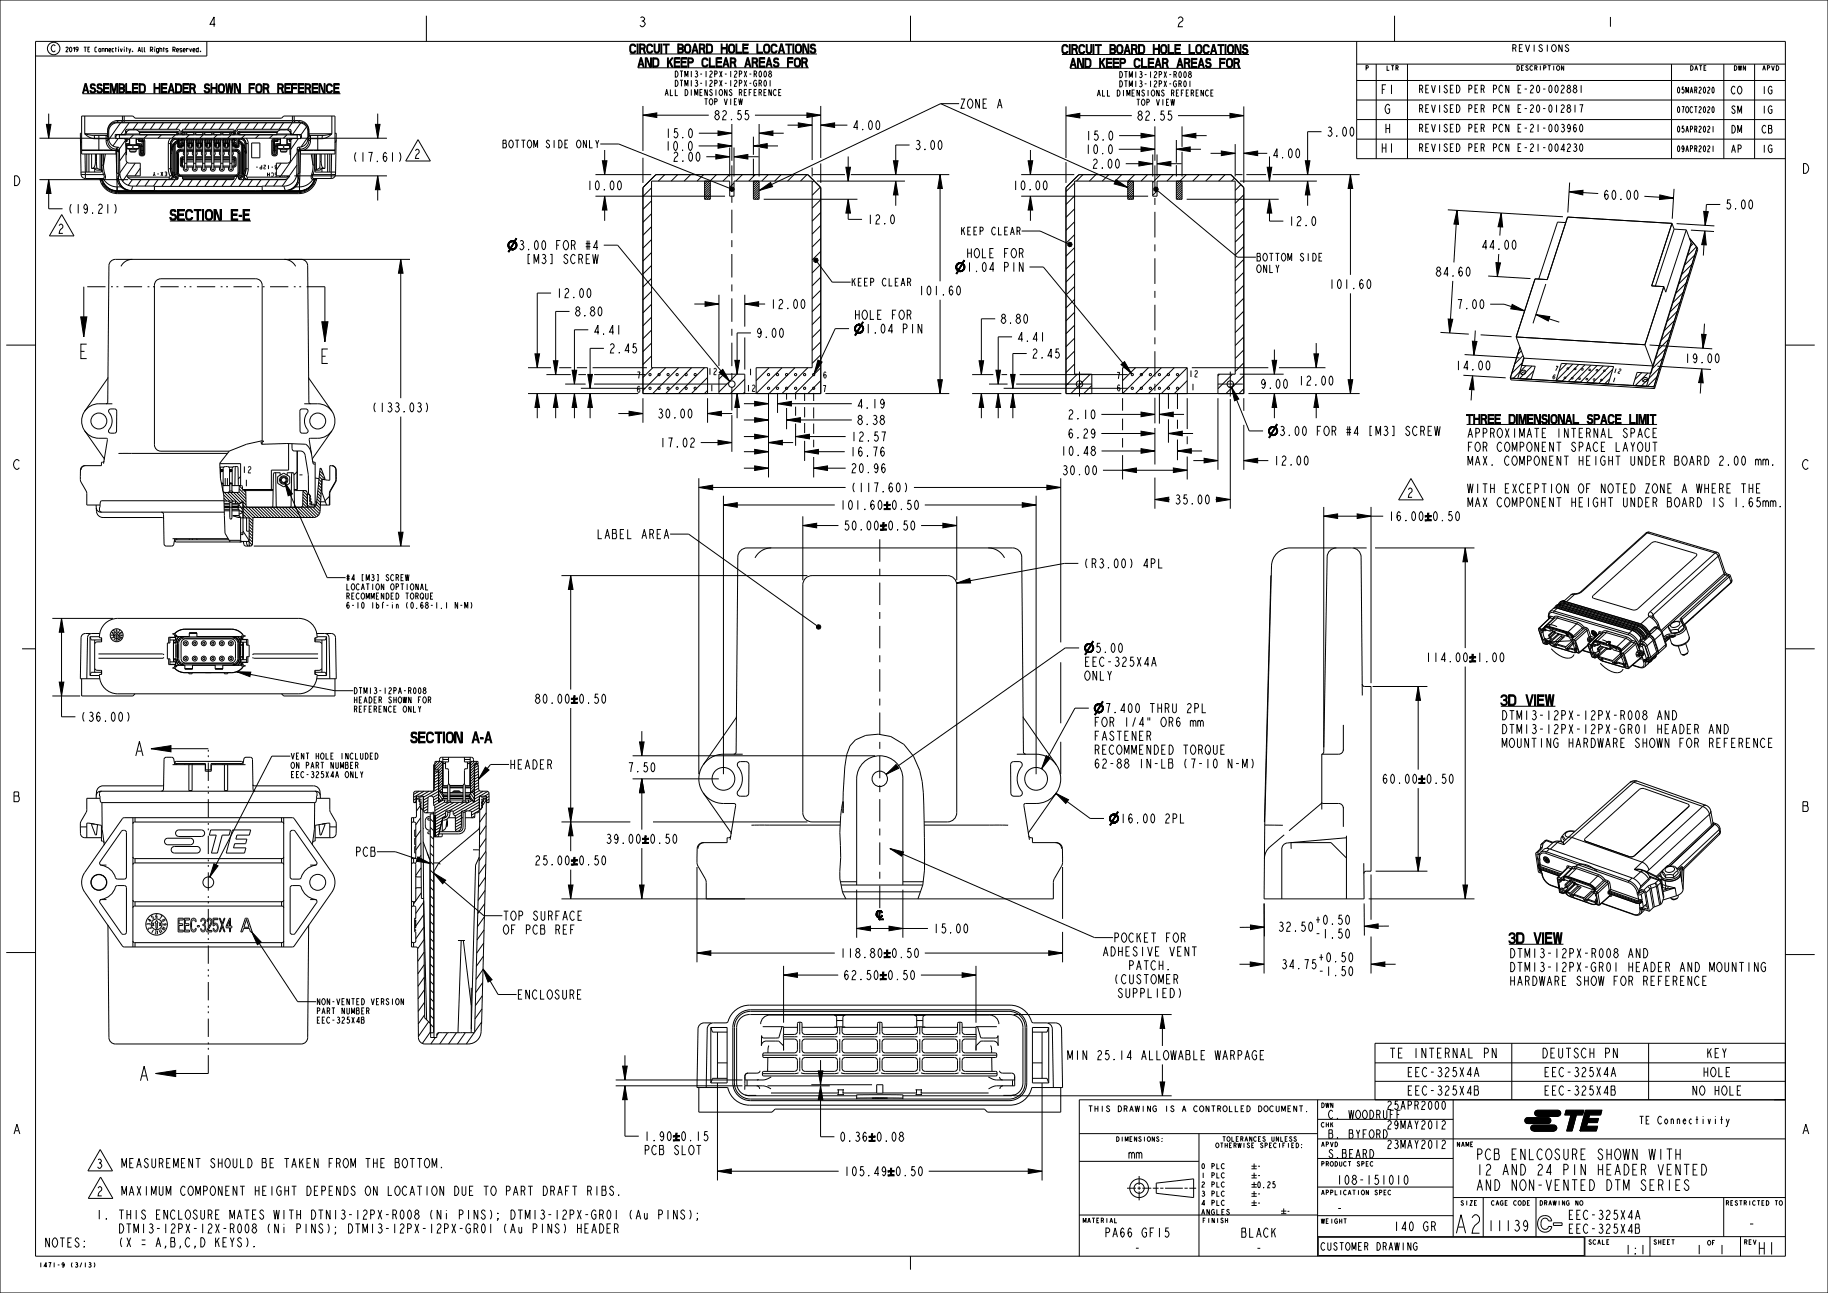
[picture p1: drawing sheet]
<svg xmlns="http://www.w3.org/2000/svg" width="594mm" height="420mm" viewBox="0 0 594 420" stroke-linecap="round" stroke-linejoin="round" font-family="sans-serif">
<defs><g id="words">
<text font-size="7.8" x="472.3" y="400.6">A2</text>
<text font-size="5.2" x="570.9" y="407.5">H1</text>
<g font-size="4.6">
<text x="54.2" y="71.6">SECTION E-E</text>
<text x="487.7" y="229.2">3D VIEW</text>
<text x="132.5" y="241.3">SECTION A-A</text>
<text x="490.3" y="306.5">3D VIEW</text>
<text x="479.5" y="376.7">PCB ENLCOSURE SHOWN WITH</text>
<text x="479.5" y="381.7">12 AND 24 PIN HEADER VENTED</text>
<text x="479.5" y="386.7">AND NON-VENTED DTM SERIES</text>
<text x="483.1" y="399.9">11139</text>
<text x="567.8" y="399.3">-</text>
</g>
<g font-size="4.1">
<text x="67.5" y="8.7">4</text>
<text x="207.2" y="8.7">3</text>
<text x="382.1" y="8.7">2</text>
<text x="521.8" y="8.7">1</text>
<text x="585.3" y="56.3">D</text>
<text x="4" y="60.3">D</text>
<text x="164.8" y="81.1">⌀3.00 FOR #4</text>
<text x="310.3" y="88.2">⌀1.04 PIN</text>
<text x="277.4" y="108.3">⌀1.04 PIN</text>
<text x="411.9" y="141.5">⌀3.00 FOR #4 [M3] SCREW</text>
<text x="4" y="152.5">C</text>
<text x="585.3" y="152.5">C</text>
<text x="352.2" y="212">⌀5.00</text>
<text x="355.3" y="231.5">⌀7.400 THRU 2PL</text>
<text x="4" y="260.4">B</text>
<text x="585.3" y="263.6">B</text>
<text x="360.2" y="267.4">⌀16.00</text>
<text x="284.4" y="298.8">℄</text>
<text x="451.7" y="343.7">TE INTERNAL PN</text>
<text x="501.1" y="343.7">DEUTSCH PN</text>
<text x="4" y="368.4">A</text>
<text x="585.3" y="368.4">A</text>
</g>
<g font-size="3.9">
<text x="202.3" y="17.3">CIRCUIT BOARD HOLE LOCATIONS</text>
<text x="342.7" y="17.5">CIRCUIT BOARD HOLE LOCATIONS</text>
<text x="207" y="21.8">AND KEEP CLEAR AREAS FOR</text>
<text x="347.4" y="22">AND KEEP CLEAR AREAS FOR</text>
<text x="26.8" y="30.2">ASSEMBLED HEADER SHOWN FOR REFERENCE</text>
<text x="311.7" y="35.2">ZONE A</text>
<text x="448.6" y="30.5">F1</text>
<text x="231.8" y="38.9">82.55</text>
<text x="369.3" y="39.1">82.55</text>
<text x="449.8" y="36.9">G</text>
<text x="216" y="44.8">15.0</text>
<text x="276.9" y="42.2">4.00</text>
<text x="352.6" y="45.6">15.0</text>
<text x="430.9" y="44.3">3.00</text>
<text x="449.8" y="43.2">H</text>
<text x="114.3" y="52.5">(17.61)</text>
<text x="134.4" y="51.5">2</text>
<text x="215.9" y="48.9">10.0</text>
<text x="218.4" y="52.4">2.00</text>
<text x="297.1" y="48.6">3.00</text>
<text x="352.4" y="50">10.0</text>
<text x="413.3" y="51.3">4.00</text>
<text x="448.6" y="49.6">H1</text>
<text x="354.7" y="54.7">2.00</text>
<text x="190.5" y="61.7">10.00</text>
<text x="328.8" y="61.7">10.00</text>
<text x="520.8" y="64.8">60.00</text>
<text x="21.8" y="69.3">(19.21)</text>
<text x="560.5" y="67.9">5.00</text>
<text x="18.6" y="75.8">2</text>
<text x="281.6" y="72.8">12.0</text>
<text x="418.5" y="73.3">12.0</text>
<text x="313.8" y="83.7">HOLE FOR</text>
<text x="481.2" y="81">44.00</text>
<text x="170.7" y="85.6">[M3] SCREW</text>
<text x="466.3" y="89.7">84.60</text>
<text x="298.3" y="95.9">101.60</text>
<text x="431.6" y="93.8">101.60</text>
<text x="180.6" y="96.7">12.00</text>
<text x="250.1" y="100.3">12.00</text>
<text x="473.1" y="100.3">7.00</text>
<text x="186.6" y="102.7">8.80</text>
<text x="277.4" y="103.8">HOLE FOR</text>
<text x="324.9" y="105.1">8.80</text>
<text x="192.7" y="108.6">4.41</text>
<text x="245.5" y="109.6">9.00</text>
<text x="330.4" y="110.9">4.41</text>
<text x="197.7" y="114.7">2.45</text>
<text x="335.1" y="116.3">2.45</text>
<text x="547.2" y="117.9">19.00</text>
<text x="421.7" y="125.1">12.00</text>
<text x="472.7" y="120.2">14.00</text>
<text x="409.3" y="126.2">9.00</text>
<text x="120.6" y="133.8">(133.03)</text>
<text x="213.4" y="135.8">30.00</text>
<text x="278.3" y="132.6">4.19</text>
<text x="278.3" y="137.9">8.38</text>
<text x="346.8" y="136.1">2.10</text>
<text x="476.6" y="137.6">THREE DIMENSIONAL SPACE LIMIT</text>
<text x="276.3" y="143.3">12.57</text>
<text x="346.8" y="142.3">6.29</text>
<text x="476.6" y="142.1">APPROXIMATE INTERNAL SPACE</text>
<text x="214.2" y="145.3">17.02</text>
<text x="276" y="148.2">16.76</text>
<text x="344.5" y="148">10.48</text>
<text x="476.6" y="146.6">FOR COMPONENT SPACE LAYOUT</text>
<text x="276.3" y="153.6">20.96</text>
<text x="344.9" y="154.3">30.00</text>
<text x="413.6" y="151.1">12.00</text>
<text x="476.6" y="151.1">MAX. COMPONENT HEIGHT UNDER BOARD 2.00 mm.</text>
<text x="276.3" y="159.8">(117.60)</text>
<text x="457" y="161.6">2</text>
<text x="476.6" y="160.1">WITH EXCEPTION OF NOTED ZONE A WHERE THE</text>
<text x="272.7" y="165.5">101.60±0.50</text>
<text x="381.5" y="163.7">35.00</text>
<text x="476.6" y="164.6">MAX COMPONENT HEIGHT UNDER BOARD IS 1.65mm.</text>
<text x="273.9" y="172.2">50.00±0.50</text>
<text x="451" y="169.2">16.00±0.50</text>
<text x="193.8" y="175">LABEL AREA</text>
<text x="351.9" y="184.5">(R3.00) 4PL</text>
<text x="463" y="215">114.00±1.00</text>
<text x="352.2" y="216.5">EEC-325X4A</text>
<text x="352.2" y="221">ONLY</text>
<text x="173.5" y="228.5">80.00±0.50</text>
<text x="487.7" y="233.8">DTM13-12PX-12PX-R008 AND</text>
<text x="26" y="234.3">(36.00)</text>
<text x="355.3" y="236">FOR 1/4&quot; OR6 mm</text>
<text x="487.7" y="238.3">DTM13-12PX-12PX-GR01 HEADER AND</text>
<text x="355.3" y="240.5">FASTENER</text>
<text x="355.3" y="245">RECOMMENDED TORQUE</text>
<text x="487.7" y="242.8">MOUNTING HARDWARE SHOWN FOR REFERENCE</text>
<text x="165.4" y="249.8">HEADER</text>
<text x="203.8" y="250.7">7.50</text>
<text x="355.3" y="249.5">62-88 IN-LB (7-10 N-M)</text>
<text x="448.9" y="254.5">60.00±0.50</text>
<text x="378.1" y="267.4">2PL</text>
<text x="196.6" y="274">39.00±0.50</text>
<text x="115.3" y="278.2">PCB</text>
<text x="173.5" y="281">25.00±0.50</text>
<text x="163.2" y="299">TOP SURFACE</text>
<text x="163.2" y="303.5">OF PCB REF</text>
<text x="303" y="303.1">15.00</text>
<text x="415.1" y="302.5">32.50</text>
<text x="427.1" y="300.3">+0.50</text>
<text x="427.1" y="304.8">-1.50</text>
<text x="272.7" y="311.1">118.80±0.50</text>
<text x="358.5" y="310.6">ADHESIVE VENT</text>
<text x="362" y="306.1">POCKET FOR</text>
<text x="490.3" y="311.1">DTM13-12PX-R008 AND</text>
<text x="366.7" y="315.1">PATCH.</text>
<text x="416.1" y="314.7">34.75</text>
<text x="428.1" y="312.5">+0.50</text>
<text x="428.1" y="317">-1.50</text>
<text x="490.3" y="315.6">DTM13-12PX-GR01 HEADER AND MOUNTING</text>
<text x="273.9" y="318.2">62.50±0.50</text>
<text x="362" y="319.6">(CUSTOMER</text>
<text x="490.3" y="320.1">HARDWARE SHOW FOR REFERENCE</text>
<text x="167.9" y="324.5">ENCLOSURE</text>
<text x="363.1" y="324.1">SUPPLIED)</text>
<text x="346.5" y="344.2">MIN 25.14 ALLOWABLE WARPAGE</text>
<text x="554.4" y="343.6">KEY</text>
<text x="457.3" y="349.7">EEC-325X4A</text>
<text x="501.8" y="349.7">EEC-325X4A</text>
<text x="553.2" y="349.7">HOLE</text>
<text x="457.3" y="355.7">EEC-325X4B</text>
<text x="501.8" y="355.7">EEC-325X4B</text>
<text x="549.7" y="355.7">NO HOLE</text>
<text x="209.1" y="370.6">1.90±0.15</text>
<text x="272.6" y="370.7">0.36±0.08</text>
<text x="209.1" y="375.1">PCB SLOT</text>
<text x="366.5" y="376.3">mm</text>
<text x="31.1" y="379.5">3</text>
<text x="39.2" y="379.3">MEASUREMENT SHOULD BE TAKEN FROM THE BOTTOM.</text>
<text x="274" y="381.9">105.49±0.50</text>
<text x="31.3" y="388.5">2</text>
<text x="39.2" y="388.3">MAXIMUM COMPONENT HEIGHT DEPENDS ON LOCATION DUE TO PART DRAFT RIBS.</text>
<text x="434.1" y="384.8">108-151010</text>
<text x="434.1" y="394">-</text>
<text x="31.1" y="396">1. THIS ENCLOSURE MATES WITH DTN13-12PX-R008 (Ni PINS); DTM13-12PX-GR01 (Au</text>
<text x="38.1" y="400.5">DTM13-12PX-12X-R008 (Ni PINS); DTM13-12PX-12PX-GR01 (Au PINS) HEADER</text>
<text x="213.5" y="396">PINS);</text>
<text x="358.8" y="401.9">PA66 GF15</text>
<text x="403.1" y="401.9">BLACK</text>
<text x="452.6" y="399.8">140 GR</text>
<text x="509.4" y="396.1">EEC-325X4A</text>
<text x="509.4" y="400.6">EEC-325X4B</text>
<text x="14.3" y="405.1">NOTES:</text>
<text x="38.1" y="405">(X = A,B,C,D KEYS).</text>
<text x="368.4" y="407">-</text>
<text x="407.9" y="407">-</text>
<text x="527.9" y="407.4">1:1</text>
<text x="551" y="407.4">1</text>
<text x="558.4" y="407.4">1</text>
</g>
<g font-size="3.6">
<text x="431.4" y="363.4">C. WOODRUFF</text>
<text x="450.4" y="360.4">25APR2000</text>
<text x="431.4" y="369.7">B. BYFORD</text>
<text x="450.4" y="366.7">29MAY2012</text>
<text x="431.4" y="376.1">S.BEARD</text>
<text x="450.4" y="373.1">23MAY2012</text>
</g>
<g font-size="3.3">
<text x="460.8" y="30.2">REVISED PER PCN E-20-002881</text>
<text x="562.3" y="30.5">CO</text>
<text x="572.3" y="30.5">IG</text>
<text x="460.8" y="36.5">REVISED PER PCN E-20-012817</text>
<text x="562.3" y="36.9">SM</text>
<text x="572.3" y="36.9">IG</text>
<text x="460.8" y="42.9">REVISED PER PCN E-21-003960</text>
<text x="562.3" y="43.2">DM</text>
<text x="572.3" y="43.2">CB</text>
<text x="163.1" y="48">BOTTOM SIDE ONLY</text>
<text x="460.8" y="49.2">REVISED PER PCN E-21-004230</text>
<text x="562.3" y="49.6">AP</text>
<text x="572.3" y="49.6">IG</text>
<text x="312" y="76.3">KEEP CLEAR</text>
<text x="408.1" y="84.8">BOTTOM SIDE</text>
<text x="408.1" y="88.5">ONLY</text>
<text x="276.4" y="92.9">KEEP CLEAR</text>
<text x="532.4" y="365.1">TE Connectivity</text>
<text x="429" y="406.1">CUSTOMER DRAWING</text>
</g>
<g font-size="2.9">
<text x="16.4" y="16.8">C</text>
<text x="491" y="16.8">REVISIONS</text>
</g>
<g font-size="2.6">
<text x="219.4" y="25.1">DTM13-12PX-12PX-R008</text>
<text x="219.4" y="28.1">DTM13-12PX-12PX-GR01</text>
<text x="363.8" y="25.2">DTM13-12PX-R008</text>
<text x="363.8" y="28.2">DTM13-12PX-GR01</text>
<text x="216.3" y="31.1">ALL DIMENSIONS REFERENCE</text>
<text x="228.8" y="34.1">TOP VIEW</text>
<text x="356.7" y="31.2">ALL DIMENSIONS REFERENCE</text>
<text x="369.2" y="34.2">TOP VIEW</text>
<text x="544.7" y="30.3">05MAR2020</text>
<text x="544.7" y="36.6">07OCT2020</text>
<text x="544.7" y="43">05APR2021</text>
<text x="544.7" y="49.3">09APR2021</text>
<text x="112.3" y="188.6">#4 [M3] SCREW</text>
<text x="112.3" y="191.6">LOCATION OPTIONAL</text>
<text x="112.3" y="194.6">RECOMMENDED TORQUE</text>
<text x="112.3" y="197.6">6-10 lbf-in (0.68-1.1 N-M)</text>
<text x="114.8" y="225.4">DTM13-12PA-R008</text>
<text x="114.8" y="228.4">HEADER SHOWN FOR</text>
<text x="114.8" y="231.4">REFERENCE ONLY</text>
<text x="94.3" y="246.6">VENT HOLE INCLUDED</text>
<text x="94.3" y="249.6">ON PART NUMBER</text>
<text x="94.3" y="252.6">EEC-325X4A ONLY</text>
<text x="102.7" y="326.4">NON-VENTED VERSION</text>
<text x="102.7" y="329.4">PART NUMBER</text>
<text x="102.7" y="332.4">EEC-325X4B</text>
<text x="408.3" y="379.8">-</text>
<text x="408.3" y="382.9">-</text>
<text x="408.3" y="385.8">0.25</text>
<text x="408.3" y="388.8">-</text>
<text x="408.3" y="391.8">-</text>
<text x="417.9" y="394.5">-</text>
</g>
<g font-size="2.5">
<text x="354.3" y="361.1">THIS</text>
<text x="363.6" y="361.1">DRAWING</text>
<text x="378.4" y="361.1">IS</text>
<text x="384" y="361.1">A</text>
<text x="387.7" y="361.1">CONTROLLED</text>
<text x="408.1" y="361.1">DOCUMENT.</text>
</g>
<g font-size="2.2">
<text x="390.2" y="379.7">0</text>
<text x="390.2" y="382.6">1</text>
<text x="393.3" y="379.7">PLC</text>
<text x="393.3" y="382.6">PLC</text>
<text x="390.2" y="385.6">2</text>
<text x="390.2" y="388.6">3</text>
<text x="393.3" y="385.6">PLC</text>
<text x="393.3" y="388.6">PLC</text>
<text x="390.2" y="391.6">4</text>
<text x="390.2" y="394.6">ANGLES</text>
<text x="393.3" y="391.6">PLC</text>
</g>
<g font-size="2">
<text x="21.1" y="16.8">2019 TE Connectivity. All Rights Reserved.</text>
<text x="443.5" y="22.9">P</text>
<text x="450.4" y="22.9">LTR</text>
<text x="492.6" y="22.9">DESCRIPTION</text>
<text x="549" y="22.9">DATE</text>
<text x="563.2" y="22.9">DWN</text>
<text x="572.5" y="22.9">APVD</text>
<text x="429.2" y="359.8">DWN</text>
<text x="362.5" y="370.8">DIMENSIONS:</text>
<text x="397" y="370.7">TOLERANCES</text>
<text x="412.5" y="370.7">UNLESS</text>
<text x="429.2" y="366.1">CHK</text>
<text x="394.8" y="372.8">OTHERWISE</text>
<text x="408.9" y="372.8">SPECIFIED:</text>
<text x="429.2" y="372.5">APVD</text>
<text x="473.2" y="372.5">NAME</text>
<text x="429.2" y="378.8">PRODUCT</text>
<text x="440.4" y="378.8">SPEC</text>
<text x="429.2" y="388.1">APPLICATION</text>
<text x="446" y="388.1">SPEC</text>
<text x="474.4" y="391.5">SIZE</text>
<text x="484.4" y="391.5">CAGE</text>
<text x="491.5" y="391.5">CODE</text>
<text x="500.1" y="391.5">DRAWING</text>
<text x="511.4" y="391.5">NO</text>
<text x="560.6" y="391.5">RESTRICTED</text>
<text x="576.1" y="391.5">TO</text>
<text x="351.7" y="397.2">MATERIAL</text>
<text x="390.6" y="397.2">FINISH</text>
<text x="429.2" y="397.4">WEIGHT</text>
<text x="516" y="404.2">SCALE</text>
<text x="537.2" y="404.2">SHEET</text>
<text x="554.7" y="404.4">OF</text>
<text x="566.6" y="404.2">REV</text>
<text x="12.5" y="411.6">1471-9</text>
<text x="22.4" y="411.6">(3/13)</text>
</g>
</g></defs>
<path d="M26.2 102.9h2l-1 6.5zM104.6 104.5h2l-1 6.5zM49.1 243.2l6.5-1v2zM50.6 348.7l6.5-1v2zM495.8 363.3l.6-.3h6.6a.95 .95 0 0 1 .9 .9 .95 .95 0 0 1-.8 1l-6.7 .1a.95 .95 0 0 1-.8-.6 .95 .95 0 0 1 .2-1.1zM497.7 365.7l.7-.2h6.5a.95 .95 0 0 1 1 .8 .95 .95 0 0 1-.9 1l-6.6 .1a.95 .95 0 0 1-.9-.6 .95 .95 0 0 1 .2-1.1zM499 360.9l.6-.3h6.6a.95 .95 0 0 1 .9 .9 .95 .95 0 0 1-.8 1h-6.7a.95 .95 0 0 1-.8-.5 .95 .95 0 0 1 .2-1.1zM508.9 360.6h5.8l-.4 1.5h-2.1l-1.4 5.3h-1.7l1.4-5.3h-2zM515.8 364.6l-.3 1.3h3.6l-.4 1.5h-5.3zM516.5 362.1l-.3 1.2h3.2l-.3 1.3h-3.3l-2.4 2.8zM515.2 360.6h5.3l-.4 1.5h-3.6l-3.1 5.3z" fill="#000"/>
<g fill="none" stroke="#000" stroke-width=".32">
<path d="M0 0h594v420h-594zM11.6 13.4h568.6v394.6h-568.6zM67.2 13.4v4.8h-55.6M138.6 5.1v8.3M295.9 5.1v8.3M440.8 13.4v38.1h139.4M453.2 5.1v8.3M27.5 37.7v5.8M37.9 39.7l-1.1 .2-.9 .6-.6 .9-.2 1M37.9 39.7l.2 .2M37.9 39.7h1.4M38.1 39.9l-1 .2-.9 .6-.7 .9-.2 1.1"/>
<path d="M38.1 39.9h59.1M38.4 39.1l-.5 .6M38.4 39.1l-1.3 .3-1.1 .7-.8 1-.2 1.3M38.4 39.1l1.4 .1M39.2 39.9l-3.8 5.4M39.3 39.7h1.1M39.8 39.2l-.5 .5M39.8 37.7v1.5M39.8 39.2h55.8M40.4 37.7v2M40.4 39.7h54.6M42 39.9l-2.7 3.8"/>
<path d="M44.8 39.9l-1.5 2.1M47.5 39.9l-1.4 2.1M50.3 39.9l-1.4 2.1M53.1 39.9l-1.5 2.1M55.9 39.9l-1.5 2.1M58.7 39.9l-1.5 2.1M61.5 39.9l-1.5 2.1M64.3 39.9l-1.5 2.1M67.1 39.9l-1.5 2.1M69.9 39.9l-1.5 2.1M72.6 39.9l-1.4 2.1M75.4 39.9l-1.4 2.1"/>
<path d="M78.2 39.9l-1.9 2.7M81 39.9l-1.5 2.1M83.8 39.9l-1.5 2.1M86.6 39.9l-1.5 2.1M89.4 39.9l-1.5 2.1M92.2 39.9l-1.5 2.1M94.9 39.9l-1.4 2.1M95 37.7v2M95.6 39.2l.4 .5M95.6 37.7v1.5M96 39.7h-1M97 39.1l.5 .6"/>
<path d="M97 39.1l1.3 .3 1.1 .7 .7 1 .3 1.3M97 39.1l-1.4 .1M97.2 39.9l1.1 .2 .9 .6 .6 .9 .2 1.1M97.5 39.7l1.1 .2 .9 .6 .6 .9 .2 1M97.5 39.7h-1.5M97.5 39.7l-.3 .2M97.7 39.9l-2.6 3.8M107.8 37.7v5.8M440.8 26.1h139.4M440.8 32.5h139.4M440.8 20.8h139.4M440.8 38.8h139.4"/>
<path d="M447.2 20.8v30.7M457.4 20.8v30.7M513.3 34h1l-.5 2.5M543.1 20.8l.1 30.7M560.1 20.8l.1 30.7M570.1 20.8l.1 30.7M26.1 45.4l.4 .9M26.3 56.6a1.4 1.4 0 0 0 1.4 1.4M26.3 56.6l1.4 .1M26.5 48.7l.2 .2M26.5 48.7v-11h16.7l.7 .7h47.6l.7-.7h16.6v11M26.5 43.3h-.4l.2 13.3"/>
<path d="M26.5 48.7h10M27.5 43.5l1.7 1.2 1.5 .4M27.5 43.5l3 .5M27.5 43.5h7.6M27.6 50l.1 6.7M27.7 56.7h6M27.7 56.7v1.3M27.7 58h5.6M28.2 50v5.9M28.9 50v5.9M29.8 50v4.7h.9M30.2 54.6l-.4 .1"/>
<path d="M30.5 44l.2 1.1M30.5 44h4M30.7 45.1h4.3M31 52.5l-.2 1.5-.6 .6M31 50v2.5M31.3 52.5l.2 2.1M31.3 50v2.5M31.3 52.5h-.3M31.5 54.6l1 .5M31.5 54.6h-1.3M32.1 44v4.9M32.4 58a5.9 5.9 0 0 0 5.9 4.9h58.8a5.9 5.9 0 0 0 5.8-4.9"/>
<path d="M32.5 58.4h.5M32.5 55.1l.5 .1M32.5 50v5.1M32.7 58l.5 .4M32.8 58l.5 .4M33 55.3l-1.7-.1-.5-.4v1.1M33 50v5.9h-6.7M33 58.4h.1M33 58.4l.3 .1M33 58v.4M33 58.4l.5 1.4M33 58.4l.2 .1"/>
<path d="M33.1 59.8h.4M33.1 53.6l.5 .1M33.1 53.6l.6 3.1M33.2 50l-.1 3.6M33.2 58.4a5.1 5.1 0 0 0 4.9 3.6M33.3 58l.4 .3M33.3 58.4l.7 1.4 1.1 1.1 1.4 .8 1.5 .2M33.3 58.4h-.1M33.3 58h.1M33.5 59.8a5.6 5.6 0 0 0 4.8 2.8M33.5 59.8l.3-.1a5.2 5.2 0 0 0 4.5 2.5h58.8a5.2 5.2 0 0 0 4.5-2.5l.3 .1M33.5 48.9h4.5"/>
<path d="M33.6 53.7l.5 2.9M33.7 56.7l.2 .9-.6 .4M33.7 58.3l-.4 .1M33.7 50l-.1 3.7M33.7 58.3h.1M33.7 58.3l1.9 1.8 2.5 .6M34.1 56.6l.2 1.1-.6 .6M34.1 56.6l-.4 .1M34.2 50l-.6 3.7M34.5 45.6l.5 1.9 1.5 1.2M34.5 45.6h.5M34.5 44l.6 .5"/>
<path d="M35 42.4v1.2l-.5 .4M35 42.4h.1M35 45.6l.2 1.1 .6 .9 .9 .6 1.1 .2M35 45.1v.5M35 44.5l-.5-.5v1.6M35 44.5v.6M35 44.5h.1M35.1 43.5v1M35.1 42.4v1.1M35.1 42.4l.2 .3M35.3 45l.2 1.1 .7 .9 .9 .6 1 .2M35.3 42.7v2.3"/>
<path d="M35.3 45l-.3 .6M36.5 48.7v.2M36.5 48.7l1.4 .1M37.4 45h.1M37.4 44.3h.3M37.4 45h2.8l.6 .4 .2 6.6 .3 .7 .7 .3h3.6v4.1h-4.4l.8 .9 1.1 .4M37.7 44.3v.7M37.7 49h.2M37.7 49l.2 7.2M37.7 48.9v.1M37.8 48.4v.5M37.8 48.4h.1"/>
<path d="M37.9 48.9v.1M37.9 49v7.2M37.9 49l.5 .4M37.9 48.9l.5 .5M37.9 56.2v1.2M37.9 56.2l.6 .4M37.9 57.4l.1 .6M37.9 57.4l.6 .4M37.9 48.8h.3M37.9 48.4l.6 .6M37.9 48.4v.4M38 48.8h.1"/>
<path d="M38 48.8v.1M38 48.9l.5 .5M38 58l.4 1.4 .9 1.3M38 58l.5 .2M38 58l.1 2.7M38.1 47.8l-.3 .6M38.1 47.8h.2M38.2 48.8h.1M38.2 48.8l.3 .2M38.3 47.8l.5 .5M38.3 47.8l-.4 .6M38.3 43.8l-.4 .1-.2 .4"/>
<path d="M38.3 43.7v.1M38.3 43.8h58.8M38.4 45l-1.7 2.4M38.4 49.4l.1 7.2M38.4 49.4h.1M38.5 56.6v1.2M38.5 57.8v.4M38.5 49v.4M38.5 57.7l.3 1.6 .9 1.4 1.4 .9 1.6 .3M38.5 57.7v.1M38.5 58.2l.4 1.3 .8 1.2M38.8 48.3l.1 8"/>
<path d="M38.8 48.3l-.3 .7M38.9 56.3l.4 1.6 .9 1.4 1.3 .8 1.6 .4M38.9 56.3l-.4 1.4M40.4 45.1h.7M40.8 45.4h.3M40.8 42.6h.5M40.8 43.1h.3M40.8 43l.1-.7 .4-.3h16.8l.2 .6h1l.2-.6h16.4l.1 .6h1.1l.2-.6h16.8l.4 .3 .1 .7M40.8 43l-.6 .7h-2.8v1.3M40.8 43h.3M40.8 45.5l-2 2.9M40.9 47.5h.3"/>
<path d="M40.9 49.4l-2 2.9M40.9 49.9h.2M41 46.7h-.1M41 47h-.1M41 46.7v.3M41 47l.1 .2M41 46.7h1M41.1 47.2l-.2 .1M41.1 49.9l-.2 .5M41.1 47.2v2.7M41.1 47.2h.3M41.1 45.1v.3"/>
<path d="M41.1 44.9v.2M41.1 45.4l.2 .2h-.5M41.3 44.9v.4M41.3 45.3v.7h-.4M41.3 45.3h.7M41.3 52.7l-2.4 3.5M41.5 57.5h13.5M42 44.9v2.1h-1M42.1 49.1h2.1l-.2 .3h-1.6zM42.2 42.2l-1 .6-.2 .7M42.2 42.2h.1M42.3 42.2h1.9"/>
<path d="M42.4 42.2h-.2M43 58.3l-1.3 1.9M43.4 43.8l-1.1 1.1M43.9 53l-4.1 5.9M44.2 42.2h.1M44.2 42.2l1 .6 .2 .7M44.3 44.9v2.1h1.1M44.3 46.7h1.1M44.3 45.3h.7M45 47.2h.2M45 45.3v.7h1.5M45 44.9v.4"/>
<path d="M45 42.6h12.5M45.1 47.5h.5M45.2 45.4l-.2 .2h1.2M45.2 45.4h1.1M45.2 45.1v.3M45.2 44.9v.2M45.2 45.1h1.1M45.2 47.2l.4 .3M45.2 49.9l.2 .5 .5 .2M45.2 47.2v2.7M45.2 49.9h.4M45.3 43h12.2"/>
<path d="M45.3 43.1h12.1M45.4 46.7l.6 .3 .1 .4h-.4M45.4 47l.3 .4M45.4 46.7v.3M45.4 47l-.2 .2M45.6 54.7l-1.8 2.4M45.6 49.9l.3 .4M45.6 47.5v2.4M45.7 48.6l.4 .3M45.7 48.6l-.1 1.3M45.7 47.5v1.1M45.7 47.4v.1"/>
<path d="M45.7 47.4l-.1 .1M45.7 47.5h.8M45.8 58.4l-1.5 2.1M45.9 50.3v.3M45.9 50.6h.4M45.9 50.3h.4M46.1 48.9l-.2 1.4M46.1 48.9h.1M46.1 47.5v1.4M46.2 45.6l.3 .4M46.2 47.5v1.4M46.2 45.6v1.9"/>
<path d="M46.2 48.9l.1 1.4M46.3 45.1l.5 .2 .2 .5M46.3 45.4l.4 .4M46.3 45.1v.3M46.3 45.4l-.1 .2M46.3 50.3v.3M46.5 47.5v1.1M46.5 46v1.5M46.5 48.6l-.3 .3M46.5 48.6l.2 1.3M46.7 49.9l-.4 .4M46.7 45.8v4.1"/>
<path d="M46.7 45.8l-.2 .2M46.7 49.9h.3M46.7 45.8h.3M47 49.9l-.2 .5-.5 .2M47 45.8v4.1M47.9 43.8l-1.1 1.1M48.6 58.4l-1.5 2.1M51.3 58.4l-1.4 2.1M52.4 43.8l-1.1 1.1M54.1 58.4l-1.5 2.1M54.7 54.8l.5 2.3M54.7 46.6v8.2"/>
<path d="M54.7 54.8h1.1M54.7 46.6h.7M55.2 57.1l-.2 .4M55.4 44.9l-.5 .8-.2 .9M55.4 46.6l.2 9.5a1.32 1.32 0 0 1-.4 2.1l-12.7 .1M55.4 46.6v.1M55.4 49.8h.4M55.4 46.7h.4M55.8 47.5l-.4 2.3M55.8 46.7v.8M55.8 47.5l.2 .1M55.8 54.8l.4 1.8"/>
<path d="M55.8 49.8v5M55.9 48l-.4 1.5v5.3l.4 2M55.9 48l.3 .1M55.9 56.8h.1M55.9 56.8l.1 .4M55.9 56.8l-.7 .3M56 47.6l-.6 2.2M56 57.2l-.1 .5-.6 .6h-.3v-.8M56.2 56.1v.5M56.2 48.1l-.4 1.7M56.2 48.1v8M56.2 56.1h.7"/>
<path d="M56.2 56.6l.1 .1M56.2 56.6l-.3 .2M56.3 56.7l.1 .4M56.3 56.7l-.4 .1M56.4 57.1l-.1 .7-.4 .6M56.4 57.1l1.1 1.2M56.4 57.1l-.4 .1M56.5 47v9.1l.5 1.4 .8 .6M56.5 47l-.3 1.1M56.6 47h-.1M56.6 47h.3M56.6 47h.1"/>
<path d="M56.6 46.9l-.7 1.1M56.6 46.9v.1M56.6 46.8v.1M56.6 46.8h.1M56.7 46.8l-.1 .1M56.7 46.8l.2 .2M56.8 44.9l-1 .6-.4 1.1M56.9 56.1l.4 1.1 .6 .5M56.9 47v9.1M56.9 58.4l-1.5 2.1M57 43.8l-1.1 1.1M57.1 44.9l-1.2 .6-.5 1.2"/>
<path d="M57.2 45.3l-1 .4-.4 1M57.2 44.9v.4M57.2 45.3h.6M57.3 56.1l.6 1.2M57.3 49.8v6.3M57.3 56.1h.7M57.3 49.8h.7M57.4 43.8h.1M57.4 43.1l.4 .3M57.4 43.1v.7M57.5 44.9v.8M57.5 45.7l-1.7 1.8"/>
<path d="M57.5 45.7l.1 .2M57.5 43l.4 .3M57.5 42.6l.5 .2 .2 .5M57.5 43l-.1 .1M57.5 42.6v.4M57.6 45.9l-1.6 1.7M57.6 46.4l-.7 .6M57.6 47.3l.2 .5 .5 .2M57.6 46.4v.9M57.6 47.3h1.4M57.6 46.4h.3M57.7 45.9h.1"/>
<path d="M57.7 45.9h-.1M57.8 45.9l-1.1 .9M57.8 45.9l-.2 .5M57.8 43.8h.1M57.8 43.4v.4M57.8 44.9h.1M57.8 44.9v.4M57.8 45.6l.1 .1M57.8 45.6l-.1 .3M57.8 45.6l-.3 .1M57.8 45.3v.3M57.9 43.3v.5"/>
<path d="M57.9 43.3l-.1 .1M57.9 43.3h.3M57.9 57.2h1.4v.9l.5 .3h15.8l.4-.4 .1-.8h1.4M57.9 57.2l-.1 .8-.4 .4-14.6-.1M57.9 45.7v.7M57.9 45.7l-.1 .2M57.9 46.4v1l.4 .3M58 44.9v2.5l.4 .3v-2.8M58 56.1l.2 .5 .5 .2M58 49.8v6.3M58.2 43.3v.5M58.3 47.7v.3"/>
<path d="M58.3 48h.4M58.3 47.7h.4M58.6 46.9v.8l.3-.2v-.6M58.6 44.9v.9M58.6 46.9h.3M58.6 53.6l.2 .5 .5 .2M58.6 51.6v2M58.6 53.6h.4M58.6 51.6h.4M58.7 47.7v.3M58.7 48.4a1.42 1.42 0 0 0-1.4 1.4M58.7 49.2l-.5 .2-.2 .4"/>
<path d="M58.7 48.4v.8M58.7 56.8v.4M58.7 57.2h18M58.7 56.8h18M58.7 49.2h1.2M58.7 48.4h1.3M58.7 43.3v.5M58.7 43.3h.4M58.9 45.2l.3 .2M58.9 44.9v.3M58.9 45.2l-.3 .6M58.9 46.9l.2 .1"/>
<path d="M59 47.5l-.3 .2M59 47.5l.2 .2M59 53.6l.1 .3h.9M59 52.5l1 .1M59 51.6v2M59 47.3l.3 .2M59 47.3v.2M59 47.1l.3 .2M59 47.1v.2M59.1 43.3v.5M59.1 43.3v.1M59.1 47l.3 .3"/>
<path d="M59.1 47l-.1 .1M59.1 47h.1M59.1 45l.3 .3M59.1 45l.2 .1M59.1 45l-.2 .2M59.1 44.9v.1M59.1 44.9h.1M59.1 43.4v.4M59.1 43.8h.1M59.2 46.2l-.5 .2-.1 .5M59.2 45.4v.8M59.2 45.4l-.6 .4"/>
<path d="M59.2 46.2v.3M59.2 47.7l-.5 .3M59.2 47.7h.8M59.2 45.4h.1M59.2 46.5l-.3 .4M59.3 44.9v.2M59.3 46.5h.2M59.3 46.5h-.1M59.3 46.5l.1 .2M59.3 57.9h16.8M59.3 57.6h16.8M59.3 47.5l-.1 .2"/>
<path d="M59.3 47.3v.2M59.3 47.3h.7M59.3 50.9l-.5 .2-.2 .5M59.3 50.9v3.4M59.3 54.3h.5M59.3 50.9h.7M59.3 45.1h.2M59.3 45.1l.1 .2M59.4 47.3h-.1M59.4 47.3h.1M59.4 45.3h.1M59.4 47.3h.6"/>
<path d="M59.4 45.3l-.2 .1M59.4 46.2h.5l-.4 .3M59.4 46.2h-.2M59.4 46.2l-.1 .3M59.4 45.4v-.2h16.5v.2M59.4 45.4h16.5M59.4 45.4h-.2M59.4 42.6l-.5 .2-.2 .5M59.4 43l-.3 .3M59.4 42.6v.4M59.4 43l.1 .1M59.4 43h16.5"/>
<path d="M59.4 42.6h16.5M59.4 47v.3M59.4 47h.1M59.4 46.7l-.3 .3M59.4 46.7v.3M59.5 44.9v.3M59.5 43.1l-.4 .3M59.5 43.1v.7M59.5 43.1h.7M59.5 43.8h.1M59.5 45.1l.4 .1M59.5 45.1v.1"/>
<path d="M59.5 46.5v.5M59.5 58.3h16.3M59.6 46.7h-.2M59.6 46.7v.2M59.6 45.4l.3 .4h-1.3M59.6 46.9l-.1 .1M59.6 46.9h.4M59.7 58.3l-1.5 2.2M59.8 54.3a.8 .8 0 0 0 0 1.1 .8 .8 0 0 0 1.1 0 .8 .8 0 0 0 0-1.1M59.8 45.4l.1 .2M59.9 45.6h.1M59.9 46.3l-.3 .4"/>
<path d="M59.9 45.6v.7M59.9 46.3h.1M59.9 49.2l-.3 .7 .4 .7M60 49.1l-.1 .1M60 54.1l-.2 .2M60 48.8h-1.6l-.6 .4-.2 .6v6.3l.5 .9 .6 .2M60 48.8l-1.6 .1-.5 .3-.2 .6v6.3l.2 .7 .8 .4M60 45.4v9.4l.3 .4 .4-.4v-9.4M60 52h-.9l-.1 .3M60 51.3h-.9l-.1 .3M60 51.4h-.8l-.2 .2M60 51.9h-.8l-.2 .2"/>
<path d="M60 43.5v.3M60 44.9v.3M60 53h.7M60 46.7l-.4 .2M60.3 42.9l-.1 .1M60.3 42.9h.1M60.4 42.9l.1 .1M60.5 43.1h2.6M60.7 46.8l.3 .1M60.7 43.5v.3M60.7 44.9v.3M60.7 53.9h2.2"/>
<path d="M60.7 52.6h2.2M60.7 52h2.2M60.7 51.9h2.2M60.7 51.4h2.2M60.7 51.3h2.2M60.7 50.9h2.2M60.7 48.8h2.2M60.7 48.4h2.2M60.7 47.7h.5M60.7 47.3h.5M60.7 46.9h.3M60.7 46.3h.1"/>
<path d="M60.7 45.6h.1M60.7 54.1l.2 .2M60.7 49.1l.1 .1M60.7 46.3l.3 .4M60.7 45.6v.7M60.7 45.5v.1M60.8 49.2l.3 .7-.4 .7M60.8 49.2h2.1M60.8 45.4l-.1 .1M60.9 54.3h1.8M61 46.9l.1 .1M61 45.4l-.3 .4h2.2l-.3-.4"/>
<path d="M61 46.7l.4 .2M61 46.7v.2M61.1 46.5l-.4-.3h2.2l-.4 .3M61.1 46.6l.4 .3M61.1 45.1l-.4 .1M61.1 47l.1 .3M61.1 45.1v.1M61.1 46.5v.5M61.1 45.1h1.4M61.2 47.3h.1M61.2 47.6v.1M61.2 47.3v.3"/>
<path d="M61.2 47.7l.6 .4 .6-.4M61.4 47.2l-.2 .1M61.4 47.1v.1M61.4 47h.1M61.5 47h.1M61.5 47l-.1 .1M61.5 46.5h-.4M61.5 47l-.3 .3M61.5 47.1l-.2 .2h-.6M61.5 47.5l-.3 .1M61.5 47.5v.1M61.5 45.4v1.1"/>
<path d="M61.5 46.9v.6M61.5 46.5h.6M61.5 47.6l.3 .2 .3-.2M61.5 47.6l-.3 .1M61.5 43.8l-1.1 1.1M62.1 47.6l.3 .1M62.1 46.5h.4M62.1 45.4v1.1M62.2 47.5l-.1 .1M62.2 46.8l-.4-.3-.3 .4M62.2 46.8v.1M62.2 47.5h.1"/>
<path d="M62.2 47.5l.2 .1M62.2 47.1l.1 .2h.6M62.2 47v.2M62.2 46.9v.6M62.2 47h.1M62.2 46.9v.1M62.2 46.9h.1M62.2 47.2l.2 .1M62.4 47.7h.5M62.4 47.6v.1M62.4 47.3v.3M62.4 47.3h.1"/>
<path d="M62.4 47.3h.5M62.5 58.4l-1.5 2.1M62.5 46.6h-1.4M62.5 46.6l-.3 .2M62.5 45.1l.4 .1M62.5 45.1v.1M62.5 46.5v.2M62.5 46.6h.1M62.5 46.7l-.3 .2M62.5 46.7v.3M62.5 46.6l-.3 .3M62.5 47l-.1 .3"/>
<path d="M62.6 46.7h-.1M62.6 46.7v.2M62.6 46.9l-.1 .1M62.6 46.9h.3M62.7 54.3a.8 .8 0 0 0 0 1.1 .8 .8 0 0 0 1.1 0 .8 .8 0 0 0 .1-1.1M62.8 45.4l.1 .2M62.9 45.6h.1M62.9 46.3l-.3 .4M62.9 45.6v.7M62.9 46.3h.1M62.9 49.2l-.4 .7 .4 .7M62.9 49.1v.1"/>
<path d="M62.9 54.1l-.2 .2M62.9 45.4v9.4l.4 .4 .3-.4v-9.4M62.9 43.5v.3M62.9 44.9v.3M62.9 53h.7M62.9 46.8l-.3 .1M63.3 42.9l-.1 .1M63.3 42.9h.1M63.3 42.9l.1 .1M63.5 43.1h2.5M63.6 46.3h.1M63.6 46.8l.4 .1"/>
<path d="M63.6 43.5v.3M63.6 44.9v.3M63.6 53.9h2.3M63.6 52.6h2.3M63.6 52h2.3M63.6 51.9h2.3M63.6 51.4h2.3M63.6 51.3h2.3M63.6 50.9h2.3M63.6 48.8h2.3M63.6 48.4h2.3M63.6 47.7h.6"/>
<path d="M63.6 47.3h.5M63.6 46.9h.4M63.6 45.6h.1M63.6 54.1l.3 .2M63.6 49.1l.1 .1M63.7 49.2l.4 .7-.5 .7M63.7 49.2h2.1M63.7 46.3l.3 .4M63.7 45.6v.7M63.7 45.6h.1M63.7 45.5v.1M63.8 45.4l-.1 .1"/>
<path d="M63.9 54.3h1.7M64 46.9v.1M64 45.4l-.3 .4h2.1l-.3-.4M64 46.7h.1M64 46.7v.2M64 47l.1 .3M64 46.7l.4 .2M64 46.7v.3M64 46.6l.4 .3M64 46.6v.1M64.1 46.5l-.4-.3h2.1l-.4 .3M64.1 46.6h1.3"/>
<path d="M64.1 46.6l.3 .2M64.1 45.1l-.4 .1M64.1 46.6h-.1M64.1 45.1v.1M64.1 46.5v.1M64.1 45.1h1.3M64.1 47.3h.1M64.1 47.6l.1 .1M64.1 47.3v.3M64.2 47.7l.5 .4 .6-.4M64.3 47.2l-.2 .1M64.3 47.2h.1"/>
<path d="M64.4 46.9h.1M64.4 47.1l-.1 .1M64.4 46.9v.1M64.4 47h.1M64.4 47v.1M64.4 47l-.1 .2M64.4 47.1l-.2 .2h-.6M64.4 47.5l-.3 .1M64.4 47.5v.1M64.4 46.9v.6M64.4 46.8v.1M64.4 46.8l.4-.3 .3 .3"/>
<path d="M64.4 47.6l.3 .2 .4-.2M64.4 47.6l-.2 .1M64.4 46.5h-.3M64.4 45.4v1.1M64.4 46.5h.7M65.1 47.6l.2 .1M65.1 46.5h.3M65.1 45.4v1.1M65.1 47.5v.1M65.1 46.8v.1M65.1 47.5h.1M65.1 47.5l.3 .1"/>
<path d="M65.1 47.1l.2 .2h.6M65.1 47l.1 .2M65.1 46.9v.6M65.1 47h.1M65.1 46.9v.1M65.1 46.9h.1M65.2 47.2l.2 .1M65.3 58.4l-1.5 2.1M65.3 47.7h.6M65.4 47.6l-.1 .1M65.4 47.3v.3M65.4 47.3h.1"/>
<path d="M65.4 47.3h.5M65.4 46.6l-.3 .2M65.4 45.1l.4 .1M65.4 46.6h.1M65.4 45.1v.1M65.4 46.5v.1M65.4 46.7l-.3 .2M65.4 46.7l.1 .3M65.4 46.6l-.3 .3M65.4 46.6v.1M65.5 47l-.1 .3M65.5 46.7h-.1"/>
<path d="M65.5 46.7v.2M65.5 46.9v.1M65.5 46.9h.4M65.6 54.3a.8 .8 0 0 0 .1 1.1 .8 .8 0 0 0 1.1 0 .8 .8 0 0 0 0-1.1M65.7 45.4l.1 .2M65.8 45.6h.1M65.8 46.3l-.3 .4M65.8 45.6v.7M65.8 46.3h.1M65.8 49.2l-.4 .7 .5 .7M65.9 49.1l-.1 .1M65.9 54.1l-.3 .2"/>
<path d="M65.9 45.4v9.4l.3 .4 .4-.4v-9.4M65.9 43.5v.3M65.9 44.9v.3M65.9 53h.7M65.9 46.8l-.4 .1M66 43.8l-1.1 1.1M66.2 42.9l-.1 .1M66.2 42.9h.1M66.2 42.9l.1 .1M66.4 43.1h2.6M66.6 46.3h.1M66.6 46.8l.3 .1"/>
<path d="M66.6 43.5v.3M66.6 44.9v.3M66.6 53.9h2.2M66.6 52.6h2.2M66.6 52h2.2M66.6 51.9h2.2M66.6 51.4h2.2M66.6 51.3h2.2M66.6 50.9h2.2M66.6 48.8h2.2M66.6 48.4h2.2M66.6 47.7h.5"/>
<path d="M66.6 47.3h.5M66.6 46.9h.3M66.6 45.6h.1M66.6 54.1l.2 .2M66.6 49.1v.1M66.6 49.2l.4 .7-.4 .7M66.6 49.2h2.1M66.6 46.3l.3 .4M66.6 45.6v.7M66.7 45.5l-.1 .1M66.7 45.4v.1M66.8 54.3h1.8"/>
<path d="M66.9 46.9l.1 .1M66.9 45.4l-.3 .4h2.1l-.2-.4M66.9 46.7h.1M66.9 46.7v.2M67 47l.1 .3M67 46.7l.3 .2M67 46.7v.3M67 46.6l.3 .3M67 46.6h.1M67 46.5l-.4-.3h2.1l-.3 .3M67 46.6h1.4M67 45.1l-.4 .1"/>
<path d="M67 46.6l.3 .2M67 45.1v.1M67 46.5v.2M67 45.1h1.4M67.1 47.3h.1M67.1 47.6v.1M67.1 47.3v.3M67.1 47.7l.6 .4 .5-.4M67.2 47.2l-.1 .1M67.3 46.9h.1M67.3 47h.1M67.3 47l-.1 .2"/>
<path d="M67.3 47.1l-.2 .2h-.5M67.3 47.5l-.2 .1M67.3 47.5v.1M67.3 46.9v.6M67.3 46.8v.1M67.3 46.8l.4-.3 .3 .3M67.3 47.6l.4 .2 .3-.2M67.3 47.6l-.2 .1M67.4 46.5h-.4M67.4 45.4v1.1M67.4 46.5h.6M68 47.6l.2 .1"/>
<path d="M68 46.5h.4M68 45.4v1.1M68 47.5v.1M68 46.8v.1M68 47.5h.1M68 47.5l.3 .1M68 47.1l.2 .2h.6M68 47l.1 .2M68 46.9v.6M68 47h.1M68 47v.1M68 47.1l.1 .1"/>
<path d="M68.1 46.9l-.1 .1M68.1 47.2h.1M68.1 58.4l-1.6 2.1M68.1 46.9h.1M68.1 47.2l.2 .1M68.2 47.7h.6M68.3 47.6l-.1 .1M68.3 47.3v.3M68.3 47.3h.1M68.3 47.3h.5M68.4 45.1l.3 .1M68.4 46.6l-.4 .2"/>
<path d="M68.4 45.1v.1M68.4 46.5v.2M68.4 46.6h.1M68.4 46.7l-.3 .2M68.4 46.7v.3M68.4 46.6l-.4 .3M68.4 47l-.1 .3M68.4 46.7l.1 .2M68.4 46.7h.1M68.5 46.9l-.1 .1M68.5 46.9h.3M68.6 54.3a.8 .8 0 0 0 0 1.1 .8 .8 0 0 0 1.1 0 .8 .8 0 0 0 0-1.1"/>
<path d="M68.7 45.4v.2M68.7 45.6h.1M68.7 46.3l-.3 .4M68.7 45.6v.7M68.7 46.3h.1M68.7 49.2l-.3 .7 .4 .7M68.8 49.1l-.1 .1M68.8 54.1l-.2 .2M68.8 45.4v9.4l.4 .4 .3-.4v-9.4M68.8 53h.7M68.8 43.5v.3M68.8 44.9v.3"/>
<path d="M68.8 46.8l-.3 .1M69.1 42.9v.1M69.1 42.9h.1M69.2 42.9l.1 .1M69.3 43.1h2.6M69.5 46.3h.1M69.5 46.8l.3 .1M69.5 53.9h2.2M69.5 52.6h2.2M69.5 52h2.2M69.5 51.9h2.2M69.5 51.4h2.2"/>
<path d="M69.5 51.3h2.2M69.5 50.9h2.2M69.5 43.5v.3M69.5 44.9v.3M69.5 48.8h2.2M69.5 48.4h2.2M69.5 47.7h.5M69.5 47.3h.5M69.5 46.9h.3M69.5 45.6h.1M69.5 54.1l.2 .2M69.5 49.1h.1"/>
<path d="M69.6 49.2l.3 .7-.4 .7M69.6 49.2h2.1M69.6 46.3v.1M69.6 46.4l.3 .3M69.6 45.6h.1M69.6 45.5v.1M69.6 45.4v.1M69.6 46.4v-.2h2.1l-.4 .3M69.6 46.4l.3 .1M69.7 54.3h1.8M69.8 46.9l.1 .1M69.8 45.4l-.2 .4h2.1l-.3-.4"/>
<path d="M69.9 46.7h.1M69.9 46.7l-.1 .2M69.9 47l.1 .3M69.9 46.7l.3 .2M69.9 46.7v.3M69.9 46.6l.4 .3M69.9 46.6h.1M69.9 46.5h1.8M69.9 46.6h1.4M69.9 46.6l.4 .2M69.9 45.1l-.3 .1M69.9 45.1v.1"/>
<path d="M69.9 46.5v.2M69.9 45.1h1.4M70 47.3h.1M70 47.6v.1M70 47.3v.3M70 47.7l.6 .4 .6-.4M70.2 47.2l-.2 .1M70.3 47h.1M70.3 47l-.1 .2M70.3 47.1l-.2 .2h-.6M70.3 47.5l-.3 .1M70.3 47.5v.1"/>
<path d="M70.3 46.9v.6M70.3 46.8v.1M70.3 46.8l.3-.3 .4 .3M70.3 47.6l-.3 .1M70.3 47.6l.3 .2 .3-.2M70.3 46.5h-.4M70.3 45.4v1.1M70.3 46.5h.6M70.6 43.8l-1.1 1.1M70.9 58.4l-1.6 2.1M70.9 47.6l.3 .1M70.9 46.5h.4"/>
<path d="M70.9 45.4v1.1M71 46.8v.1M71 47.5l-.1 .1M71 47.5l.2 .1M71 47.1l.1 .2h.6M71 47l.2 .3M71 46.9v.6M71 47h.1M71 47v.1M71 47.1v.1M71 46.9v.1M71 47.2l.2 .1"/>
<path d="M71 46.9h.1M71.2 47.7h.5M71.2 47.6v.1M71.2 47.3v.3M71.2 47.3h.1M71.2 47.3h.5M71.3 46.6l-.3 .2M71.3 45.1l.4 .1M71.3 45.1v.1M71.3 46.5v.2M71.3 46.6h.1M71.3 46.7l-.3 .2"/>
<path d="M71.3 46.7v.3M71.3 46.6l-.3 .3M71.3 47l-.1 .3M71.4 46.7h-.1M71.4 46.7v.2M71.4 46.9l-.1 .1M71.4 46.9h.3M71.5 54.3a.8 .8 0 0 0 0 1.1 .8 .8 0 0 0 1.1 0 .8 .8 0 0 0 .1-1.1M71.6 45.4l.1 .2M71.7 45.6h.1M71.7 46.3l-.3 .4M71.7 45.6v.7"/>
<path d="M71.7 46.3h.1M71.7 49.2l-.4 .7 .4 .7M71.7 49.1v.1M71.7 54.1l-.2 .2M71.7 45.4v9.4l.4 .4 .3-.4v-9.4M71.7 53h.7M71.7 43.5v.3M71.7 44.9v.3M71.7 46.8l-.3 .1M72 43h.2M72.3 43.1h2.5M72.4 46.3h.1"/>
<path d="M72.4 46.8l.4 .1M72.4 43.5v.3M72.4 44.9v.3M72.4 53.9h2.3M72.4 52.6h2.3M72.4 52h2.3M72.4 51.9h2.3M72.4 51.4h2.3M72.4 51.3h2.3M72.4 50.9h2.3M72.4 48.8h2.3M72.4 48.4h2.3"/>
<path d="M72.4 47.7h.6M72.4 47.3h.5M72.4 46.9h.4M72.4 45.6h.1M72.4 54.1l.3 .2M72.4 49.1l.1 .1M72.5 49.2l.4 .7-.5 .7M72.5 49.2h2.1M72.5 46.3v.1M72.5 45.6v.7M72.5 46.4l.3 .3M72.5 45.6h.1"/>
<path d="M72.5 45.5v.1M72.6 45.4l-.1 .1M72.6 46.4l-.1-.2h2.1l-.4 .3M72.6 46.4l.3 .1M72.7 54.3h1.7M72.8 46.9v.1M72.8 45.4l-.3 .4h2.1l-.3-.4M72.8 46.7h.1M72.8 46.7v.2M72.8 47l.1 .3M72.8 46.7l.4 .2M72.8 46.7v.3"/>
<path d="M72.8 46.6l.4 .3M72.9 46.6h.1M72.9 46.6h1.3M72.9 46.6l.3 .2M72.9 45.1l-.4 .1M72.9 45.1v.1M72.9 46.5l-.1 .2M72.9 45.1h1.3M72.9 47.3h.1M72.9 47.6l.1 .1M72.9 47.3v.3M73 47.7l.5 .4 .6-.4"/>
<path d="M73.1 47.2l-.2 .1M73.2 47h.1M73.2 47l-.1 .2M73.2 47.1l-.2 .2h-.6M73.2 47.5l-.3 .1M73.2 47.5v.1M73.2 46.9v.6M73.2 46.8v.1M73.2 46.8l.4-.3 .3 .3M73.2 47.6l.3 .2 .4-.2M73.2 47.6l-.2 .1M73.2 46.5h-.3"/>
<path d="M73.2 45.4v1.1M73.2 46.5h.7M73.7 58.4l-1.6 2.1M73.9 47.6l.2 .1M73.9 46.5h.3M73.9 45.4v1.1M73.9 47.5v.1M73.9 46.8v.1M73.9 47.5h.1M73.9 47.5l.3 .1M73.9 47.1l.2 .2h.6M73.9 47l.1 .2"/>
<path d="M73.9 46.9v.6M73.9 47h.1M73.9 47v.1M73.9 47.1v.1M73.9 46.9v.1M73.9 47.2h.1M73.9 46.9h.1M74 47.2l.2 .1M74.1 47.7h.6M74.2 47.6l-.1 .1M74.2 47.3v.3M74.2 47.3h.1"/>
<path d="M74.2 47.3h.5M74.2 46.6l-.3 .2M74.2 45.1l.4 .1M74.2 45.1v.1M74.2 46.5v.2M74.2 46.6h.1M74.2 46.7l-.3 .2M74.2 46.7l.1 .3M74.2 46.6l-.3 .3M74.3 47l-.1 .3M74.3 46.7h-.1M74.3 46.7v.2"/>
<path d="M74.3 46.9v.1M74.3 46.9h.4M74.4 54.3a.8 .8 0 0 0 .1 1.1 .8 .8 0 0 0 1.1 0 .8 .8 0 0 0 0-1.1M74.5 45.4l.1 .2M74.6 45.6h.1M74.6 46.3l-.3 .4M74.6 45.6v.7M74.6 46.3h.1M74.6 49.2l-.4 .7 .5 .7M74.7 49.1l-.1 .1M74.7 54.1l-.3 .2M74.7 45.4v9.4l.3 .4 .4-.4v-9.4"/>
<path d="M74.7 43.5v.3M74.7 44.9v.3M74.7 53h.7M74.7 46.8l-.4 .1M74.9 43h.2M75.1 43.8l-1.1 1.1M75.2 43.1h.7M75.4 46.8l.3 .1M75.4 48.8h1.6l.5 .4 .2 .6v6.3l-.4 .9-.6 .2M75.4 48.8l1.6 .1 .5 .3 .2 .6v6.3l-.2 .7-.8 .4M75.4 52h.8l.2 .3M75.4 51.3h.8l.2 .3"/>
<path d="M75.4 51.9h.7l.3 .2M75.4 51.4h.8l.2 .2M75.4 43.5v.3M75.4 44.9v.3M75.4 50.9h.6M75.4 48.4h1.3M75.4 47.7h.8M75.4 47.3h.6M75.4 46.9h.3M75.4 46.3h.1M75.4 45.6h.1M75.4 54.1l.2 .2"/>
<path d="M75.4 49.1v.1M75.4 49.2l.4 .7-.4 .7M75.4 49.2h1.3M75.4 46.3l.3 .4M75.4 45.6v.7M75.5 45.4v.2M75.6 54.3h.4M75.7 46.9l.1 .1M75.7 45.4l-.3 .4h.8M75.7 46.7h.2M75.7 46.7v.2M75.8 47h.1"/>
<path d="M75.8 46.5v.5M75.8 45.1l-.4 .1M75.8 45.1v.1M75.9 43.8h.1M75.9 43.1l.3 .3M75.9 43.1v.7M75.9 44.9v.3M75.9 47l.1 .3M75.9 46.7l.4 .3M75.9 46.7v.3M75.9 42.6l.5 .2 .2 .5M75.9 43l.4 .3"/>
<path d="M75.9 43v.1M75.9 42.6v.4M75.9 45.4h.3M76 45.3h.1M76 46.2h.2M76 46.2h-.6l.4 .3M76 46.2l.1 .3M76 45.3l.2 .1M76 47.3h.1M76 45.1h-.2M76 45.1v.2M76 50.9l.5 .2 .2 .5"/>
<path d="M76 50.9v3.4M76 47.3l.1 .2M76.1 47.5l.1 .2M76.1 46.5h.1M76.1 46.5h-.3M76.1 46.5l-.2 .2M76.1 44.9l-.1 .2M76.1 46.5l.3 .4M76.2 46.2l.4 .2 .2 .5M76.2 46.2l-.1 .3M76.2 45.8v.4M76.2 45.4v.4"/>
<path d="M76.2 47.7l.5 .3M76.2 43.8h.1M76.2 43.4v.4M76.3 44.9v.1M76.3 45l-.3 .3M76.3 45l-.3 .1M76.3 45h.1M76.3 45l.1 .2M76.3 47h.1M76.3 47l-.3 .3M76.3 47v.1M76.3 43.3l-.1 .1"/>
<path d="M76.3 43.3v.5M76.3 43.3h.3M76.3 47.1l-.3 .2M76.3 47.1v.2M76.3 47.3v.1M76.3 47.3l-.2 .2M76.3 47.3h1.4M76.3 47.4v.1M76.3 47.5h.1M76.4 47.5h.1M76.4 53.6l-.2 .3h-.8M76.4 52.5l-1 .1"/>
<path d="M76.4 53.6h.3M76.4 51.6h.3M76.4 51.6v2M76.4 47.5l.3 .2M76.4 47.5l-.2 .2M76.4 45.2l-.2 .2M76.4 46.9l.1 .6 .3 .2v-.8M76.4 45.2h.4M76.4 46.9h.4M76.4 46.9l-.1 .1M76.4 44.9v.3M76.6 43.3v.5"/>
<path d="M76.7 48.4a1.42 1.42 0 0 1 1.4 1.4M76.7 49.2l.4 .2 .2 .4M76.7 48.4v.8M76.7 56.8v.4M76.7 48h.4M76.7 47.7h.4M76.7 47.7v.3M76.7 53.6l-.2 .5-.5 .2M76.7 51.6v2M76.8 45.2l-.2 .4-.4 .2M76.8 44.9v.3M77 44.9v2.8l.3-.3v-2.5"/>
<path d="M77.1 47.7v.3M77.1 43.3v.5M77.1 43.3h.4M77.2 57.2l-2.3 3.3M77.3 56.1l-.2 .5-.4 .2M77.3 56.1h.8M77.3 49.8h.8M77.3 49.8v6.3M77.4 46.4v1l-.3 .3M77.4 46.4h.3M77.5 45.7l-.1 .7M77.5 45.7l.1 .2"/>
<path d="M77.5 43.3v.5M77.5 43.3l.1 .1M77.5 57.2v.8l.5 .4 14.5-.1M77.5 45.6v.1M77.5 45.6l.1 .3M77.5 45.6l.4 .1M77.5 45.3h.6M77.5 45.3v.3M77.5 44.9v.4M77.6 43.4v.4M77.6 43.8h.1M77.6 45.9l1.1 .9"/>
<path d="M77.6 45.9l.1 .5M77.6 45.9h.1M77.7 46.4l.7 .6M77.7 47.3l-.2 .5-.4 .2M77.7 46.4v.9M77.7 45.9l1.6 1.7M77.8 42.6l-.5 .2-.2 .5M77.8 43l-.3 .3M77.8 43h12.3M77.8 42.6h12.5M77.8 42.6v.4M77.8 43l.1 .1"/>
<path d="M77.9 45.7l1.7 1.8M77.9 45.7l-.2 .2M77.9 44.9v.8M77.9 43.1l-.3 .3M77.9 43.1v.7M77.9 43.1h12.2M77.9 43.8h.1M78.1 56.1l-.6 1.2M78.1 49.8v6.3M78.1 45.3l1 .4 .5 1M78.1 44.9v.4M78.2 44.9l1.2 .6 .5 1.2"/>
<path d="M78.4 56.1l-.3 1.1-.6 .5M78.4 56.1h.8M78.4 47h.4M78.4 47v9.1M78.7 46.8v.1M78.7 46.8l-.3 .2M78.7 46.8l.1 .2M78.7 46.8h.1M78.7 46.9l.1 .1M78.8 46.8l.7 1.2M78.8 47h.1M78.8 47v9.1l-.2 1-1 1"/>
<path d="M78.8 47l.4 1.1M79 57.1l-1.1 1.2M79 57.1l.1 .7 .4 .6M79 57.1l.3 .1M79.1 56.7l-.1 .4M79.1 56.7l.3 .1M79.1 56.6v.1M79.1 56.6l.3 .2M79.2 56.1l-.1 .5M79.2 48.1l.3 1.7M79.2 48.1v8M79.2 58.4l-1.5 2.1"/>
<path d="M79.3 57.2l.1 .5 .7 .6h.3v-.8M79.3 47.6l.6 2.2M79.4 56.8l-.1 .4M79.4 56.8l.7 .3M79.4 56.8h.1M79.5 48l.4 1.5v5.3l-.5 2M79.5 48l-.3 .1M79.5 54.8l-.4 1.8M79.5 54.8h1.2M79.5 49.8h.4M79.5 49.8v5M79.6 47.5l.3 2.3"/>
<path d="M79.6 46.7h.3M79.6 47.5l-.3 .1M79.6 46.7v.8M79.6 43.8l-1.1 1.1 1.1 .6 .3 1.1M79.9 46.6l-.1 9.5a1.32 1.32 0 0 0 .3 2.1l12.8 .1M79.9 46.6h.8M79.9 46.6v.1M80 44.9l.5 .8 .2 .9M80.1 57.1l.3 .4M80.4 57.5h13.5M80.7 54.8l-.6 2.3M80.7 46.6v8.2"/>
<path d="M82 58.4l-1.5 2.1M84.1 43.8l-1.1 1.1M84.8 58.4l-1.5 2.1M87.6 58.4l-1.5 2.1M88.3 49.9l.2 .5 .5 .2M88.3 49.9h.4M88.3 45.8h.4M88.3 45.8v4.1M88.7 49.9l.3 .4M88.7 45.8l.1 .2M88.7 45.8v4.1M88.7 43.8l-1.1 1.1"/>
<path d="M88.8 48.6l.4 .3M88.8 48.6l-.1 1.3M88.8 47.5v1.1M88.8 47.5h.8M88.8 46v1.5M89 50.6h.4M89 50.3h.4M89 50.3v.3M89 45.1l-.5 .2-.2 .5M89 45.4l-.3 .4M89 45.4h1.1M89 45.1h1.1"/>
<path d="M89 45.4l.2 .2M89 45.1v.3M89.2 48.9h.1M89.2 48.9l-.2 1.4M89.2 45.6l-.4 .4M89.2 45.6v3.3M89.2 47.4l.1 1.5M89.2 47.4h.4M89.3 48.9l.1 1.4M89.4 50.3v.3M89.6 47.5v1.1M89.6 47.4l.2 .1"/>
<path d="M89.6 47.4v.1M89.6 48.6l-.3 .3M89.6 48.6l.2 1.3M89.8 49.9l-.4 .4M89.8 49.9h.3M89.8 47.5h.4M89.8 47.5v2.4M90 46.7l-.6 .2-.2 .5M90 47l-.4 .4M90 46.7h1M90 47l.1 .2M90 46.7v.3"/>
<path d="M90.1 47.2l-.3 .3M90.1 49.9l-.2 .5-.5 .2M90.1 47.2h.3M90.1 47.2v2.7M90.1 45.1v.3M90.1 44.9v.2M90.1 45.4l.2 .2h-1.1M90.3 44.9v.4M90.3 45.3v.7h-1.5M90.3 45.3h.7M90.4 58.4l-1.5 2.1M91 44.9v2.1h-1"/>
<path d="M91.1 49.1h2.1l-.2 .3h-1.6zM91.2 42.2l-1 .6-.2 .7M91.2 42.2h.1M91.3 42.2h.2M91.4 53l-1.6 2.2M91.4 42.2h-.2M91.5 42.2h.5M92 42.2h1.2M93.2 42.2h.1M93.2 43.8l-1.1 1.1M93.2 42.2l1 .6 .2 .7M93.3 44.9v2.1h1.1"/>
<path d="M93.3 46.7h1.1M93.3 45.3h.7M93.4 58l-1.7 2.5M94 47.2h.2M94 45.3v.7h.5M94 44.9v.4M94 42.6h.6M94.1 47.5h.4M94.2 45.4l-.2 .2h.5M94.2 45.4h.4M94.2 45.1v.3M94.2 45.1h.8"/>
<path d="M94.2 44.9v.2M94.2 49.9l.2 .5M94.2 47.2l.3 .1M94.2 49.9h.2M94.2 47.2v2.7M94.3 43h.3M94.3 43.1h.3M94.4 46.7h.1M94.4 47h.1M94.4 47l-.2 .2M94.4 46.7v.3M94.6 43l.5 .7h2.8v1.3"/>
<path d="M96.4 56.3l-.3 1.6-.9 1.4-1.4 .8-1.6 .4M96.4 56.3l.5 1.4M96.5 53.6l-2.5 3.5M96.6 49.5l-5.4 7.6M96.6 48.3l-.2 8M96.6 48.3l.3 .7M96.6 43.8v1.1h-57.8v-1M96.9 58.2l-.4 1.3-.8 1.2M96.9 57.7l-.4 1.6-.9 1.4-1.3 .9-1.6 .3M96.9 57.7v.1M96.9 49.4h.1M96.9 49v.4"/>
<path d="M96.9 57.8v.4M96.9 56.6v1.2M96.9 45l-2.4 3.5M97 49.4l-.1 7.2M97.1 43.8l.4 .1 .2 .4M97.1 43.7v.1M97.1 47.8l-.5 .5M97.1 47.8h.1M97.1 47.8l.3 .6M97.2 47.8l.4 .6M97.4 48.9l.1 .1M97.4 48.9l-.4 .5"/>
<path d="M97.4 58l-.4 1.4-.9 1.3M97.4 58l-.5 .2M97.4 58l-.1 2.7M97.4 48.9l-.5 .5M97.4 48.9h4.5M97.4 48.8l-.5 .2M97.4 48.4l-.5 .6M97.4 48.8v.1M97.4 48.4h.2M97.4 48.4v.4M97.4 57.4v.6M97.4 57.4l-.5 .4"/>
<path d="M97.4 56.2v1.2M97.4 56.2l-.5 .4M97.4 49l-.4 .4M97.5 49h-.1M97.5 49h.1M97.5 49l-.1 7.2M97.6 48.4v.5M97.6 48.9v.1M97.6 49l-.2 7.2M97.7 44.3h.2M97.7 44.3v.7M97.9 45h-2.8l-.5 .4-.2 6.6-.3 .7-.7 .3h-3.6v4.1h4.3l-.7 .9-1.2 .4"/>
<path d="M97.9 45h.1M98.9 48.7l-1.5 .1M98.9 48.7h9.9M98.9 48.7v.2M99.6 41.2l-1.7 2.5M100 45l-.2 1.1-.6 .9-.9 .6-1.1 .2M100 44.6l-2.2 3.1M100 42.7v2.3M100 45l.4 .6M100.3 43.5v1M100.3 43.5h7.5M100.3 42.4h.1"/>
<path d="M100.3 42.4l-.3 .3M100.3 42.4v1.1M100.3 44.5h.1M100.4 44.5l.5-.5v1.6M100.4 44.5v.6M100.4 45.6l-.3 1.1-.6 .9-.9 .6-1 .2M100.4 45.6h.5M100.4 45.1h4.2M100.4 45.1v.5M100.4 42.4v1.2l.4 .4M100.8 44l-.5 .5M100.8 44h4.1"/>
<path d="M100.9 45.6l-.6 1.9-1.4 1.2M101.1 50l.6 3.7M101.3 56.6l.4 .1M101.3 56.6l-.2 1.1 .5 .6M101.6 58.3l-1.9 1.8-2.4 .6M101.6 58.3h.1M101.7 50v3.7M101.7 58.3l.4 .1M101.7 56.7l-.2 .9 .6 .4M101.7 56.7h5.9M101.7 53.7l-.4 2.9M101.9 59.8a5.6 5.6 0 0 1-4.8 2.8"/>
<path d="M101.9 59.8h.4M102.1 58h.1M102.1 58l-.5 .3M102.1 58.4l-.7 1.4-1.1 1.1-1.4 .8-1.5 .2M102.1 58.4h.1M102.1 58h5.5M102.1 58l-.4 .3M102.2 58.5l.2-.1zM102.2 58.4a5.1 5.1 0 0 1-4.9 3.6M102.2 50l.1 3.6M102.3 53.6l-.6 .1M102.3 53.6l-.6 3.1"/>
<path d="M102.4 58.4h.1M102.4 58v.4M102.4 58.4h.4M102.4 58.4l-.5 1.4M102.4 50v5.9h6.6M102.4 58.1l-.2 .3M102.6 58l-.5 .4M102.8 55.1l-.4 .1M102.8 50v5.1M103.2 44v4.9M103.8 54.6h1.3M103.8 54.6l-1 .5"/>
<path d="M104 52.5l-.2 2.1M104 52.5h.4M104 50v2.5M104.4 52.5l.2 1.5 .5 .6M104.4 50v2.5M104.6 54.7l-.6 .5-1.6 .1M104.6 54.7v1.2M104.9 44l-.3 1.1M105.1 54.6l.5 .1M105.6 50v4.7h-1M106.5 50v5.9M107.2 50v5.9"/>
<path d="M107.6 56.7v1.3M107.7 50l-.1 6.7M107.8 43.5l-1.6 1.2-1.6 .4M107.8 43.5l-2.9 .5M108.8 48.7l-.1 .2M108.8 43.3h.5l-.3 13.3M109 56.6a1.4 1.4 0 0 1-1.4 1.4M109 56.6l-1.4 .1M109.2 45.4l-.4 .9M213.1 56.7h49.4l4.2 4.2v66.9h-57.8v-66.9zM350.6 56.7h49.4l4.2 4.2v66.9h-57.8v-66.9zM440.8 45.2h139.4"/>
<path d="M513.5 40.6l.3-.2a1.69 1.69 0 0 1 0 2.5 1.77 1.77 0 0 1-.3-2.3zM513.5 46.9l.3-.2a1.69 1.69 0 0 1 0 2.5 1.77 1.77 0 0 1-.3-2.3zM34.4 60.4l1.5 1.2 1.7 .5 10.6 .1M38.1 60.7h.1M38.1 60.7l-.1 1.2M38.1 60.7v1.3M38.1 62h59.2M38.1 60.7h1.2M38.1 62h.2v.6M38.3 62.6h58.8M39.3 60.7l1.5 .9 1.8 .3M39.7 60.7h-.4"/>
<path d="M39.7 60.7h.1M39.7 60.7l1.3 .9 1.6 .3M42.7 61.9h-.1M43.1 60.5h7.1v1.4M43.1 60.5l-.4 1.4M48.1 62.2l.3-.2 .3 .2M48.4 62.2h.1M48.7 62.2h18.7M50.2 61.9h-12.2M50.2 61.9h2.1M50.2 60.5h35M67.4 62.2l.3-.2 .3 .2"/>
<path d="M67.6 62.2h.1M67.9 62.2h18.8M85.2 61.9h-2.1M85.2 61.9h12.1M86.7 62.2l.2-.2 .3 .2M86.9 62.2h.1M92.2 60.5h-7v1.4M92.2 60.5l.5 1.4M92.7 61.9h.1M95.7 60.7l-1.3 .9-1.7 .3M95.7 60.7h.4M95.7 60.7h.1"/>
<path d="M96.1 60.7l-1.5 .9-1.9 .3M97.1 62v.6M97.1 62h.1M97.3 60.7h-1.2M97.3 60.7v1.3M97.3 60.7h.1M97.3 60.7l.1 1.2M97.4 61.9h-.1M100.6 60.8l-1 .7-1.9 .6-10.5 .1M508.8 72.3l-2.7-.2-6.1 18.6M543.3 72.5l-33.9-2-6.6 20.3-4-.2-6.1 18.9M543.3 72.5l-6.6 20.4 3.9 .2"/>
<path d="M543.3 72.5l.7 1.9M544 74.4l-6.1 18.5M544 74.4l4 .3M548 74.7l-6.7 20.2-.7-1.8M548 74.7l1.5 4.2-14.5 46.6M549 77.4h.1M549 77.4l2.5 3M27.2 93.1v16.3M43 84.2a4.2 4.2 0 0 0-3.7 2.3M92.4 84.2a4.2 4.2 0 0 1 3.7 2.3M105.6 93.1v17.9M540.6 93.1l-6.1 18.9"/>
<path d="M551.5 80.4l-14.1 45.2M551.5 80.4l.2 .6-14.1 45.2M2 112.1h9.6M26.2 102.9h2l-1 6.5zM26.3 114.1h1.2M28.2 111.8h-1.9v4.7h1.9M104.6 104.5h2l-1 6.5zM104.6 115.7h1.2M106.5 113.4h-1.9v4.7h1.9M492.7 109.5l2.6 6.9M492.7 109.5l41.8 2.5M493.9 112.7l-3.1 10.1"/>
<path d="M534.5 112l2.6 6.9-41.9-2.6-2 6.7M580.2 112.1h9.5M27.5 140l6.4 9.2M35.1 122.6l-7.6 10.9M35.5 133l1.9-.1 .5 .5v6.6l-.2 .5-.5 .2h-1.5l-.4-.7a5.1 5.1 0 0 0 .6-5.4l-.6-.8zM36.5 131.2h-4.4a5.6 5.6 0 0 0-5.6 5.6 5.6 5.6 0 0 0 5.6 5.6h2.5l.3 .3-1.3 7.9M97.6 133l1.8-.2 .5 .2 .2 .5a5.1 5.1 0 0 0-.6 5.4l.6 .9-.2 .7-1.7 .2-.5-.2-.2-.5-.1-6.4zM98.9 131.2h4.3a5.6 5.6 0 0 1 5.6 5.6 5.6 5.6 0 0 1-5.6 5.6h-2.4l-.3 .3 1.2 7.6 .2 .4 .5 .1M100.3 122.6l7.5 10.9M100.9 131.2l-.5-.6-.4-44.3a2.1 2.1 0 0 0-2.1-2.1h-60.4a2.1 2.1 0 0 0-2.1 2.1l-.4 44.3-.5 .6M107.8 140l-6.2 8.9M490.8 122.8l.2 .6 46.6 2.8"/>
<path d="M490.8 122.8l46.6 2.8M537.4 125.6l.2 .6M27.7 151.3l-1 .4-.4 1M33.8 149.7l-.3 .4-.5 .1v1.1h-5.7l-.8 .4-.4 1 .1 3.6 2 3.7v4h4.3M33.9 149.2v.1M71.8 153l.3 .2M71.8 152.7l.6 .4M71.9 152.6l.5 .4M72 152.5l.4 .4M72 152.5l.4 .3M72.3 153.1l-.6-.3 .5 .4M72.4 152.7a.36 .36 0 0 0-.4-.2 .36 .36 0 0 0-.3 .4 .36 .36 0 0 0 .4 .3"/>
<path d="M72.4 157.2l-.5-.2 .5 .3v2.2M72.4 157.7h2.3M72.4 159.5l3.3 3.2M72.7 151.8l1.4-.2 .5 .5v5.6M72.7 151.8l-.2 .5v5.4M72.7 151.7l-1.2 .1 .2 3.7M73.2 155.3v2.2l-.2 .2M73.9 160l3.5 3.5M73.9 155.3v2.2l.2 .2M73.9 147.3h-35.4M74.2 160l.5-.5h.7l3.4 3.3M74.5 146.5l5.6-2.2 5.2-1.1 .4 .2-.9 .2 .2 .7 8.2-.2 6.2 .2 1.2 1.4 .6 1.8"/>
<path d="M74.5 146.5l-3.1 4 .2 4.9 1.1 5.6 .4 12.2 1.7 2.8M74.7 152.8l.2 .4 .4-.1M74.7 159.5v-2.2l.3-.4 .4 .4v2.2M74.7 152.8l.5-.3-.5 .4M74.9 160l3.4 3.3M75.1 152.5l-.4 .2M75.2 153.2h-.1M75.3 152.7l-.6 .3M75.4 153l-.5 .2M75.4 152.8l-.7 .2 .6-.3-.3-.2-.3 .3M75.4 157.2l-.5-.3-.2 .5M75.4 152.9l-.6 .2"/>
<path d="M75.4 157.7l3.2 .1 .2 1.2M75.4 157.7v-5.4l.3-.5 .5-.3 1 .1 .1 .3 .1 5.6 .3 .2M75.7 151.7h-1.3M76.8 151.5l-.4 .4-.2 5.8M76.9 160l3 3M77.7 159.7l2.2 2.3M77.7 158.8l2.2 2.2M77.8 157.9l1 1M78.1 157.7l-.4 .4-.2 1.8-5 .1M78.8 159l.4 .4h9.5M78.8 159h10M79.3 159.4l.6 .5"/>
<path d="M79.5 159.4l.4 .3v4.4l.3 .5 .5 .2M85.2 143.2v-50.6a2.1 2.1 0 0 0-2.1-2.1h-30.8a2.1 2.1 0 0 0-2.1 2.1v51.9a2.1 2.1 0 0 0 2.1 2.1h22.2M85.2 143.5v.8M89.2 153.6l.4 .3 .2 10.5 .3 .4M91 154.4v-.8h-1.8l-.4 .3-.1 10.5-.4 .4M94.9 144.1v1.7l.3 .5 2.9 .3 .7 .5 .4 .8a41.7 41.7 0 0 1 1 12.5M95.1 153.6l-.3 .3-.2 10.5-.4 .4M95.2 153.6l.3 .3 .2 10.5 .3 .4M95.2 153.6h-1.9v.7M96.6 146.5v12.5l-1 .1 .3 .3h3.6l.4 .7v4.7h2.3l-.1-1-1.5-.2M97.3 154.3h1M98.5 159.6l1.4 1.4"/>
<path d="M98.8 159.4l-.4 .3v4.4l-.2 .5-.5 .2M99.3 159.4l.4 .4M101.6 149.7l.3 .4 .5 .1v13.8M101.6 148.9l-.1 .4M101.6 148.9h.1M102.4 155.3l1.3 .2M103.3 159.4l1 1M103.4 158.5l1 1M103.5 157.5l1 1M103.5 156.6l1 1M103.6 155.7l1 1M103.7 154.8l.9 .9"/>
<path d="M103.8 153.9l1.8 1.8M103.9 153l1.2 1.2M104 152.1l-1.2 11.6-.2 .6-.9 .5 2 2M104 152.1l.4 .1 1.2 3.2v.4l-1-.1M104 152.1l.5 .5M104.6 155.7l2.6 .3v-4.7a1.67 1.67 0 0 1 1.6 .5l.3 .9v3.3l-2 4-.1 4M104.6 155.7v4.2l1.5 4.1M104.6 155.7l-.6 10.4a2.13 2.13 0 0 1-2.1 2h-19.5l-.2 .4-.2 8.2-.2 .5-.5 .2M107.8 151.3l.8 .2 .6 .8 .1 3.5-.3 .8-1.8 3.4v4h-3.1M31.2 164a3.9 3.9 0 0 0 .8 3.5l1.5 .6h19.3l.4 .4M31.3 165a1.42 1.42 0 0 0 1.4 1.4h40.2M32.5 164l-.1 1.9 .6 .5"/>
<path d="M52.4 166.4l.5 .2 .2 .5 .3 9.9 .6 .4 2-.1 .5-.5 .3-1.8M56.1 175h18M56.6 175.9h.4M57.2 175v.3M57.5 175v.3M61.5 175v.3M62.5 175v.3M64 175v.3M72.7 160.8l2 1.9M72.8 161.8l.9 .9M72.8 162.7h-39.7l-.4 .2-.2 1.1M72.8 162.7h3.7v.8"/>
<path d="M72.8 163.5h1.9M72.8 164h1.9M72.8 164.5h1.9M72.8 164.7h1.9M72.8 164.8h1.9M72.8 164.9h1.9M72.9 165.4h1.8M72.9 165.9h1.8M72.9 162.7l-.1 .1M74.2 162.7l.5 .5M74.4 175.3h-17.5v.4l.4 .3h21.1l.3-.1M74.5 175.5h3.7"/>
<path d="M74.7 163.2v4.9M74.7 163.2h.7M74.9 168.6h.2M75.4 165.9h2.8M75.4 165.4h2.3M75.4 164.9h1.9M75.4 164.8h2.2M75.4 164.7h2.2M75.4 164.5h1.9M75.4 164h2.3M75.4 163.2v4.9M75.8 162.7l-.4 .5"/>
<path d="M77.3 164.9l.4 .5M77.3 164.5l.3 .2M77.6 164.7v.1M77.6 164.8l-.3 .1M77.7 164l-.4 .5M77.7 164l1.1 1.6M77.7 163.5v.5M77.7 165.4v.5M77.7 165.9v1.6M77.7 167.5h-2.1l1.7 .6h.9M77.7 167.5l.5 .6M78.1 163.5l.9-.8v3.6"/>
<path d="M78.2 168.1l.1 7.8h2.7M78.2 168.2h2.8v9.2M78.2 173.1h.8M78.2 165.9l.4 .4h.4M78.2 165.9l.8 .8v6.9h-.8M78.3 175.8l-.4 .2M78.5 163.1h.5M78.6 163.1l-.4 .4h-2.8M78.8 165.6l.2 .2M78.8 165.5v.1M78.8 166.5l-1.1 .5M78.9 165.8h.1"/>
<path d="M79 172.5l1.8 2.8v.6M79 166l3.2 3.2M79 165l3.2 3.3M79 164l4 4.1M79 163l.9 1M79 166.3v1.9M79 163.6l-.2 .2 .2 .4M79 165.3l-.2 .2M79 167l1.2 1.2M79 168.1l.2 .1M79.1 175.9l.4 1.3 1.8 .2M80.1 168.2v4.3h.9"/>
<path d="M80.1 175.9v.8l.4 .7M80.7 164.8h17M80.7 164.8l3.3 3.3M81 177l.3 .4M81 176l.9 1M81 175l1.1 1.1M81 174l1.1 1.1M81 173l1.1 1.1M81 172l1.1 1.2M81 171l1.1 1.2M81 170l1.1 1.2M81 169l1.2 1.2"/>
<path d="M81.7 164.8l3.3 3.3M82.7 164.8l3.3 3.3M83.7 164.8l3.3 3.3M84.7 164.8l3.3 3.3M85.7 164.8l3.3 3.3M86.7 164.8l3.3 3.3M87.7 164.8l3.3 3.3M88.7 164.8l3.3 3.3M89.7 164.8l3.3 3.3M90.7 164.8l3.3 3.3M91.7 164.8l3.3 3.3M92.7 164.8l3.3 3.3"/>
<path d="M93.7 164.8l3.3 3.3M94.7 164.8l3.3 3.3M95.7 164.8l3.3 3.3M96.7 164.8l3.3 3.3M97.7 164.8l3.3 3.3M98.3 164.3l3.7 3.8M98.4 163.5l4.3 4.3M98.4 162.5l1.5 1.5M98.4 161.5l1.5 1.5M98.4 160.5l1.5 1.5M99.9 164.4l.3 .4M99.9 160.4h.3"/>
<path d="M99.9 164.1l.7 .5M99.9 160.6h.7v.3M100.2 160.4l.6 .5M100.5 160.6h.1M100.6 160.9l.3 .3-.3 .4 .1 .3a.31 .31 0 0 1 .3 .3 .31 .31 0 0 1-.4 .3M100.6 162.5v.4l.7 .3-.7 .4M100.6 160.9h.2M100.6 163.6h.1M100.6 164.6l.7-.2 .2 .4M100.6 164.6v.2M100.6 162.4h.2M100.7 164.8l2.7 2.6"/>
<path d="M100.8 162.4l.5 1.6h1.4M100.8 160.9v1.5M102.4 164.5l1.6 1.6M102.4 163h.5l1.2 1.2M102.8 163.9l1.3 1.2M103 162.1l1.2 1.2M103.1 161.2l1.1 1.1M103.2 160.3l1.1 1.1M104.2 163h1.5M107 161.2l-1.4 1.5M250.6 178a5.9 5.9 0 0 0-5.3 3.2M285.9 175.2v7.3"/>
<path d="M321.2 178a5.9 5.9 0 0 1 5.2 3.2M434.2 178a3 3 0 0 0-2.9 2.9l-1.2 63.3-.6 .9M534.8 173.1l-21.1 19.1M534.8 173.1h.1M535.3 173.1h-.5M535.3 173.1l-21.2 19M535.3 173.1l22 6.5M536 172.9l22 6.5 .6 .7M536 172.9l-.7 .2M536 172.9l-1.2 .2M557.3 179.6l1 1.1M557.3 179.6l-21.1 19.1"/>
<path d="M558 179.4l-.7 .2M285.9 184.7v2.3M285.9 189.2v7.3M285.9 198.8v2.2M413.1 187l-2.1 80M503.2 199.8v.7M503.6 198.6l-.4 .9 .2 1.2M504.5 198.4h.1M504.5 198.4l-.9 .2M504.6 198.4l.4 .1M504.7 197.7l-1.1 .9M504.9 199h-.8l-.5 .3-.3 .6 .2 .8"/>
<path d="M504.9 199l24.3 7.3M505 198.5l-.1 .5M505 198.5l24.3 7.2M506 197.6l-.8-.1-.5 .2M506 197.6l-1 .9M506 197.6l24.4 7.2M506.1 197.5h-.8l-.6 .2M506.1 197.5l-.1 .1M506.1 197.5l24.3 7.3M506.4 196.9l-.7 .1-.4 .5M506.4 196.9h.1M506.4 196.9l.4 .1"/>
<path d="M506.8 197.5h-1M506.8 197.5l-.2 .2M506.8 197.5l24.2 7.1M506.8 197l24.2 7.2M506.9 197.2l-.8-.1-.6 .3M506.9 197.2l-.1 .3M506.9 197.2l24.2 7.2M506.9 196.7h-1.2l-.6 .8M506.9 196.7l-.1 .3M506.9 196.7l24.2 7.2M507 195.5l.7-.3 .8 .1h-.9zM507.2 196.5l-.3 .2"/>
<path d="M507.2 196.5l24.1 7.2M507.3 196.5l-.9-.1-.7 .3 .6-.3 .9 .1M507.3 196.5h-.1M507.3 196.5l24.1 7.1M507.6 195.8h.1M507.6 195.8l-.7 .1-.4 .5M507.6 195.8l.5 .1M508.1 196.3l-1.1 .1M508.1 196.3l-.4 .3M508.1 196.3l24.1 7.2M508.1 195.9l24.2 7.2M508.1 196h-.8l-.6 .4"/>
<path d="M508.1 196v.3M508.1 196l24.2 7.2M508.2 195.6h-1.2l-.6 .8M508.2 195.6l-.1 .3M508.2 195.6l24.1 7.2M508.3 195.2h-.5M508.4 195.4l-.2 .2M508.4 195.4l24.3 7.1M508.4 195l-.6 .2M510.4 193.3l-2.2 2M510.7 193.1l-.3 .2M511 192.9l-.6 .4"/>
<path d="M511 192.9l-.3 .2M511 192.9h.1M511.7 193.1h-1M511.7 193.1l-2.7 2.4M512 192.8l-1 .1M512 192.8l-.3 .3M512 192.8h.1M513.7 192.2l-1.7 .6M514.1 192.1l-1.1 .7-1.3 .3M514.1 192.1l-.4 .1M536.2 198.7l-.6 .8 .3 .7M536.2 198.7l1 1"/>
<path d="M537.2 199.7l-.3 .6M537.2 199.7l.3 1.1M558.3 180.7l-21.1 19M558.3 180.7l1.9 5.6M558.6 180.1l-.3 .6M558.6 180.1l1.9 5.6M560.2 186.3l.4 .4M560.2 186.3l-20.4 18.5M560.5 185.7l-.3 .6M560.5 185.7l.8 .8M560.6 186.7l-17.5 15.7M560.6 186.7l.9 .3"/>
<path d="M561.3 186.5l-.7 .2M561.3 186.5l.7 .2M561.5 187l.4 .4M561.5 187l-15.4 13.8M561.9 187.4l-15.4 13.8M561.9 187.4l.6 1.8M562 186.7l-.5 .3M562 186.7l.3 .3M562.3 187l-.4 .4M562.3 187l.4 1.2M562.5 189.4l-15.1 13.5M562.5 189.4h.1"/>
<path d="M562.5 189.2v.2M562.5 189.2l-15.2 13.6M562.7 188.2l-.2 1M562.7 188.2v.6l-.2 .6M7.2 210.8h4.4M29.3 206.8v12.6M29.3 206.8l.3 1.1h3.4M29.3 219.4h3M29.3 206.8h3M29.4 205.8h-1.7a1.4 1.4 0 0 0-1.4 1.4l-.2 13.3h6.3M30.8 217.2l.5 .5 1.7 .1v1.3h-.7v.3M30.8 207.9v10.5"/>
<path d="M32 213.8h20.8M32.3 219.4a5.9 5.9 0 0 0 6 6h58.8a5.9 5.9 0 0 0 5.9-6M32.3 206.8a5.9 5.9 0 0 1 6-5.9h58.8a5.9 5.9 0 0 1 5.9 5.9M32.3 206.8v.4h.7v1.3h-1.7l-.5 .5M32.4 205.8h-2.6a1.4 1.4 0 0 0-1.4 1.4l-.2 13.3M33 218.4h-3.4l-.3 1M52.8 213.8l.2 .1zM52.9 212.4h-20.9M53.2 212.4v.4M53.2 213.5v.3M54.8 214v1.9l2.1-.1 .5 .6M55.2 207.1h2v8.7h-2"/>
<path d="M55.2 207v1.9h-.8v5.1h.8v1.9M55.2 215h2M55.2 207.9h2M56.4 213.9l.1 1.1M56.4 209v4.9M56.4 213.9l.2 1.1M56.4 213.9v.3M56.4 214h.8l.1 .9 .7 1.1M56.4 208.7v.3M56.4 214.2l.2 .8M56.4 214.2h.8M56.4 208.7h.8"/>
<path d="M56.5 207.9l-.1 1.1M56.6 207.9l-.2 1.1M56.6 207.9l-.2 .8M56.8 216.3l.3 .4M56.8 206.6h.1M56.8 206.6v.4M56.8 215.9v.4M56.9 215.9l.5 .5M57 216.8l.8-.8h20.4l.6 .6a3.8 3.8 0 0 1-3.5 1.9h-15.2a3.3 3.3 0 0 1-3.2-1.6zM57 207.1v.8M57 215v.8M57.1 206.2l-.3 .4"/>
<path d="M57.2 209.4h.1M57.2 213.5h.1M57.4 206.5l-.5 .5M57.4 206.5l-.5 .6-2.1-.1v1.9M57.8 216l2.3 .1M58 206.9l-.7 1.1-.1 .9h-.8M58.5 207.8l1.2-.5 16.4 .1 .7 .4 .4 .7v5.9l-.7 1-.9 .2-16.3-.1-1-.7-.2-.9v-4.9zM59.1 208.1l1.2-.6h14.8a1.42 1.42 0 0 1 1.4 1.5v4.9a1.42 1.42 0 0 1-1.4 1.5h-14.8a1.42 1.42 0 0 1-1.5-1.5v-4.9zM59.7 206.9a2.06 2.06 0 0 0-2 2.1v4.9a2.06 2.06 0 0 0 2 2.1M60.1 216v1.3h2.4v-1.3M60.1 217.2h2.4M60.1 204.4a3.3 3.3 0 0 0-3.2 1.6l.9 .9h20.4"/>
<path d="M61.5 206.7l-3.7 .1M61.5 206.9v-1.3h2.5v1.3M61.5 205.7h2.5M62.5 216.1h7.4M64 206.7h14l.8 1M66.7 218.5v.1M68.7 218.5v.1M69.9 216v1.3h2.5v-1.3M69.9 217.2h2.5M75.3 204.4a6.7 6.7 0 0 1 3.8 2l.7 .2-.5 .1-.4 .4M75.3 204.4h-15.2a6.1 6.1 0 0 0-3.3 1.3l-.7 .2 .5 .2 .2 .5M75.3 204.4a3.8 3.8 0 0 1 3.5 1.9l-.6 .6"/>
<path d="M75.6 206.9a2.06 2.06 0 0 1 2.1 2.1v4.9a2.06 2.06 0 0 1-2.1 2.1 2.06 2.06 0 0 0 2.1-2.1v-4.9a2.06 2.06 0 0 0-2.1-2.1zM77.3 206.9l.6 .7 .3 1.4M78.2 213.9l-.2 .9-.7 1.2M78.2 215.1h1.9M78.2 214.3h1.9M78.2 213.4h.8M78.2 213.3h.8M78.2 209.6h.8M78.2 209.4h.8M78.2 208.6h1.9M78.2 207.8h1.9M78.2 207.3v8.3"/>
<path d="M78.2 206.9l.6 .9M78.3 206.9l.5 .9 1.7-.1v1.9M78.3 216l-5.9 .1M78.3 207.8v.8M78.3 214.3v.8M78.6 206.6l.3 .5M78.8 215.1l-.6 .9M78.8 215.2l-.5 .9M78.9 215.2v.5M78.9 215.7l.4 .5 .5 .1-.7 .2a6.7 6.7 0 0 1-3.8 2h-1.3v.4h-1.1v-.4h-10.5v.4h-1v-.4a5.2 5.2 0 0 1-4.5-1.3l-.8-.2 .5-.2 .2-.5M78.9 215.7l-.3 .6M78.9 207.1v.6"/>
<path d="M79 208.6v5.7M80.1 207.7v1.9h.9v3.7h-.9v1.9M80.5 213.3v1.9l-1.7-.1-.5 .9M82.2 213.5v.3M82.2 212.4v.4M82.4 212.4h.2zM82.5 212.4h.1M82.6 212.4h20.8M102.4 207.2v1.3M102.4 217.8v1.3M102.4 218.4h3.3l.4 1M102.9 205.8h2.6a1.4 1.4 0 0 1 1.4 1.4l.3 13.3"/>
<path d="M103 206.8v.4h-.7v1.3h1.7l.6 .5M103 219.4h3.1M103 206.8h3.1M103.4 213.8l-21 .1M104.6 217.2l-.6 .5-1.7 .1v1.3h.7v.3M104.6 207.9v10.5M106 205.8h1.6a1.4 1.4 0 0 1 1.4 1.4l.3 13.3h-6.4M106.1 206.8l-.4 1.1h-3.3M106.1 206.8v12.6M285.9 203.3v7.3M285.9 212.9v2.2M285.9 217.4v7.3"/>
<path d="M499.9 204.4l1.5 4.4M500 204.1l-.1 .3M500.1 204.3l-.2 .1M500.1 204.3l.8 .2M500.2 204.1l-.1 .2M500.2 204.1h-.2M500.2 204.1l.8 .2M500.8 205.6h-.1l.7 2.3M500.9 204.5l.1 .4M501 204.3l-.1 .2M501 204.9l-.5-.1 .3 .8M501 204.9l.2 .6"/>
<path d="M501.1 204.3h-.1M501.1 204.3l.1 .2M501.2 205.5l-.4 .1M501.2 204.5h-.3M501.2 204.5l.2 .3M501.4 204.8l-.4 .1M501.4 204.8l.1 .3-.3 .4M501.4 207.9h.2M501.4 208.8l.3 .3M501.4 208.8l.3 .2M501.5 204.7l.7 .2M501.6 207.9l.3 .9"/>
<path d="M501.7 209v.1M501.7 209l.8 .3M501.7 209.1l.9 .2M501.8 204.1l-.6 .4M501.8 204.5l.2 .1M501.8 203.6l.2 .1M501.9 203.8v.3M501.9 204.1l.5 .5M501.9 208.8l.5 .1M501.9 203.8h.1M501.9 207.8l.4 .8M501.9 207.8l-.3 .1"/>
<path d="M502 203.7h.1M502 203.7l-.9 .6M502 203.7l-.1 .1M502 204.6l.2 .3M502.1 203.6h-.3M502.1 204.3l-.7 .5M502.1 203.6h.1M502.2 204.5l-.2 .1M502.3 207.5l.3 .8-.3 .3M502.3 207.5l-.3-.1-.6 .5M502.3 207.5l-.4 .3M502.3 204.6h.1"/>
<path d="M502.3 208.6l-.4 .2M502.4 204.6v.2M502.4 208.9l.1 .4M502.4 204.6l1.4 .4M502.4 204.8l-.2 .1M502.5 207.9l.7 .3M502.5 203.2h.1M502.5 209.3h.1M502.5 204.7l-.1 .1M502.6 209.3h.1M502.6 208.3l.8 .2M502.7 208.9h-.3"/>
<path d="M502.7 208.9l.1 .3M502.8 209.3h.1M502.8 209.3h-.2M502.8 209.2l-.3 .1M502.8 209.2v.1M502.9 204l-1 .1M502.9 204l6.3 1.8M503 203.7h-1M503 203.7l-.1 .3M503 203.7l6.2 1.8M503.1 203.6l-1.1 .1M503.1 203.6l-.1 .1"/>
<path d="M503.1 203.6l6.3 1.8M503.2 200.5l.1 .1M503.2 200.5l.1 .4M503.2 206.3l.3 .8M503.2 206.3l.3 .1M503.2 203.4l-1.1 .2M503.2 203.4l6.3 1.9M503.2 208.5l-.5 .4M503.2 208.2l.2 .3M503.3 200.6h.1M503.3 200.3v.3M503.3 200.6l.1 .3"/>
<path d="M503.4 200.7l.1 .1M503.4 200.7v.1M503.4 200.8h.1M503.5 200.7v.1M503.5 207.1l.2 .1M503.5 207.1l-.3 .3M503.5 208l.2 .6M503.5 208l-.3 .2M503.5 200.6h.1M503.5 200.6v.2M503.5 206.4l.2 .5M503.5 208.9l.1 .3"/>
<path d="M503.6 200.7h.1M503.6 200.7l-3.6 3.4M503.6 209.2l1.4 .9M503.6 209.2h.1M503.6 209.2l1.3 .8M503.6 200.6v.1M503.6 207l.1 .2M503.6 207l.4 .1M503.7 208.3l.2 .2M503.7 208.6l-.9 .7M503.7 208.6h.1M503.7 208.7h.1"/>
<path d="M503.7 200.7h-.1M503.7 200.7l-3.5 3.4M503.7 200.7l1 .3M503.7 208.6v.1M503.7 208.7l.1 .2M503.7 208.7l-.2 .2M503.7 207.2l.4 .2M503.7 207.2l-1.3 .5M503.8 208.7h-.1M503.8 205l-.2-.5 1 .3 .2 .5 5.7 1.7M503.8 208.9l.8 .2M503.8 208.9l-.2 .3"/>
<path d="M503.8 206.7l-.2 .3M503.8 206.7l.3 .1M503.8 208.6l1 .3M503.8 208.6v.1M503.9 200.1l-.4 .1v.4M503.9 200.1l-.2 .6M503.9 200.1l.9 .3M504 207.1l.1 .3M504.1 207.4l-.6 .6M504.1 206.8l-.1 .3M504.2 204.7l-.4 .3M504.6 209.1l.2 .5"/>
<path d="M504.7 205l-1.5 1.3M504.7 201h.2M504.7 201l-2.9 2.6M504.8 205.2l-1.3 1.2M504.8 208.9l-.2 .2M504.8 200.4l-.1 .6M504.9 201h.1M504.9 210l.1 .1M504.9 210l6.3 1.9M504.9 200.4l.1 .5M504.9 200.4h-.1M505 200.9l-2.9 2.7"/>
<path d="M505 210.1l6.3 1.8M505 200.9h-.1M505 209.4h.1M505 209.4l.7 .2M505.1 209.3l3.6 1M505.2 205.5l-1.4 1.2M505.6 205.6l-1.5 1.2M505.8 209.2l-.2 .2 .2 .5-1-.3M505.8 209.2l3 .9M506.1 200.8l-2.9 2.6M506.1 200.8l-1.1 .1M506.1 200.8l6.3 1.8"/>
<path d="M506.2 205.7v.3l-2.8 2.5M506.2 200.2l-.8-.1-.5 .3M506.2 200.2l-.1 .6M506.2 200.2l6.3 1.9M506.2 206l.2 .2M506.3 205.8l.3 .4M506.6 206.2l-2.8 2.4M506.6 206.2h.9M507.3 206.1l.2 .1M507.4 206.5l.2 .6M507.4 206.5l1 .3-2.6 2.4M507.4 206.5l-2.6 2.4"/>
<path d="M507.6 206.2h-.1M507.6 207.1l.4 .1M507.6 207.1l-2.8 2.5M508.7 210.3l.1 .5M508.8 210.1l-.1 .2M509.1 210.6h.1M509.1 210.6l.7 .2M509.1 210.6l-.3 .2M509.2 205.8l1.5 1.1M509.2 210.5l2.8 .8M509.2 205.5v.3M509.2 205.5l1.7 1.2"/>
<path d="M509.4 205.4l1.6 1.2M509.4 205.4l-.2 .1M509.5 205.3l1.8 1.3M509.9 210.4l-.2 .2 .2 .5-1.1-.3M509.9 210.4l2.4 .7-.3 .2M510.7 206.9h.3M510.7 206.9l-.2 .1M510.8 207.7l.2 .4M510.8 207.7v.1M510.8 207.5v.2M510.8 207.8l.7 .2M510.9 207h-.4"/>
<path d="M510.9 207.5v.1M510.9 207.5h-.1M510.9 208.1h.1M510.9 206.7l-.2 .2M510.9 206.7l.1 .2M510.9 207.6l-.1 .2M510.9 207.6l.7 .2M511 206.9l-.1 .1M511 208.1l.3 .1 .5 .9 .5 1.7h-.1M511 208.1l-2.2 2M511 206.6v.3M511 206.6l-.1 .1"/>
<path d="M511.1 206.8h.1M511.1 206.8l-.2 .2M511.1 206.8l.2 .2M511.2 211.9h.1M511.3 206.6l.4 .3M511.4 208.5l-2.3 2.1M511.4 206.8l-.6 .7M511.4 206.8l.3 .1M511.4 206.8l-.5 .7M511.5 208l.3 .2M511.5 208.9l-1.6 1.5M511.6 207.8l.4 .4"/>
<path d="M511.6 207.8l-.1 .2M511.8 208.2l1.2 3.7M511.9 210.4l.3 .4M511.9 210.4l.3 .1M512 208.2h-.2M512 208.2l1.2 3.7M512 211.3h.1M512 211.3v.1M512 211.4l.2 .5M512.1 210.2l-.2 .2M512.1 211.8l-.9 .1M512.1 211.8l.1 .1"/>
<path d="M512.2 210.8l.2 .8-.4-.2M512.2 211.9l.7 .2M512.2 210.6v.2M512.2 211.9h-.9M512.2 210.5v.1M512.4 202.6l-2.9 2.7M512.4 202.6l1.8 1.3M512.5 202.1l1.1 .5 1 1M512.5 202.1l-.1 .5M513 211.9l-.1 .2M513.2 212.1h-.3M513.2 211.9v.2"/>
<path d="M513.2 211.9h-.2M514.1 211.3l2.8 .8M514.2 203.9l.4 .3M514.2 203.9l-2.9 2.7M514.2 211.2l2.6 .8M514.6 204.2l-2.9 2.7M514.6 204.2l.7 .2M514.6 203.6l.1 .1M514.6 203.6l-.4 .3M514.7 203.7l-.1 .5M514.7 203.7l.7 .2M515.3 204.4l.4 .4"/>
<path d="M515.3 204.4l-3.7 3.4M515.4 203.9l.8 .8M515.4 203.9l-.1 .5M515.7 204.8l.7 2.1M515.7 204.8l-3.7 3.4M515.9 207.9l.1 .3M516 208.2l.2 .3 .3-.1M516 209.5l1.3 3.7M516 209.5h.1M516 209.5l-2.8 2.4M516 209.4v.1M516 209.2v.3"/>
<path d="M516 209.7l-2.8 2.4M516.1 207.1l.4 .4M516.1 207.1l-.2 .8M516.1 209.3l-.1 .1M516.1 209.3l.7 .2M516.2 209.1l-.1 .2M516.2 209.1l-.2 .1M516.2 209.1l.7 .2M516.2 204.7l-.5 .1M516.2 204.7l.7 2M516.4 206.9l.4 .4M516.4 206.9l-.3 .2"/>
<path d="M516.4 207.8l-.5 .1M516.4 207.8l.1 .3M516.4 207.8l.8 .2M516.5 207.5l-.1 .3M516.5 207.5l1 .3M516.5 208.1l-.5 .1M516.5 208.1l.1 .1M516.5 208.1l.5 .1M516.6 208.2l-.1 .2M516.6 208.2h.1M516.6 208.2l.4 .1M516.7 208.2l-.2 .2"/>
<path d="M516.8 207.3l.9 .3M516.8 207.3l-.3 .2M516.8 209.5l.1 .4M516.8 208.2l.1 .2M516.9 209.3l-.1 .2M516.9 210.7l-.2-.1 .6 1.7M516.9 206.7l-.5 .2M516.9 206.7l-.1 .6M516.9 206.7l1.3 .4M516.9 209.9l-.3-.1 .3 .9M517 209.3h-.1M517 209.3l.1 .2"/>
<path d="M517.1 209.9l.1 .6M517.1 209.5h-.3M517.1 209.5l.1 .3M517.2 210.5l-.3 .2M517.2 213.2l.3 .2M517.3 213.2h.1M517.2 209.8l-.3 .1M517.2 205.5l.6 .8 .8 .5-.8-.4zM517.3 212.3h.1M517.3 213.2l.2 .2M517.3 204.9l.4-.1 .6 .3 .7 1.2M517.3 204.9l-.1 .6"/>
<path d="M517.4 212.3l.3 .9M517.5 213.4l.7 .3M517.6 208.6h.1M517.6 208.8l-.6 .5M517.7 208.7v.3M517.7 208.7v.2M517.7 209.5l.4 .1M517.7 208.9h.1M517.7 208.9l.3 .4M517.7 213.2l.4 .1M517.7 209l-.6 .5M517.8 212.2l.3 .8"/>
<path d="M517.8 212.2l-.4 .1M517.8 208.5l-.1 .2M517.9 208.4l-.1 .1M517.9 209.2l.1 .1M518 208.4l-.2 .1M518 208.4h-.1M518 209.3l1.2 .4M518.1 209.3l-.9 .5M518.1 213.3l.1 .3M518.1 209.6l.1 .4M518.1 211.9l-.3-.1-.5 .5M518.1 211.9l.3 .8-.3 .3"/>
<path d="M518.1 211.9l-.3 .3M518.1 213l-.4 .2M518.2 213.6v.1M518.2 210l-.8-.2 .1 .4-.3 .3M518.2 212.1h.1M518.2 213.7h.1M518.3 212.3l.7 .3M518.3 209.5l.1 .3M518.3 209.5l-.2 .1M518.4 213.2l-.3 .1M518.4 213.2l.1 .4M518.4 209.4l-.1 .1"/>
<path d="M518.4 212.7l.8 .2M518.4 209.8l-.2 .2M518.5 213.7h.1M518.5 213.7h-.3M518.5 213.6h-.3M518.5 213.6v.1M518.8 208.7l-.7-.1-.4 .3M518.8 208.7l6.3 1.9M518.8 209.5l-.4 .3M518.8 209.5l.1 .1M518.9 208.4h-.9M518.9 208.4l-.1 .3"/>
<path d="M518.9 208.4l6.3 1.9M518.9 212.8l-.5 .4M519 208.3l-1 .1M519 208.3l2.8 .8 .7-.7 .8 .3-.8 .6 2.8 .9M519 208.3l-.1 .1M519 210.7l.3 .1M519 210.7l.3 .8M519 212.6l.2 .3M519.1 208.2l-.7-.1-.4 .3M519.1 208.2l2.8 .8M519.2 209.7l-.3-.6 1.1 .3 .1 .5 3.1 .9M519.3 213.4v.3"/>
<path d="M519.3 213.7l1.6 1.1M519.3 213.1l.1 .1M519.3 211.5l.2 .1M519.3 211.5l-.2 .2M519.3 212.4l.1 .4M519.3 212.4l-.3 .2M519.3 213.7l1.5 1M519.3 213.7h.1M519.3 210.8l.2 .5M519.3 212.8l.1 .2M519.4 213.3v.2M519.4 213.3l-.1 .1"/>
<path d="M519.4 213v.1M519.4 213l-.9 .7M519.4 212.8l.2 .3M519.4 212.8l-.2 .1M519.4 213.2h.1M519.4 213.5l4.5 1.3M519.4 213.5l-.1 .2M519.5 211.4l.1 .4h.3M519.5 211.4l.3 .1M519.5 213.2l4.6 1.4M519.5 213.2l-.1 .1M519.5 211.6l-1.3 .5"/>
<path d="M519.5 205.7h.1M519.5 205.7l.1 .1M519.6 209.3l-.5 .3M519.6 205.7h.1M519.6 205.8l-3.6 3.4M519.6 211.1l.4 .1M519.6 211.1l-.1 .3M519.6 205.7v.1M519.7 209.3l-.5 .4M519.8 205.7l-.2 .1M519.8 205.7l.6 .2M519.8 205.7l-3.6 3.4"/>
<path d="M519.8 211.5l.1 .3M519.9 205.2l-.4 .1v.4M519.9 205.2l-.1 .5M519.9 205.2l.7 .2M519.9 211.8l-.6 .6M520 211.2l-.2 .3M520.1 209.7l-1.1 1M520.3 209.9l-1 .9M520.4 205.9l.1 .1M520.4 205.9l-2.4 2.3M520.6 205.4l-.2 .5M520.7 205.4l.1 .3"/>
<path d="M520.7 205.4h-.1M520.8 210.1l-1.2 1M520.8 214.7l.1 .1M520.8 214.7l6.3 1.9M520.9 214.8l6.3 1.9M521.1 210.2l-1.1 1M521.9 209h.1M521.9 210.5l-2.5 2.3M521.9 210.5l.2 .1M521.9 210.5l.1 .1M522 205.5l-2.9 2.7M522 205.5l-1 .1-3.4 3"/>
<path d="M522 205.5l6.3 1.9M522 210.6l.2 .2M522 210.6h.1M522.1 210.5v.1M522.1 204.9h-.9l-.5 .5M522.1 204.9l-.1 .6M522.1 204.9l6.3 1.9M522.2 210.8l.4 .1M522.2 210.8l-2.7 2.4M522.2 210.5l.4 .4M522.6 210.9h.9M522.6 208.3l.9 .2-.8 .7"/>
<path d="M522.6 208.3l.1 .2M522.6 208.3l-.7 .7M522.7 209.2l2.7 .8M522.7 209.2v.2M523.2 210.8l-.2-.5 1 .3 .2 .5 2 .6M523.2 210.8l.3 .1M523.6 210.5l-.4 .3M523.9 214.8l.2 .5M523.9 210.5l-.4 .4M524.1 214.6l-.2 .2M524.3 215.1h.1M524.3 215.1l.7 .2"/>
<path d="M524.4 215l3.2 .9M525.1 214.9l-.2 .2 .2 .5-1-.3M525.1 214.9l2.8 .8M525.1 210.6l1.3 .8M525.2 210.3l-.1 .3M525.2 210.3l1.4 .9M525.3 210.2l1.4 .9M525.3 210.2l-.1 .1M525.4 210l1.5 1M526.4 211.4l-.2 .3M526.4 212.1l.2 .4M526.4 212.1h.1"/>
<path d="M526.5 211.9l-.1 .2M526.5 211.7h-.3M526.5 212.1l.8 .3M526.5 212.1l.1 .4M526.5 212.4l-2.4 2.2M526.6 211.9h.1M526.6 211.9h-.1M526.6 211.9l-.1 .2M526.6 211.9l.8 .3M526.6 211.2l-.2 .2M526.6 211.2l.1 .2h-.3M526.6 211.5h.1"/>
<path d="M526.6 212.5l.5 .1 1.3 3.3h-.3l-.1-.4M526.7 211.6h.1M526.7 211.1l.1 .2M526.7 211.1l-.1 .1M526.8 212.5l.1 .3M526.8 211.3l-.3 .4M526.8 211.3h.1M526.9 211.3l-.2 .1M526.9 212.8l.3 .1M526.9 212.8l-2.8 2.5M526.9 211.3l-.4 .4M526.9 211.3v.1"/>
<path d="M526.9 211l.2 .1M527.1 211.2l-.6 .7M527.1 211.1l.1 .1M527.1 216.6l.1 .1M527.1 211.2h.1M527.1 211.2l-.5 .7M527.2 216.7h.8M527.2 212.9l-2.1 2M527.3 212.4l.3 .2M527.4 212.2l.4 .4M527.4 212.2l-.1 .2M527.6 212.6l1.4 4.4"/>
<path d="M527.6 215.9l.4 .4M527.8 212.6h-.2M527.8 212.6l1.4 4.3M527.9 215.8l-.3 .1M527.9 215.8l.3 .3M527.9 216.5l.2 .4M527.9 215.7v.1M527.9 216.3v.2M527.9 216.6h-.8M528 215.5l.3 .1M528 215.6l-.1 .1M528.1 215.3l-.1 .2"/>
<path d="M528.1 216.9h.1M528.1 216.9l.8 .2M528.2 215.2l-.1 .1M528.2 216.9l.8 .3M528.2 215.9h.1M528.2 216l-.3 .3M528.3 215.6l.2 1.1-.6-.2M528.3 215.6h.1M528.3 207.4l1.5 .9M528.3 207.4l-2.9 2.6M528.4 206.8l1.8 1.1M528.4 206.8l-.1 .6"/>
<path d="M528.9 217.1l.1 .1M529 217l-.1 .1M529.2 206.3l1.8 1.1 1.2 1.9 .5-.2M529.2 217.1l-.2 .1M529.2 216.9v.2M529.2 216.9l-.2 .1M529.3 205.7l2 1.3 1.4 2.1M529.3 205.7l-.1 .6M529.8 208.3l.3 .2M529.8 208.3l-2.9 2.7M530.1 208.5l-2.9 2.7M530.1 208.5l1 .3"/>
<path d="M530.2 207.9l.1 .1M530.2 207.9l-.4 .4M530.3 208l-.2 .5M530.3 208l.9 .3M530.4 204.8h.1M530.4 204.8l-1.1 .9M530.4 204.8l1.4 .7 1.2 1.3M530.4 216.1l2.4 .7M530.5 216l2.2 .7M531 204.6l1.6 1.1 1.2 1.7M531 204.6l-.3 .3M531 204.2l1.9 1.2 1.3 2"/>
<path d="M531.1 204.4l1.7 1.1 1.3 1.8M531.1 204.4l-.1 .2M531.1 203.9l2 1.3 1.4 2.1M531.1 203.9l-.1 .3M531.1 208.8l.4 .4M531.1 208.8l-3.7 3.4M531.2 208.3l.8 .8M531.2 208.3l-.1 .5M531.3 203.7l2.1 1.3 1.4 2M531.3 203.7l-.2 .2M531.4 203.6l2 1.3 1.4 2.1M531.4 203.6l-.1 .1"/>
<path d="M531.5 209.2l.7 2.2M531.5 209.2l-3.7 3.4M531.7 212.8l.1 .3M531.8 213.1l.3 .3 .4-.1M532 211.7l.6 .6M532 211.7l-.3 1.1M532 209.1l-.5 .1M532 209.1l.8 2.2M532.2 211.4l.5 .8M532.2 211.4l-.2 .3M532.2 203.5l1.6 1 1.2 1.6M532.2 203.5l-.3 .3"/>
<path d="M532.3 203.1l1.7 1 1.4 1.8M532.4 209.4h.1M532.3 203.2l1.7 1.1 1.3 1.7M532.3 203.2l-.1 .3M532.3 202.8l1.9 1.1 1.4 1.9M532.3 202.8v.3M532.5 212.5l-.8 .3M532.5 212.5v.1M532.5 212.5l.1 .4M532.5 212.6l.1 .3M532.5 212.9v.4M532.5 212.9h.1"/>
<path d="M532.6 210.1l.4 1.3M532.6 212.3l-.1 .2M532.6 212.3h.1M532.6 212.9h.1M532.6 212.9h-.1M532.6 202.5l1.9 1.2 1.4 1.9M532.6 202.5l-.3 .3M532.6 212.9l-.8 .2M532.6 212.3l-.1 .3M532.7 212.9v.1M532.7 216.7l.1 .1M532.7 212.2h.1"/>
<path d="M532.7 212.2l-.1 .1M532.7 209.1l.1 .2M532.7 202.5l1.8 1.1 1.4 1.9M532.7 202.5h-.1M532.8 213h.1M532.8 209.3l-.4 .1M532.8 212.2h.3M532.8 213l.2 .7M532.8 213l-.3 .3M532.8 211.3l-.6 .1M532.8 211.3l-.1 .9M532.8 211.3l.2 .1"/>
<path d="M532.8 208.1l.1 .4M532.8 208.1h.1M532.8 208.1l.1 .2M532.8 208v.1M532.9 207.9l-.1 .1M532.9 207.9v.1M532.9 208l-.1 .1M532.9 208.5l.1 .3M532.9 209.2l.1 .2M532.9 208.3v.1M532.9 214l.3 .1M532.9 207.8l.1 .1"/>
<path d="M532.9 207.8v.1M532.9 208.4l.1 .1M533 207.9l-.1 .1M533 208.5h-.1M533 209.4v.1M533 209.4l-.6 .5 .2 .2M533 206.8h.1M533 213.9l-3.8 3.2M533 208.4v.1M533 206.8l.2 .5-.3 .5M533 211.4h.2M533 211.4l-.2 .8"/>
<path d="M533 208.7l.1 .2M533 213.7v.2M533 213.7l-3.8 3.2M533 206.8l.2 .6-.2 .5M533 209.5l.2 .1-.6 .5M533 208.8l-.2 .5M533 208.8l-.3 .3M533.1 213.9h.1M533.1 208.1l-.2 .2M533.1 208.1l.1 .2M533.1 213.9h-.1M533.1 213.9l.1 .2"/>
<path d="M533.1 208.9h.1M533.1 208.9l.7 .2M533.1 212.2l-.5 .1M533.1 209.2h.1M533.2 209.2h.1M533.2 211.4h.3M533.2 211.4l-.1 .8M533.2 209.2l.1 .3M533.2 209.2l1.2 .5 1.4 4.1M533.2 208.3l-.1 .5M533.2 208.3l.7 .2M533.3 212.9l.3 .7"/>
<path d="M533.3 209.5h-.3M533.4 212.9l.1 .1M533.5 212.1l-.4 .1M533.5 212.1l.1 .2M533.5 212.9v.1M533.5 213h.2M533.5 213l.4 1.2M533.5 211.4l.8 .3M533.5 211.4v.7M533.6 213.6l-.1 .4-.3 .1M533.6 213.6l-.6 .1M533.6 212.3l-1.1 .3"/>
<path d="M533.6 212.3l.1 .3M533.6 212.8l.1 .2M533.6 209.3l-.3 .2M533.6 212.7l-1 .2M533.6 212.7h.1M533.6 209.9l-1 .2M533.6 209.9l.7 1.8M533.7 212.7l-1 .3M533.7 212.6l-.1 .1M533.7 212.6v.1M533.7 212.7h.1M533.8 212.7l.2 .2"/>
<path d="M533.8 209.1l.8 .8M533.8 207.4l.2 .2M533.8 207.4l-.7 .7M533.9 214.3l.2 .7M533.9 208.5l.8 .5 .5 .8M533.9 208.5l-.1 .6M533.9 214.2v.1M534 214.2l-.1 .1M534 212.9l-.3 .1M534 207.6l.2 .1M534 207.6l-.8 .7M534.1 215l.1 .8-.2 .6-.5 .4-.8-.1"/>
<path d="M534.1 207.3l-.1 .3M534.1 207.3l-.3 .1M534.1 207.3l.1 .1M534.1 209.5l-.5 .4M534.2 207.4v.3M534.3 211.7l-.8 .4M534.3 211.7l-.7 .6M534.4 212.1l-.6 .5M534.4 212.1l-.4 .8M534.4 212.1l.6 1.8M534.4 212.1l-.7 .6M534.4 216.6l-.7 .3-.9-.1"/>
<path d="M534.4 214.2l-.4 .4 .2 .2M534.5 207.3l.2 .2M534.5 207.3l-.3 .1M534.6 214.7l-.4 .1M534.6 214.7v.1M534.6 214.2l.1 .1M534.6 214.8l.2 1.1-.4 .7M534.6 214.8l-.5 .2M534.6 209.9l1.3 3.7M534.7 207.5l-.5 .2M534.7 214.3l.2 .1M534.7 214.3l-.5 .5"/>
<path d="M534.8 207h.1M534.8 207v.1M534.8 207.1l.2 .2M534.8 207.1l-.3 .2M534.9 214l-1 .2M534.9 214h.1M534.9 214v.2M534.9 214.2v.2M534.9 214.2l-.2 .1M534.9 214v.1M534.9 214.4v.1M534.9 214.4l-.3 .3"/>
<path d="M534.9 214.1l.1 .2M534.9 214.1v.1M534.9 214.1h.1M534.9 214.4h.1M534.9 214.5l.2 .5M534.9 214.5l-.3 .3M534.9 214.4l.1 .1M534.9 214.1l.7 .2M534.9 214l.6 .1M534.9 207l.1 .3M534.9 207h-.1M535 206.4l.2 .2"/>
<path d="M535 206.4l-.3 .2M535 214.3l.1 .6M535 214.5v.2M535 207.3l-.3 .2M535 213.9l-.1 .1M535 206.1v.3M535 214.9h.1M535.1 215v.1M535.1 214.1l-.2 .1M535.1 214.9v.1M535.1 215.1h.2M535.1 215l.2 .1"/>
<path d="M535.1 215h.1M535.2 206.6l-.3 .4M535.2 206.6l.6 .2M535.2 214.9h-.1M535.2 214.9h.1M535.2 209.8l-.6 .1M535.2 209.8l1.2 3.7M535.2 213.7l.5 .2M535.2 214.9l.1 .1M535.2 214.9l-.1 .1M535.3 206l-.3 .1M535.3 206l-.1 .6"/>
<path d="M535.3 206l.2 .1M535.3 215l.3-.1 .2 .1M535.3 215v.1M535.4 205.9l.1 .2M535.5 215.7l-1.1 .9M535.5 206.1l.4 .3M535.5 214.1l.1 .2M535.6 214.7l-.4 .2M535.6 214.7l-.5 .2M535.6 214.7h.1M535.6 214.7l.2 .4M535.6 205.8l.1 .1"/>
<path d="M535.6 205.8l-.2 .1M535.6 213.3l-.6 .6M535.7 213.8v.1M535.7 205.9l.3 .3M535.7 205.9l-.2 .2M535.7 213.7v.1M535.7 213.7h.1M535.8 213.6l-.1 .1M535.8 215.1l-.3 .6M535.8 215v.1M535.8 215.1h.1M535.8 213.8l-.1 .1"/>
<path d="M535.8 213.8h-.1M535.8 206.8l.8 .5 .5 .8M535.8 206.8l-1.9 1.7M535.9 200.2l.9 .6M535.9 200.2l.9 .1M535.9 200.2l-2.8 2.5M535.9 206.4h.1M535.9 213.6v.5h-.4M535.9 205.6l-.3 .2M535.9 214.3l-.2 .4M535.9 205.6h.1M535.9 205.6l.4 .3"/>
<path d="M535.9 205.5l.1 .1M535.9 205.5v.1M536 206.2l-.1 .2M536 206.2h.1M536 206.4l.9 .6 .6 .9M536 206.4l-.2 .4M536 205.6h.1M536 205.6l.3 .3M536.1 206.2l.9 .7 .7 .9M536.1 206.2l-.1 .2M536.1 205.6l.2 .3M536.1 205.6h-.1"/>
<path d="M536.2 214.3l-.4 .6M536.3 205.9l-.3 .3M536.4 214.2l-.8 .1M536.4 214.1l-.2 .6-.4 .4M536.4 213.5v.7M536.4 213.5l-.5 .1M536.6 213.9l-.2 .9-.7 .5M536.8 200.8l1.1 1.1 .8 1.4M536.8 200.3h.1M536.8 200.3l.5 .3M536.9 200.3h.1M537 213.6l-.4 1.2 .3-1.1"/>
<path d="M537 213.8h.1M537.1 208.1l1.2 3.7M537.1 208.1l-1.9 1.7M537.3 200.6l-.5 .2M537.3 200.6l1 1 .6 1.1M537.4 213.2l-.4 .6M537.5 207.9l-.4 .2M537.5 207.9l1.2 3.7M537.5 203.7l.2 .2M537.5 203.7l-1.7 1.6M537.6 213l-.2 .7-.5 .3M537.7 207.8l-.2 .1"/>
<path d="M537.7 207.8l1.2 3.7M537.7 203.9l1.1 .1M537.7 203.9l-1.6 1.7M537.7 203.9l.7 .2M537.9 212.8l-.2 .9-.8 .5M538.2 212.5h.1M538.2 203.7v.1M538.2 203.7l.1 .2M538.2 203.7h-.7M538.2 212.5l-.4 1.1zM538.3 211.8v.6l-1.9 1.8M538.3 211.8l-1.9 1.7"/>
<path d="M538.4 204.1l1 .6 .6 1M538.4 204.1l-2.3 2.1M538.7 203.3l.3 .8M538.7 203.3l-.5 .4M538.7 211.6v.7l-.5 .2M538.7 211.6l-.4 .2M538.8 204l.8 .5 .5 .9M538.8 204l-.4 .1M538.8 212.4l-.6 .1M538.9 211.5l-.1 .9M538.9 211.5l-.2 .1M538.9 202.7l-.2 .6"/>
<path d="M538.9 202.7l.6 1.7M540 205.7l1.2 3.7M540 205.7l-2.3 2.1M540.1 205.4l-.1 .3M540.1 205.4l1.3 3.7M541.1 206.5l.4 .4M541.1 206.5l-.4 .4M541.2 210.2l-2.4 2.2M541.2 209.4v.8M541.2 209.4l-2.3 2.1M541.4 209.1v.6l-.2 .5M541.4 209.1l-.2 .3"/>
<path d="M541.5 206.9l.1 .3M541.5 206.9l-.6 .6M541.6 207.5l-.6 .5M541.6 207.2v.3M541.6 207.2l-.7 .6M542.1 203.6l.8 1.2M542.1 203.6l1 2M542.2 207.1l.1 .3M542.3 207.4l.1 .1M542.3 207.4l-1.2 1M542.4 207.5l-1.2 1M542.4 207.5l.3 .1"/>
<path d="M542.4 206l.1 .5M542.4 206l-1.3 .5M542.5 206.5l-1 .4M542.5 206.5v.3M542.5 207l.1 .3M542.5 206.8l-.9 .4M542.5 206.8l.2 .2M542.5 203l-2.4 2.2M542.6 207.3l.1 .3M542.6 207.3l-.3 .1M542.7 207.6h.1M542.7 207l-1.1 .5"/>
<path d="M542.9 204.8l.2 .8M543.1 208.8h.1M543.1 208.8l.4 .5 .9 .3 2.2-.2 1.8-1.2 .5-.7v-.7v.8l-.4 .8-1.9 1.2-2.3 .2-.8-.4zM543.2 202.6l1.6-.7 .7 .2 .3 .4-.5 .9-1.5 .4-.9-.3zM544.3 205.8v.5M544.3 205.8l-1.9 .2M544.3 206.3l-1.8 .2M544.3 206.3l.1 .3M544.4 206.6l-1.7 .4M544.4 206.6l-1.4 .4M544.4 206.6l-1.9 .2M545.3 204.5l-2.4 .3"/>
<path d="M545.3 204.5l.3 .9M545.3 209.8l.9 2.5 .4 .3M545.6 205.4l-2.5 .2M546 201.3l.4 .1 1.2 1.8M546 201.3l1.2 1.8M546.1 200.8l.4 .4M546.1 200.8l-.1 .5M546.4 201.4h.1M546.5 212.6h.1M546.5 201.2l-.1 .1M546.5 201.2l.1 .3M546.6 212.6h.1"/>
<path d="M546.6 212.6v.1M546.6 212.7h.1M546.6 201.5v.1M546.6 201.5l.1 .3M546.7 212.7h.1M546.7 212.7l.1 .1M546.8 212.8h.1M546.8 212.8h.2M546.9 203.1l-.3-.6a1.69 1.69 0 0 0-2.1-.6l-1.3 .5-1.1 1.2M546.9 203.1l-1.6 1.4M546.9 203.1l.3 .8-1.6 1.5M546.9 212.8h.1"/>
<path d="M547 212.8h.1M547.1 212.8h.1M547.2 203.1l.1 .8-.6 .9-1.1 .6-1.3 .4M547.2 203.1l.4 .1M547.3 212.8h-.1M547.3 212.8h.1M547.4 212.8h-.1M547.5 212.8h-.2M547.5 212.8h.1M547.6 203.2l.2 1-.7 .9-1.2 .8-1.6 .4M547.7 209l.9 2.5-.2 .5M548.3 212.4h.1"/>
<path d="M548.3 212.3l-.1 .1M548.3 212.3h.1M548.4 212l-.8 .6h-1M548.4 212l-.8 .5-1 .1M548.4 212.2h.1M548.4 212.1h.1M548.4 211.9h.1M550 200.6l-.1 .1M580.2 210.8h9.5M26.5 220.5v5.6h16.7l.7-.7M108.8 220.5v5.6h-16.6l-.7-.7M239.3 232.8l-10.8 15.6"/>
<path d="M285.9 226.9v2.3M285.9 231.4v7.3M332.5 232.8l10.7 15.6M436.5 235.5v8.3M442.6 222.2l.5 .7 2.4 .1v60h-1.8l-.5 .8M442.7 225.9l-.4-44.9a3 3 0 0 0-3-3h-20.1a6 6 0 0 0-6 5.8l-2.2 84.2M31.3 258.3a1.42 1.42 0 0 1 1.4-1.3h69.9a1.42 1.42 0 0 1 1.5 1.3M32.5 259.3h-4.3v4l-2 3.7-.1 1.6M33 257l-.6 .4-.1 1.2 .3 1.7 .5 .4h69.2M44.1 245.6l1.2-4.7 1.2 4.7M44.6 244h1.4M49.1 243.2l6.5-1v2z"/>
<path d="M49.1 243.2h18.6M53.2 254.9l-.4 .4h-19.3a2.13 2.13 0 0 0-2.1 2l-.2 2M56.1 248.4h10.6v2.1h2v-2.1h11.1M56.6 247.5h.4M56.8 248.4l-.3-1.8-.5-.6h-2l-.6 .4-.3 9.9-.2 .5-.5 .2M57 247.5l.3-.2h21.1l.3 .2 .1 .5h-10.2v2.1h-1.8v-2.1h-9.9zM57.2 248v.4M57.5 248v.4M60.1 248v.4M61.4 248.4v8.4h1v-8.4M61.5 248v.4M62.5 248v.4"/>
<path d="M69.9 248v.4M72.4 248v.4M72.9 248.4v8.4h1.1v-8.4M78.2 248v.4M78.7 247.5h.4M78.9 248.4l.6-2.3 1.8-.1 .5 .2 .2 .5 .2 9.6 .2 .5 .5 .2M82.2 254.9l.3 .4h19.4a2.13 2.13 0 0 1 2.1 2l.1 2M102.3 257l.7 .4v1.2l-.3 1.7-.4 .4M102.8 259.3h4.4v4l2 3.7 .1 1.6M135.3 259.4l-.9 .5M135.3 259.4l1.5 .2v.3l-.7 .3 .7 .2 .1 .5a.37 .37 0 0 0-.5 .3 .37 .37 0 0 0 .5 .4l-.4 .5 .4 .3M135.4 259.3l-.1 .1"/>
<path d="M135.5 258.6l-.2 .1M136 258.6l.2 .4 .6-.1 .1-.3M136.2 257l-1.8 1M137.8 257l-3.4 2M139.1 260l-1.5 .8M139.1 259l-1.5 .9M139.4 257l-2.8 1.6M139.8 258.6l.6 .1 .4 .3 .1 2.4 .4 .6 .1 9.5M139.8 258.6l-.5 .2-.2 .5-.1 4.4M140.9 256.8v-8.4h.4l-.2 8.2-.7 .4h-5.3l-.5 .2-.2 .5v3h.9M141.2 250.5h1.2M142.1 247.3l-.8 .8"/>
<path d="M142.4 250.1l.1 7M142.4 250.6l-1.2 .7M142.5 251.5l-1.3 .8M142.5 252.5l-1.3 .7M142.5 253.4l-1.3 .7M142.5 254.3l-1.4 .8M142.5 255.2l-1.4 .8M142.5 256.1l-4.9 2.9-.4-.4M142.5 259.2l.2 .3-.2 .3-1.6 1M142.5 257.5l.2 .3-.2 .3M142.5 259.1l.6 .9M142.5 257h.4l.4 .4"/>
<path d="M142.5 257v3.6l.9-.8M142.5 257.1l-2.7 1.5M142.5 258l-1.7 1M142.5 258.9l-1.6 .9M142.6 258l1.2 1.7M142.8 247.3l.1-.9 .6-.4h9.6l.7 .4 .1 .9M142.8 257l1.1 1.6M143 247.3l-1.7 1.7M143.3 257.4h2.2M143.3 257.4l-.7-.7v-6.6h-1.3v-2.4l.3-.4h2l.2 .5v10.1M143.7 247.5l-2.4 2.4M143.8 248.6l.1 .1"/>
<path d="M143.8 257.9l.4 .6M143.8 248.2l-1.8 1.9M143.8 249.1l-1.2 1.2M143.8 250l-1.2 1.2M143.8 250.8l-1.2 1.3M143.8 251.7l-1.2 1.2M143.8 252.6l-1.2 1.2M143.8 253.4l-1.2 1.3M143.8 254.3l-1.2 1.2M143.8 255.2l-1.2 1.2M143.8 256l-1 1M143.8 256.9l-.5 .5"/>
<path d="M143.8 255.3h1.7M143.8 259.4v.4M143.8 259.4h1.7M143.8 257.9h1.7M143.8 255.9h1.7M143.8 248.7h.1M143.8 258.7h1.7M143.8 258.6h1.7M143.8 258.6v.1M143.8 258.7l.4 .1M143.9 246l.1 9.1M143.9 250.8h.1"/>
<path d="M143.9 246.7h1.9M144 248h.8M144 247.5v7.8M144 258.8l.2 .2M144.1 259.8l-3.1 1.8M144.2 258.8l-.4 .6M144.2 258.5l-.4 .1M144.2 258.8h1.3M144.2 258.5h1.3M144.4 259.8v.8M144.8 247.5v2.2h.8l.2 .5v4.5M145.5 259.8h-2.2l-.4 .4"/>
<path d="M145.8 246v1.5h-1.9M145.8 254.7l-.3 .6M145.8 254.7h.1M145.9 254.7l.3 .6M146.2 255.1h4.3M146.2 255.3h.1M146.2 255.3h4.3M146.2 258.7h4.3M146.2 258.6h4.3M146.2 259.8h4.3M146.2 259.4h4.3M146.2 258.8h4.3"/>
<path d="M146.2 258.5h4.3M146.2 257.9h4.3M146.2 257.4h4.3M146.2 255.9h4.3M146.3 255.3h.1M146.9 257.4l.5-.5h1.8l.6 .5M147.3 257h2.1M150.4 255.3h.1M150.5 255.3l.3-.6 .4 .6M150.9 246v1.5h1.9M150.9 246.7h1.9M151.2 258.7h1.6"/>
<path d="M151.2 258.6h1.6M151.2 255.3h1.7M151.2 259.8h2.2l.4 .4M151.2 259.4h1.7M151.2 258.8h1.3M151.2 258.5h1.3M151.2 257.9h1.7M151.2 257.4h2.2M151.2 255.9h1.7M151.9 248h.8M151.9 247.5v2.2h-.8l-.2 .5v4.5M152.2 259.8v.8h-7.8"/>
<path d="M152.5 258.8l.4 .6M152.5 258.5l.3 .1M152.5 258.4l.1 .1M152.7 247.5v7.8M152.7 250.8h.1M152.7 258.7l1.1 1.5M152.8 246l-.1 9.1M152.8 248.7h.1M152.8 258.7l-.3 .1M152.8 258.6v.1M152.9 257.9l-.4 .6M152.9 249.5l1.2-1.1h1.3l.1 7.9 .5 .6 2.2 .1 .6 .4 .1 3.3h-.9"/>
<path d="M152.9 257.7l1.1 1.7M152.9 259.4v.4M152.9 248.6l-.1 .1M153.4 257.4l.7-.7v-8.7h1.3l-.1-.5-.3-.2h-2l-.1 .5v10.1M153.4 247.3l-.5 .5M153.4 260l-6.2 3.6M153.5 257.3l.7 1M154.1 249.2l-1.2 1.2M154.1 250.1l-1.2 1.2M154.1 250.9l-1.2 1.2M154.1 251.8l-1.2 1.2M154.1 252.7l-1.2 1.2"/>
<path d="M154.1 253.5l-1.2 1.3M154.1 254.4l-1.2 1.2M154.1 255.3l-1.2 1.2M154.1 256.1l-1.2 1.3M154.1 248.7h.1M154.2 259.2l-.2 .3 .2 .3M154.2 257.5l-.2 .3 .2 .3M154.2 257h-.4l-.4 .4M154.2 257v3.6l-.9-.8M154.2 248.7v8.4M154.3 247.3l-1.4 1.4M154.6 248.4l-.4 .3"/>
<path d="M155.1 247.3l-.7 .7M155.4 247.9l-.1 .1M155.4 248.7l-1.2 .7M155.4 249.6l-1.2 .7M155.4 250.5l-1.2 .7M155.5 251.4l-1.3 .8M155.5 252.3l-1.3 .8M155.5 253.3l-1.3 .7M155.5 254.2l-1.3 .7M155.5 255.1l-1.3 .8M155.5 256l-1.3 .8M155.8 256.8l-1.6 .9"/>
<path d="M155.8 259.6l-1.6 .9M156.1 258.6l-.3 .4M156.5 258.6l.1 .4 .7-.1v-.3M157 257l-2.8 1.7M157.8 258.6l.2 .1M158 259.9l-1.4 2M158 259.4l-1.5 .2v.3l.7 .3-.7 .2-.1 .5a.37 .37 0 0 1 .5 .3 .37 .37 0 0 1-.5 .4l.1 .3M158.5 257.1l-4.3 2.5M158.9 257.8l-1.4 .8M158.9 258.7l-.9 .5M158.9 259.6l-.9 .5M228.5 257.6l8.9 12.7 .2 .5"/>
<path d="M239.8 247.7l.8-.3h1.8l.5 .1 .4 .6v9.5a1.02 1.02 0 0 1-1 1h-1.7a1.02 1.02 0 0 1-1-.6 1.02 1.02 0 0 1 .2-1 6.6 6.6 0 0 0-.2-8.5zM241.3 245h-6.2a8 8 0 0 0-8 8 8 8 0 0 0 8 8h3.4l.5 .5-1.8 11.3M285.9 245.5a7.5 7.5 0 0 1 7.5 7.5v34.5M285.9 245.5a7.5 7.5 0 0 0-7.5 7.5v34.5M285.9 241v2.2M285.9 245.5v7.3M285.9 255v2.3M285.9 259.6v7.3M328.7 247.7l.7-.3h1.8a1.02 1.02 0 0 1 .9 .6 1.02 1.02 0 0 1-.2 1.1 6.6 6.6 0 0 0 .3 8.4l-.1 .5-.6 .6a3.4 3.4 0 0 1-2.7-.3l-.3-.7-.1-9.2zM330.4 245h6.3a8 8 0 0 1 8 8 8 8 0 0 1-8 8h-3.5l-.5 .5 1.8 11.3M333.3 245l-.5-.2-.2-.6-.6-63.2a3 3 0 0 0-3-3h-86.3a3 3 0 0 0-3 3l-.5 63.2-.2 .6-.6 .2M343.2 257.6l-8.9 12.7"/>
<path d="M429.5 245.2v17.7M429.5 245.2h.1M429.5 245.1v.1M436.5 243.5a1.52 1.52 0 0 1-1.5 1.5h-5.2l-.3 .2M529.6 254.2l-20.1 17.9M530.9 254.1l-.7-.1-.6 .2M530.9 254.1l-20.1 17.9M530.9 254.1l22.4 7.9M532 253.7l-1.1 .4M532 253.7l22.3 7.9M532 253.7l-1.3-.1-1.1 .6M26.1 268.6l.1 2.4 .7 1 6.1 .1"/>
<path d="M26.1 268.6h2.1M30.7 267.7l-.9-.1v.3l1.2 3.3h.3l.4-3.3M33.1 260.7v1.7a45.5 45.5 0 0 0 .7 11.3l-.3-.4-.5-.1v-5.1l-4.8-.7v4.7M33.8 273.6l.1 .5M33.9 274.1l-.1 .4M33.9 274.1h.1M39.6 269.8h1.1l.4 .6v14.5l-.2 .5-.5 .2h-2.2l-.6-.3a6.3 6.3 0 0 0-5-4.4l-.1-.9zM39.9 265.7l55.3-.1 12.6 17.8a5.6 5.6 0 0 1 0 6.4l-12.2 17.5-.6 .3h-54.9l-12.6-17.8a5.6 5.6 0 0 1 0-6.4zM43.2 278.4l.5 .5h48l.5-.5M43.2 267.5l.5-.5h48l.5 .5M43.2 265.6v42M43.9 265.6v1.4"/>
<path d="M43.9 278.9v1.4M53.7 272.7l.8-.4h7.3a1.06 1.06 0 0 1 1.1 1 1.06 1.06 0 0 1-1.1 1.1l-7.6-.1-.7-.6zM55.8 275.4l.9-.4h7.3a1.06 1.06 0 0 1 1.1 1 1.06 1.06 0 0 1-1.1 1.1l-7.7-.1-.6-.6zM57.3 270l.8-.4h7.3a1.06 1.06 0 0 1 1.1 1 1.06 1.06 0 0 1-1.1 1.1h-7.6l-.7-.7zM68.5 269.6h6.4l-.4 1.7h-2.3l-1.6 5.8h-1.9l1.6-5.8h-2.3zM75.5 269.6h6l-.5 1.7h-4l-.4 1.3h3.6l-.4 1.5h-3.6l-.3 1.3h4l-.5 1.7h-5.9zM91.5 265.6v1.4M91.5 278.9v1.4M92.2 265.6v42M94.5 269.9l.8-.2 .6 .3 7 10-.1 .9a6.4 6.4 0 0 0-5.1 4.4l-.5 .3h-2.2l-.7-.5v-14.7zM101.6 273.6v.9M102.3 260.7l-.1 1.7a45.5 45.5 0 0 1-.6 11.3l.2-.4 .6-.1v-5.1l4.8-.7v4.7"/>
<path d="M104.6 267.7l1-.1v.3l-1.2 3.3h-.4l-.3-3.3M107.2 268.6h2.1M109.3 268.6l-.1 2.4-.8 1-6 .1M133.7 267.5l.5-.5a.64 .64 0 0 1 .9 .5v10.9a.64 .64 0 0 1-.9 .5l-.5-.5M134.4 265.6v1.4M134.4 278.9v1.4M135.1 260.4l-.5 .3M135.1 260.3l-.4 .4M135.1 260.3h.1M135.1 275h-.3v2.1h.3M135.1 272.3h-.3v2.1h.3M135.1 269.6h-.3v2.1h.3"/>
<path d="M135.2 260.3h.1M135.2 260.2v.1M135.3 260.2h-.1M135.3 260.1v.1M135.3 260.1l-.2 .2M135.3 260.1v-1.5h2.3v4.7l.4 .7h2.6l.3 .2M136.7 260.9l-.3-.5-.1-.9-1-.2v6l-.3 .3h-1.3v42h1.5l.5 .5 .3 28.9a2.1 2.1 0 0 0 2.1 2.1h14a4.2 4.2 0 0 0 4.2-4.1l1.6-58.9 .1-16.8-1 .2-.1 .9-.3 .5M136.7 261.6l-1.4 1.9M136.7 262.5l.2 29.4h.8M136.7 260.9v1.6M136.7 262.5l.2 .1M136.7 262.5h.2"/>
<path d="M136.7 260.9h.2M136.7 265.6l-1.6 2.3M136.7 269.7l-1.6 2.3M136.8 273.8l-1.7 2.3M136.8 277.8l-1.8 2.7M136.9 262.4v.4h.7M137 262.8l.4 .4M137.4 263.2l.6 67.4 1.9 2v4.4h2v-.9a1 1 0 0 1 1.3-.7l2.2 .1M137.5 269.1h.1M137.5 273.4l2.2 6.1v52.8M137.6 263.1l-.2 .1M138.2 266.6h.1"/>
<path d="M138.2 268.3h.1M138.2 266.6v1.7M138.8 277l1 2.2M138.9 270.5l.6 .4M138.9 266.1l.6 .3M138.9 266.1h.1M138.9 270.5h.1M139 263.7l-.5 .3M139 263.7l-.4 .3M139 262.8l-1.3 .7M139 261.8l-1.4 .9M139 260.9l-1.4 .9"/>
<path d="M139.5 270.2l-.6 .3M139.5 265.7l-.6 .4M139.8 279.2h.1M139.8 279.2v.1M139.8 279.9l1.1 1M139.8 277.1l1.1 1.1M139.8 274.3l1.1 1.1M139.8 271.5l1.1 1.1M139.8 268.7l1.1 1.1M139.8 266l1.1 1.1M140.6 263.7l.3 .5v71.3h-1.1v-71.1h1.1M140.7 264l.2 .3"/>
<path d="M141.2 265v6.6M141.2 265h.2M141.3 265h-.1M141.4 271.5l.4 .3M141.4 271.5l-.2 .1M141.4 271.4l-.2 .1M141.4 271.3l-.2 .1M141.4 271.3h-.2M141.4 271.2l-.2 .1M141.4 271.1l-.2 .1M141.4 271l-.2 .1M141.4 270.9l-.2 .1"/>
<path d="M141.4 270.8l-.2 .1M141.4 270.7l-.2 .1M141.4 270.5l-.2 .1M141.4 270.4l-.2 .1M141.4 270.3l-.2 .1M141.4 270.2l-.2 .1M141.4 270.1l-.2 .1M141.4 270l-.2 .1M141.4 269.9l-.2 .1M141.4 269.9h-.2M141.4 269.8l-.2 .1M141.4 269.6l-.2 .1"/>
<path d="M141.4 269.5l-.2 .1M141.4 269.5h-.2M141.4 269.4l-.2 .1M141.4 269.3l-.2 .1M141.4 269.2l-.2 .1M141.4 269.1l-.2 .1M141.4 269l-.2 .1M141.4 268.9l-.2 .1M141.4 268.8l-.2 .1M141.4 268.7l-.2 .1M141.4 268.6l-.2 .1M141.4 268.6h-.2"/>
<path d="M141.4 268.5l-.2 .1M141.4 268.4l-.2 .1M141.4 268.3l-.2 .1M141.4 268.2l-.2 .1M141.4 268.2h-.2M141.4 268.1l-.2 .1M141.4 268l-.2 .1M141.4 267.9l-.2 .1M141.4 267.8l-.2 .1M141.4 267.7l-.2 .1M141.4 267.7h-.2M141.4 267.6l-.2 .1"/>
<path d="M141.4 267.5l-.2 .1M141.4 267.4l-.2 .1M141.4 267.3l-.2 .1M141.4 267.2l-.2 .1M141.4 267.1l-.2 .1M141.4 267l-.2 .1M141.4 266.9l-.2 .1M141.4 266.8l-.2 .1M141.4 266.7l-.2 .1M141.4 266.6l-.2 .1M141.4 266.5l-.2 .1M141.4 266.4l-.2 .1"/>
<path d="M141.4 266.4h-.2M141.4 266.3l-.2 .1M141.4 266.2l-.2 .1M141.4 266.1l-.2 .1M141.4 266l-.2 .1M141.4 265.9l-.2 .1M141.4 265.8l-.2 .1M141.4 265.7l-.2 .1M141.4 265.6l-.2 .1M141.4 265.5l-.2 .1M141.4 265.5h-.2M141.4 265.4l-.2 .1"/>
<path d="M141.4 265.3l-.2 .1M141.4 265.2l-.2 .1M141.4 265.1l-.2 .1M141.4 265l-.2 .1M141.4 265v6.6h-.2M142.5 260.2h.5M142.5 271.3l-.3 .5M142.5 271.2v.1M142.6 270.9l-1.4 .7M142.9 269.8l-1.7 .9M143.1 268.7l-1.9 1.1M143.4 267.6l-2 1.2"/>
<path d="M143.7 266.6l-2.3 1.3M143.7 270.9l-.2 .9h-2.6M143.7 266.4v3.8M143.8 265.8l-1.3 5.4M143.9 265.8h.1M143.9 265.7v.1M143.9 265.7h.1M144.1 265.6l-.3 .2M144.1 265.6l-.2 .1M144.1 265.6h.5M144.4 260.6l-3.1 1.8M144.8 265l-3.4 2"/>
<path d="M144.8 264.1l-3.5 2M144.9 268.5h.2M145 260.6l.5-.4h.7l.4 .4M145.1 263.4l.4 .5M145.1 267.1v1.4M145.2 266.5l.2 1.7-.3 .3M145.3 266l-.5 2.9-.4 .6-.7 .3M145.5 263.9v.4M145.5 263.9h.7M145.7 265.6h2.3M146 260.6l-4.7 2.7M146.2 263.9v.4"/>
<path d="M146.6 263.4l-.4 .5M147.6 260.6l-6.3 3.6M147.9 265.1l-.6-.6-.2-1-1.9-.1-.4 .4-.1 1.7-.3 .1M147.9 265.1l.2 4.7a1.11 1.11 0 0 0 1.2 .1 1.11 1.11 0 0 0 .6-1v-.4M149.2 260.6l-7.9 4.5M149.9 268.5l-1.9 1.1M149.9 263.9l-2 1.2M149.9 264.8l-1.9 1.1M149.9 265.7l-1.9 1.1M149.9 266.6l-1.9 1.2M149.9 267.6l-1.9 1.1M149.9 265.6h.6"/>
<path d="M150 260.6l.5-.4h.7l.4 .4M150.1 263.5l.4 .4M150.5 263.9v4.8a1.43 1.43 0 0 1-1.5 1.5M150.5 263.9h.7M150.8 260.6l-4.9 2.8M151.2 263.9v4.8a2.13 2.13 0 0 1-2.2 2.2M151.6 263.4l-.4 .5M153.6 265.6l-.4-.3-.2-1.8h-2.9l-.2 .3v4.7M153.7 260.2h.5M153.7 276h2.1M154 260.6l-6.7 3.9M154.3 265.1l-.9 .5"/>
<path d="M155.4 269.5l-12.8 10.8M155.5 269.4l-.1 .1M155.5 269.4h.1M155.7 278.5l-1.2 2.5-1.4 54.5M155.8 263.3l-.4 .7-1.1 .2-.2 1.4h-2.9M155.8 260.5l-5.1 2.9M155.8 261.4l-3.5 2M155.8 262.4l-2.6 1.4M155.8 263.3l-2.6 1.5M155.8 263.1l.1 .1M155.8 276l-1.6 59.3-8.8 .2M155.8 268.5l-.4 1"/>
<path d="M155.9 263.2l-.1 12.8M156.4 262.4v.4h-.6M156.4 262.5h.2M156.5 260.9h.1M156.5 262.4h-.1M156.5 262.4h.1M156.5 261.9h.1M156.6 261.9l.2 .2-.2 .3M156.6 262.5l-.7 .7M156.6 260.9v1.6M157.9 276.8h.1M157.9 276.5l-2.2 3.2"/>
<path d="M157.9 272.4l-2.1 3M157.9 268.2l-2.1 3M158 264l-2.1 3.1M158 260.1l.2 .2M158 260.1v-1.5h-2.2v4.7M158 260.1v.1M158 260.2h.1M158.1 260.2h.1M158.1 260.3h.1M158.2 260.3h.1M158.2 260.3l.4 .4M158.9 260.5l-.3 .2"/>
<path d="M228.8 273.7a2 2 0 0 0-2 2M237.6 270.8v.1M273 268l-28.8 .1M273.1 267h-9.2a3 3 0 0 1-3-3v-74a3 3 0 0 1 3-3h44a3 3 0 0 1 3 3v74a3 3 0 0 1-3 3h-7.6M285.9 269.1v2.3M285.9 273.6v7.3M300.3 268l27.3 .1M334.3 271.5l.4 .6h.8v1.6h7.9l.9 .4 .8 .8 .2 5.6-2.9 5.5-.1 6h-112.8l-.1-6-2.9-5.5 .2-5.6 .7-.8 1-.4h7.9v-1.6h.7l.5-.6M334.3 270.3l-.1 .6M334.3 270.3h.1M343 273.7a2 2 0 0 1 2 2M411 268l5.9 .1"/>
<path d="M411 268l-.2 24h32.5l-.2-11.6M416.5 275.8v16.2M416.6 275.7l-.1 .1M417.3 271.2l-5.1 4.3-1 1.6-.3 1.8M419.6 275.7l-.1-2h13l5 5M429.5 260.7l-10.6 9.1M429.5 260.7l.3 .3h5.2a1.52 1.52 0 0 1 1.5 1.5M436.5 262.2v6.4M437.5 272.1l-19.2 1.7-1.3 .7-.5 1.3M437.5 271.5v20.5M499.1 277.1l.8 6.2 1.3 .5M499.6 277l-.5 .1"/>
<path d="M499.6 277l.7 .3M500 279.1l.3 .3M500 279.1l.2 1.5M500.2 278.6v.1M500.2 278.6l.1 .1M500.2 277.7l-.8-.3 .6 3.7M500.2 278.7l-.2 .4M500.2 278.7l.1 .2M500.3 279.4l.2 1.5M500.3 278.7v.7M500.4 275.9l-1.3 1.2M500.5 275.7l-.1 .2"/>
<path d="M500.6 276.9l-.4 .7v1M500.7 274.5l-.2 1.2M500.8 275.8l-.4 .1M500.8 275.8l-1.2 1.2M500.9 274.1l-.2 .4M501.2 275.2l-.7 .5M501.2 275.2l-.4 .6M501.4 274.1l-.7 .4M501.4 274.1l-.2 1.1M501.4 274l-.5 .1M501.4 274v.1M502 273.1l-1.1 1"/>
<path d="M502.3 277.2l-.9-.1-.7 .2-.4 .6v.8M502.3 277.2h.1M502.3 277.2l26.9 9.5M502.4 273.1h-.4M502.4 273.1l-1 .9M502.4 273.1l2.1 .7M502.5 276.7l-1.1-.2-.8 .4M502.5 276.7l-.2 .5M502.5 276.7l26.8 9.4M502.8 272.9l-.4 .2M502.8 272.9l1.9 .7M502.8 272.9l-.8 .2"/>
<path d="M503.5 275.7h-1.5l-1.4 1.2M503.5 275.7l-1 1M503.5 275.7l26.8 9.5M504.6 273.8l-2 1.8M506.1 273.6v.1M506.1 273.6l-.9-.1-.6 .3M506.1 273.7l-2.3 2.1M506.1 273.7l2.1 .7M507 273.3h.1M507 273.3l-.9 .3M507 273.3l-.9 .4M507 273.3l-1.3-.1-1.1 .6"/>
<path d="M507 273.3l.7 .3M507.3 273.3v.1M507.3 273.4h.1M507.7 273.6h.1M507.7 273.6l.5 .8M507.7 271.5l1 1.3M507.7 271.5l.1 .9 .6 .7M507.8 271.4l-.1 .1M507.8 271.4h.1M507.8 273.6h.1M507.9 273.5l-.1 .1M507.9 273.5h.1"/>
<path d="M508 273.5l.2 .9M508 273.5l-.2 .1M509.4 272.1l-1.5 1.4M509.5 272.1h-.1M510.8 272l-.8-.1-.5 .2M510.8 272l-2.6 2.4M510.8 272l22.8 8M511.5 270.3l-1.3-.3-1.3 .5-.3 .5 .1 .4 1 .5M511.8 270l-1.3-.1-1.3 .2-1.4 1.3M514.9 272.9l.5 .4M515.4 273.3l14.1 5M531.1 277.9l-.7 .4h-.9"/>
<path d="M531.1 277.9v.1M531.1 278l-.8 .3h-.8M548.6 262.1l.2-.5-.4-.5-14.1-4.9h-1.1l-18.1 16.1-.2 .6 .5 .4M548.6 262.1l-17.5 15.8M548.6 262.1h.1M548.6 262.1l-17.5 15.9M548.8 261.6l-.2 .5M553.3 262l1.4 1 .8 1.5M553.3 262l-19.7 18M554.3 261.6l-1 .4M554.3 261.6l1.1 .7 .5 1.1M555.5 264.5l-19.7 18.1"/>
<path d="M555.5 264.5l.6 3.6M555.9 263.4l.7 3.7M555.9 263.4l-.4 1.1M556.1 268.1l-14 13.1M556.1 268.1l.3 .3M556.4 268.4l-13.9 13M556.5 267.4l-.4 .7M556.5 267.4l.4 .3M556.6 267.1h.1M556.6 267.1l-.1 .3M556.6 267.1l.1 .1M556.7 267.2h.1"/>
<path d="M556.7 267.2l.2 .5M556.7 267.2l1 .4M556.9 267.7l-.5 .7M556.9 267.7l.3 .1M557.2 267.8l.9 .7 .5 1M557.2 267.8l-14.6 13.5M557.7 267.6l.8 .6 .4 .7M557.7 267.6l-.5 .2M558.6 271.1l-11.6 11.4M558.6 269.5l-13.5 12.6M558.6 269.5l.2 .9M558.8 270.4l-.2 .7"/>
<path d="M558.8 270.4l-12 11.7M558.9 268.9l-.3 .6M558.9 268.9l.1 1M559 269.9l-.4 1.2M559 269.9l-.2 .5M32.6 292.4a6.4 6.4 0 0 0 5-4.5l.6-.2h2.2l.6 .4 .1 14.7a.93 .93 0 0 1-.7 .7 .93 .93 0 0 1-.9-.3l-7-10zM32.6 280.9l2 .1M34.6 292.2l-2.1 .2M43.2 294.8l.5-.5h48l.5 .5M43.2 292.4l.5 .5h48l.5-.5M43.2 280.8l.5-.5h48l.5 .5M43.9 292.9v1.4"/>
<path d="M57.9 298.3h1.7v.5h-1.4v1.3h1.2v.5h-1.2v1.5h1.4v.6h-1.7zM59.9 298.3h1.7v.5h-1.4v1.3h1.2v.5h-1.2v1.5h1.4v.6h-1.7zM62.5 298.4l.2-.1a.9 .9 0 0 1 1.1 1.1h-.3l-.4-.6-.6 .1a2.75 2.75 0 0 0-.3 2.3l.2 .7 .3 .2 .6-.1 .2-.4h.3a.91 .91 0 0 1-.9 1.1 .91 .91 0 0 1-.9-1v-2.4zM65.6 298.4a1.17 1.17 0 0 1 1.2 .7 1.17 1.17 0 0 1-.3 1.3 1.31 1.31 0 0 1 .3 1.4 1.31 1.31 0 0 1-1 .9l-.5-.5-.1-.5h.2a.6 .6 0 0 0 .6 .5 .6 .6 0 0 0 .6-.5 .74 .74 0 0 0-.7-1.1v-.4a.72 .72 0 0 0 .7-.8 .72 .72 0 0 0-.9-.6l-.3 .5h-.2zM67.7 298.4a1.01 1.01 0 0 1 1.1 .3 1.01 1.01 0 0 1 0 1.2l-1.2 2.3h1.3v.5h-1.7v-.5l1.4-2.7a.57 .57 0 0 0-.5-.8 .57 .57 0 0 0-.6 .6h-.3l.1-.4zM69.2 298.3h1.6v.4h-1.3v1.5l.4-.3a1.61 1.61 0 0 1 .5 2.7l-.2 .1a.91 .91 0 0 1-1-1.1h.3l.1 .3a.65 .65 0 0 0 .9 .2 .65 .65 0 0 0 .2-.9l-.5-.9-1 .4zM71.3 298.3h.2l.7 1.8 .6-1.8h.3l-.8 2.1 .8 2.3h-.3l-.6-1.8-.7 1.8h-.2l.8-2.3zM74.6 298.3h.3v2.5h.4v.6h-.4v1.3h-.3v-1.3h-1.1v-.6zM74.6 299v1.8h-.8zM79.7 298.3h.8l1.4 4.4h-.5l-.4-1.1h-1.8l-.4 1.1h-.6zM80.1 298.6l.8 2.6h-1.6zM91.5 292.9v1.4"/>
<path d="M94.5 287.9l.5-.2h2.2l.5 .2a6.3 6.3 0 0 0 5.1 4.5l.1 .8-7 10a.93 .93 0 0 1-.9 .3 .93 .93 0 0 1-.7-.7v-14.4zM100.8 292.2l2 .2M102.8 280.9l-2 .1M133.7 294.8l.5-.5a.64 .64 0 0 1 .9 .5v3.5h-.3M133.7 280.8l.5-.5a.64 .64 0 0 1 .9 .5v11.6a.64 .64 0 0 1-.9 .5l-.5-.5M134.4 292.9v1.4M134.8 299.9h.3M134.8 299.3h.3M134.8 298.8h.3v2.5h-.3M134.8 299.5h.3M134.8 299h.3M135.1 298.3h-.3v4.4h.3v3a.64 .64 0 0 1-.9 .5l-.5-.5"/>
<path d="M135.1 284.5l.4 .4h1.4M136.8 281.9l-1.7 2.5M136.9 288.4h-1.4l-.4 .3M136.9 290l-2.5 3.6M137.7 292.6l.9 38.7M137.7 293l-2.6 3.7M137.7 297.1l-2.6 3.7M139.8 299.3l1.1 1.1M139.8 296.5l1.1 1.1M139.8 293.7l1.1 1.1M139.8 291l1.1 1.1M139.8 288.2l1.1 1.1"/>
<path d="M139.8 285.4l1.1 1.1M139.8 282.6l1.1 1.1M140.9 280.3h1.7M141 283.2v53.8M141 283.2h.1M141.1 282.9l-.1 .3M141.1 282.9h.1M141.1 282.8v.1M142.6 280.3l.5 .5M142.6 280.3l-1.5 2.5M157.4 297.8l-2.3 3.2M157.5 293.5l-2.3 3.3"/>
<path d="M157.6 289.2l-2.2 3.3M157.7 285l-2.2 3.2M157.9 280.7l-2.3 3.2M273.1 286.4h5.3M273.3 287.5h26.6M273.7 289.7h25.4M285.9 283.2v2.2M285.9 287.7v7.3M293.4 286.4h6.6M299.9 287.5l.5-4.8-.1-16.1a62 62 0 0 0-1.5-16.4l-2-4.6a13.5 13.5 0 0 0-18.8-5.3l-1.8 2-1.1 2.8a107 107 0 0 0-1.1 19v-3.7a37.5 37.5 0 0 0-.9 14.2l-.2 10.9 .9 4.3 1.1 2.2M299.9 287.5l-1.6 4.5M499.9 281.5l.1 .3"/>
<path d="M499.9 281.5l.5 .5M500 281.8l.5 .6M500 281.8l.4 .5M500.1 281.2l.3 .2M500.1 281.2l.4 .5M500.1 280.9l-.2 .6M500.1 280.9v.3M500.1 280.9h.1M500.2 282.2l.1 .8M500.2 280.8l-.1 .1M500.2 280.8h.1M500.2 280.6v.2"/>
<path d="M500.2 280.6l.2 .2M500.3 283l.3 .1M500.4 280.8l.1 .1M500.4 280.8l-.3 .4M500.4 281.4l6.9 2.4M500.4 282v.3M500.4 282l6.4 2.3M500.4 282.3l.1 .1M500.4 282.3l6.2 2.2M500.5 281.7l-.1 .3M500.5 281.7l6.6 2.4M500.5 282.4l6.1 2.1"/>
<path d="M500.5 282.4l.2 .9 .3 .3M500.5 280.9l-.1 .5M500.5 280.9l7.2 2.5M500.6 282.6l-.3 .4M500.8 282.5l.2 1.1M501 283.6l.3 .8M501.1 284v.2M501.1 284l.1 .2M501.1 284.2l.2 .2M501.1 284.2l1.1 2.1 1.9 1.4M501.1 283.9v.1M501.2 283.8l-.1 .1"/>
<path d="M501.3 284.4l.9 1.9 1.8 1.2M504 287.5l.1 .2M504 287.5l2.5 .9M504.1 287.7l2.5 .8M506 285.3l.2 .2M506 285.3l.7 4.4M506.1 285l-.1 .3M506.2 285.5l.7 4.3M506.2 285.5l.8 .3M506.4 285h-.3M506.4 285l-.2 .5M506.4 285l.8 .2"/>
<path d="M506.7 286.6h-.2l.4 2.3M506.7 289.7l.3 .3M506.7 289.7l.2 .1M506.9 289.8l.1 .2M506.9 289.8l.8 .3M506.9 288.9h.2M507 285.8v.2M507 290l.8 .2M507 286l-.4-.2 .1 .8M507 286l.1 .5M507.1 288.9l.1 .9M507.1 286.5l-.4 .1"/>
<path d="M507.2 285.2l-.2 .6M507.2 285.2l.3 .5M507.2 289.8l.5 .1M507.4 286l-.3 .5M507.5 285.7l-.5 .1M507.5 285.7v.2M507.5 288.8l.2 .8M507.5 288.8l-.4 .1M507.5 285.9l-.5 .1M507.5 285.9l.7 .2M507.7 289.6l-.5 .2M507.7 289.9v.2"/>
<path d="M507.7 290.1l.1 .1M507.8 288.5l.1 .9-.2 .2M507.8 288.5l-.4-.1-.5 .5M507.8 288.5l-.3 .3M507.9 289l.8 .3M507.9 284.7l.2 .2M507.9 284.7v.1M507.9 284.7l-.7 .5M507.9 285.6l.2 .1M507.9 289.3l.9 .3M508 285.3l.5 .5M508 285v.3"/>
<path d="M508 285v.2M508.1 285.2h.1M508 285h.1M508.1 285.2v.1M508.1 285.3h-.1M508.1 285.3l.4 .5M508.1 285.3l-.6 .4M508.1 285.7l.1 .4M508.1 284.9l-.1 .1M508.2 290.2h-.4M508.2 285.4l-.7 .5M508.2 284.9l-.2 .1"/>
<path d="M508.2 284.9h.1M508.2 284.9h1.1M508.2 284.9h-.1M508.2 289.9h-.5M508.2 289.9v.1M508.2 290v.2M508.2 290l-.5 .1M508.2 284.8h-.3M508.3 285.6l-.2 .1M508.4 285.7v.2M508.4 285.9l-.2 .2M508.5 287.3l.2 .9"/>
<path d="M508.5 287.3l.4 .2M508.5 285.8l1.6 .5M508.5 285.8l-.1 .1M508.6 289.6l-.4 .3M508.7 288.2l-.4 .3M508.7 289.3l.1 .3M508.8 289.8l.2 .1M508.8 290l.1 .3M508.9 290.3l1.4 .9M508.9 290.3h.1M508.8 290h.1M508.9 290v.3"/>
<path d="M508.9 290h.1M508.9 287.5l.1 .8-.3-.1M508.9 289.1l.1 .4M508.9 289.1l-.2 .2M509 289.5l.2 .3M509 289.5l-.8 .7M509 289.5h.1M509 289.5l-.8 .5M509 289.9l-.1 .1M509 289.9h.1M509 289.5l-.2 .1M509.1 288.1l.4 .5"/>
<path d="M509.1 288.1l.3 .1M509.1 288.2v.1M509.1 288.2l-1.3 .5M509.1 281.7l.2 .1M509.1 281.7l.1 .2M509.2 289.8l-.3 .2M509.2 289.8v.2M509.2 289.3l.2 .3M509.2 290l.9 .3M509.2 290l-.3 .3M509.2 289.7l1.1 .4M509.2 289.7v.1"/>
<path d="M509.2 287.8l-.1 .3M509.2 287.8l.4 .2M509.3 285.2l-1.2 .1M509.3 285.2l6.9 2.5M509.3 281.8l-3.2 3.2M509.3 281.8h.1M509.3 284.9v.3M509.3 284.9l7 2.5M509.4 288.2l.1 .4M509.5 284.8l-1.3 .1M509.5 284.8l6.9 2.5M509.5 284.8l-.2 .1"/>
<path d="M509.5 288.6l-.6 .5M509.5 281.8h-.2M509.5 281.8l1.1 .4M509.5 281.8l-3.1 3.2M509.6 284.7l-1.4 .1M509.6 284.7l6.9 2.4M509.6 288l-.2 .2M509.7 281.3h-.4l-.2 .4M509.7 281.3l-.2 .5M509.7 281.3l1 .3M509.7 286.2l-1.2 1.1M510.1 286.3l-.1-.5 1.1 .4 .1 .5 6.3 2.3"/>
<path d="M510.1 290.3l.1 .5M510.2 286.3l-1.3 1.2M510.3 291.2l6.9 2.5M510.3 290.1l-.2 .2M510.4 286.1l.1 .6M510.4 290.6h.1M510.4 290.6l.9 .3M510.5 286l-.4 .3M510.6 282.2l-2.7 2.6M510.6 290.4l.7 .2M510.7 281.6l-.1 .6M510.8 286.4l.3 .1"/>
<path d="M510.8 286.4l-1.6 1.4M510.8 281.6h-.1M510.8 281.6l.1 .6M510.9 286.1v.1M510.9 282.2h-.3M510.9 282.2l-2.7 2.6M510.9 286.1l-.1 .3M511.1 286.5l-1.5 1.5M511.1 286.5h.1M511.2 290.7l.1 .5-1.1-.4M511.2 290.7l3.4 1.2M511.4 286.8v.4l-2.4 2.3"/>
<path d="M511.4 287.2l.2 .3M511.4 290.5l3.4 1.2M511.4 290.5l-.2 .2M511.5 286.8l.3 .6M511.6 287.5l-2.4 2.3M511.7 287.4h.1M511.7 287.4l-2.5 2.3M511.7 287.4l-.1 .1M511.8 287.4l1 .1M512.2 287.1l.6 .4M512.2 282.1l-1.3 .1M512.2 282.1l7 2.5"/>
<path d="M512.2 282.1l-2.6 2.6M512.4 281.6l-.9-.2-.7 .2M512.4 281.6l-.2 .5M512.4 281.6l7 2.4M512.7 287.8l.1 .5M512.7 287.8l1.1 .4-2.4 2.3M512.7 287.8l-2.4 2.3M512.8 288.3l.6 .3M512.8 288.3l-2.6 2.5M512.9 287.4l-.1 .1M514.6 291.9l.1 .5M514.8 291.7l-.2 .2"/>
<path d="M514.9 292.2l.9 .3M514.9 292.2l-.2 .2M515.1 292l.7 .2M515.7 292.3l.1 .5-1.1-.4M515.7 292.3l2.5 .9M515.9 292.1l2.7 .9M515.9 292.1l-.2 .2M516.2 287.7l1.5 1.1M516.3 287.4l-.1 .3M516.3 287.4l1.7 1.2M516.4 287.3l1.7 1.2M516.4 287.3l-.1 .1"/>
<path d="M516.5 287.1l1 .6 .8 .8M517.2 289.4l.7 .2M517.2 289.4l.1 .5M517.2 289.4l-2.4 2.3M517.3 289.9l.6 .2M517.3 289.9l-2.4 2.3M517.7 288.8l.3 .1M517.7 288.8l-.2 .2M517.9 289.5h.1M517.9 289.5v.2M517.9 288.9h.1M517.9 289.8l.2 .4"/>
<path d="M517.9 289.8l.2 .2M518 288.6v.2M518 288.6l-.3 .2M518 289.5l-.1 .3M518 290.1l-2.1 2M518 288.9l-.5 .1M518 288.8v.1M518.1 290l.6 .2M518.1 290v.2M518.1 288.5v.2M518.1 288.5l-.1 .1M518.1 290.2l.3 .1 .3 .9 .3 1.6h-.2"/>
<path d="M518.1 288.6l.3 .3M518.2 288.6l-.2 .2M518.2 293.2l.3 .3M518.2 289.5h-.2M518.2 289.5l-.1 .5M518.2 289.5l.7 .2M518.3 288.8l-.1 .1M518.3 288.5l.4 .4M518.3 292.4l.1 .3 .4 .2M518.3 292.4l.5 .1M518.4 288.9l-.5 .6M518.4 288.9v.1"/>
<path d="M518.5 293.3l.1 .2M518.5 293.3v.2M518.5 293.1l-.3 .1M518.5 293.5l.3 .3M518.5 293.5l.2 .2M518.5 293.5l-1.3 .2M518.5 293.1h.1M518.6 293l-.1 .1M518.6 293.7h-1.4M518.6 293.5l.1 .2M518.7 293.7l.1 .1M518.7 293.7l.6 .2"/>
<path d="M518.7 288.8l-.7 .7M518.7 288.8v.1M518.7 288.8l-.5 .7M518.7 290.2l.6 3.7M518.7 292.8l-.1 .2M518.8 293.8l.6 .2M518.8 292.8l.1 .8-.3-.1M518.8 292.8l-.1 .2M518.8 292.8l-.3 .5M518.8 291.8l-.5 .6M518.9 289.7l.4 .4M518.9 289.7l-.2 .5"/>
<path d="M518.9 292.4l-.1 .4M519.2 284.6l1 .5 .8 .9M519.2 284.6l-2.7 2.5M519.3 290.1l-.6 .1M519.3 290.1l.6 3.7M519.3 293.9l.1 .1M519.4 284l1.1 .7 1 1M519.4 284l-.2 .6M519.8 294h-.4M519.9 293.8l-.1 .2M519.9 293.8l-.6 .1M520.4 293.4l10.6 3.8"/>
<path d="M520.5 293.3l10.4 3.7M521 286l.4 .3M521 286l-2.7 2.5M521.4 286.3l-2.7 2.6M521.4 286.3l.8 .3M521.5 285.7l.1 .1M521.5 285.7l-.5 .3M521.6 285.8l-.2 .5M521.6 285.8l.8 .2M522.2 286.6l.4 .4M522.2 286.6l-3.3 3.1M522.4 286l.7 .9"/>
<path d="M522.4 286l-.2 .6M522.5 289.9v.4M522.5 290.3l.3 .1M522.6 287l.3 2.2M522.6 287l-3.3 3.1M522.7 289.4l.2 .2M522.7 289.4l-.2 .5M522.8 289.9h-.3M522.8 289.9l8.8 3.1M522.8 289.9v.3M522.8 290.2l.1 .1M522.8 290.2l-.3 .1"/>
<path d="M522.8 290.2l8.8 3.1M522.8 290.3h.1M522.8 290.3v.1M522.9 290.3h-.1M522.9 290.3h.1M522.9 289.6l-.1 .3M522.9 289.6l8.8 3.1M522.9 290.3l8.8 3.1M522.9 290.3l-.1 .1M522.9 289.2l.2 .2M522.9 289.2l-.2 .2M523.1 291.1h.1"/>
<path d="M523.1 289.4l9.2 3.2M523.1 289.4l-.2 .2M523.1 289.4h.1M523.1 286.9l-.5 .1M523.1 286.9l.3 2M523.1 290.4l.1 .4M523.1 291h.1M523.1 291l-3.3 3M523.2 291v.1M523.2 290.8l-.1 .2M523.2 290.8l-3.3 3M523.4 288.9l-.5 .3"/>
<path d="M523.4 288.9l9 3.2M523.4 288.9l-.3 .5M523.7 290.6v.1M523.7 290.7l-.1 .4h-.4M523.7 290.7l-.5 .1M529.2 286.7l1.8 1.2 .9 2M529.3 286.1l2.1 1.5 .7 1.1 .4 1M529.3 286.1l-.1 .6M530.3 285.2l1.4 .8 1.1 1.2 .3 .8-.4 .7M530.3 285.2l-1 .9M530.9 297l.1 .2M531.1 282.4l1.3-.1 1.1 .2"/>
<path d="M531.1 282.4l2.3 .2M531.1 282.4l2 .8M531.6 293v.3M531.6 293.3l.1 .1M531.7 292.7l-.1 .3M531.9 289.9l.2 .7M532.1 290.6l.1 .1M532.2 290.7l.2 1.4M532.3 292.6l.3 .1M532.4 292.1h.3M532.4 292.1l-.1 .5M532.5 289.7l-.6 .2"/>
<path d="M532.5 289.7l.1 .4M532.6 290.1l-.5 .5M532.6 292.7h-.9M532.7 293.4l.2 1.4M532.7 292.1l.5 .1M532.7 292.1l-.1 .6M532.7 288.7l.1 .8-.3 .2M532.7 288.7h.1M532.7 293.4h.2M532.8 288.7l1.3 .5M532.8 289.6l-.8 .4M532.9 295.5l-.1 .8-.3 .6-.8 .2-.8-.1"/>
<path d="M532.9 293.3v.1M532.9 294.8v.7M532.9 290l-.1-.9 1.6 .6 1 5.7-1.7-.6M533 296.9l-.8 .4-1.2-.1M533.1 283.2h.1M533.1 283.2l-2.3 2.2M533.2 283.2l1.4 .9 1.1 1.3M533.2 292.6l-.6 .1M533.2 292.6v.1M533.2 292.2l.4 .2M533.2 292.2v.4M533.2 292.7l-.8 .4-.8-.1"/>
<path d="M533.2 292.7l.1 .3M533.3 293.1l-.8 .3h-.8M533.3 293.1l.1 .1M533.3 293.1h.1M533.3 293l-.8 .4-.9-.1M533.3 293v.1M533.3 290.5l-1.1 .2M533.3 290.5l.3 1.9M533.4 293.2l-.5 .2M533.4 282.6h.1M533.4 282.6l.7 .3M533.4 295.2v.2"/>
<path d="M533.4 294.8l.3 .1M533.4 295.4l-.5 .1M533.4 295.4v.9l-.4 .6M533.5 294.8l-.6 .5 .5-.1M533.5 282.5l1.5 .6M533.5 282.5v.2M533.6 280l1.4 1.1 .8 1.5M533.6 280l-2.5 2.4M533.6 294.8v.1M533.6 292.4l-.4 .3M533.6 292.4l-.4 .2M533.7 292.7l-.4 .4"/>
<path d="M533.7 292.7l-.3 .5M533.7 292.7l.3 1.9M533.7 292.7l-.4 .3M533.7 294.9v.2M533.7 294.9l-.3 .3M533.7 295.1v.1M533.7 295.1l-.3 .3M533.7 295.2l.1 .4M533.8 295.2l2.1 .8M533.8 289.5l-1.2 .6M533.8 295.4h.1M533.8 295.6h.1"/>
<path d="M533.8 295.4l.2 .1M533.9 295.3h-.1M533.9 295.3l-.1 .1M534 294.6l-1.1 .2M534 295.5l-.1 .1M534 282.9h.1M534 282.9l-.8 .3M534 282.9l-.9 .3M534.1 282.9l.3 .1M534.1 289.2l.7 .8M534.2 295.4l-.2 .1M534.3 289.7l-1 .8"/>
<path d="M534.4 295.5l-1.4 1.4M534.4 283l4.3 2.1 .4 .6M534.4 283l1 .8 .6 1M534.4 294.1l.8 .3M534.8 290l1.1 6M535 283.1h.2M535 283.1v.2M535.1 293.6l-1.1 1M535.2 283.1l.4 .2M535.2 283.1v.3M535.4 288l.7 .8M535.4 288l-1.3 1.2"/>
<path d="M535.6 283.3l.1 .3M535.6 283.3l2.6 1.3M535.7 285.4l.2 .3M535.7 285.4l-2.6 2.5M535.8 282.6l-.6 .5M535.9 285.7l-3.1 3M536 284.9l-.3 .5M536 284.9l.3 .1M536 284.8l.3 .2M536 284.8v.1M536.1 288.8l1.1 6M536.1 288.8l-1.3 1.2"/>
<path d="M536.1 287.5l-.7 .5M536.1 287.5l.4 1.1M536.3 285h.1M536.3 285l-.4 .7M536.3 285l2.6 .9M536.4 284.8l-.1 .2M536.4 284.8h.1M536.4 284.8l2.8 1M536.5 284.8l-.3-.2-.2 .2M536.5 288.6l-.4 .2M536.5 288.6l1.1 6M537.2 294.8l-1.3 1.2"/>
<path d="M537.6 294.6l-.4 .2M537.8 286.9l.4 1M537.8 286.9l-1.7 .6M537.8 286.9h.1M537.8 286.9l.8 .8M538.2 284.6l.1 .3M538.2 284.6l.3 .4M538.2 287.9l1.1 6.1M538.2 287.9l-1.7 .7M538.5 285h-.1M538.5 285h.1M538.6 287.7l-.4 .2"/>
<path d="M538.6 287.7l1.1 6M538.6 285h.1M538.6 285l.6 .7M538.9 285.9l.7 .9M538.9 285.9l-1.1 1M539.2 284.3l.1 .4zM539.2 285.8l-.3 .1M539.2 285.8l.5 .5M539.2 285.7h.1M539.3 285.7v.1M539.3 284.7l.5 .1M539.3 294l-1.7 .6"/>
<path d="M539.5 285.7l.1 .1M539.5 285.7l-.1 .1M539.5 285.7h.1M539.6 285.6v.1M539.6 285.6l-.1 .1M539.6 285.8l-.1 .1M539.6 286.8l.1 .3M539.6 286.8l-1 .9M539.6 285.8h.1M539.6 285.8l.1 .4M539.6 285.7l.2 .7M539.6 285.7v.1"/>
<path d="M539.7 283.9l-1.2 1.1M539.7 293.7l-.4 .3M539.7 287.1l.8 4.7M539.7 286.3l.1 .4M539.7 286.3l-.1 .5M539.8 284.8h-.1M539.8 286.7h.1M539.8 286.7l.8 4.4-.1 .7M539.8 286.7l-.1 .4M539.9 285.7h-.3M539.9 285.7l1.1 .4M539.9 285.7l.3 1.6"/>
<path d="M540 285.5l-.4 .1M540 285.5l-.1 .2M540 285.5l.4 .2M540 287.8l.2 .4M540.1 283l1.1 1.3M540.1 283l.2 .8 1 1.3M540.2 287.3h-.2M540.2 287.3v.9M540.2 287.3l1.1 .4M540.2 282.8l-.1 .2M540.2 288.2l.8 .3M540.2 288.2l-.1 .2"/>
<path d="M540.3 282.8h-.1M540.5 291.8l-.5 1.6-.3 .3M540.6 282.4l-2.4 2.2M541 288.5l.9 .2M541 286.1l.3 1.6M541 286h.1M541.2 284.3l.1 .8M541.3 287.7l.7 .2M541.3 287.7l-.3 .8M541.3 282l.8-.5h1l.8 .2 .2 .6-.6 .8-1.4 .3-1-.6zM541.8 281.2l.1 .3M541.8 281.2l-.7 .7"/>
<path d="M541.9 288.7l-1.6 .5M542 287.9l2.3 .5M542 287.9l-.1 .8M542.1 281.2h-.3M542.1 281.2l-.1 .2M542.1 281.2l.1 .2M542.2 281.4h.1M542.8 291.6l.6 .4M543.2 291.9v.1M543.2 292h.1M543.3 292l.1 .1M543.3 292v.1"/>
<path d="M543.4 292.1h.1M543.4 292.1l.1 .1M543.5 292.2h.1M543.5 292.2l.2 .1M543.7 292.3h.1M543.7 292.3h.2M543.7 284.2l-2.5 .1M543.7 284.2l.1 .8M543.8 285l-2.5 .1M543.9 292.3h.1M543.9 292.3h.2M544.1 292.3h.1"/>
<path d="M544.3 288.4l-2.4 .3M544.3 288.4l.4 2.6M544.3 288.4l-3.9 1.2M544.7 291l-4.3 1.3M544.8 292.1h.1M544.9 292h-.1M544.9 292l-.1 .1M545 291.9h.1M545 291.8l-.8 .3-.8-.1M545 291.8h.1M545.1 291.8h.1M545.1 291.8h-.1"/>
<path d="M545.1 291.6h.1M545.2 282.8l-1-1.4-1.2-.1-1.4 .3-1.3 1.2M545.2 282.8l-1.5 1.4M545.2 282.8l.1 .8-1.5 1.4M545.3 290.8v.5l-.3 .5M546 281.8l.3 .3M546 281.8l-.6 .5M546.1 283.7v.1M546.1 283.8l.4 2.6M546.1 283.8l-.4 1.1-1.2 .9-1.8 .5-1.7-.2M546.2 284.7l.3 1.7M546.3 282.1l-.6 .5"/>
<path d="M546.3 282.1l-.1 2.4M546.5 286.4l.4 2.5M546.7 281.8l-.4 .3M546.7 281.8v.4M546.7 281.8l-.2 4.6M546.7 281.7v.1M546.7 281.7l-.2-.2-.5 .3M546.7 281.7l.1 .4M546.7 282.2l.2 .5 .1-.2M546.8 282.1l.2 .4M546.8 282.1l-.1 .1M546.9 288.9l-.6 1.2-1.6 .9"/>
<path d="M547 282.5h.1M547.2 282.3l-.3 6.6M2 309.4h9.6M35 300.4l.4 36.6a2.1 2.1 0 0 0 2.1 2.1h60.4a2.1 2.1 0 0 0 2.1-2.1l.4-36.6M43.2 305.7l.5 .5h48l.5-.5M43.9 306.2v1.4M64.1 300.6h.7v.5h-.7zM91.5 306.2v1.4M134.4 306.2v1.4M134.8 302h.3v.2h-.3M134.8 300.6h.3M134.8 300.9h.3"/>
<path d="M134.8 300.4h.3M134.8 300.2h.3M137.7 301.2l-2.6 3.7M137.8 305.2l-2.1 3M137.8 309.3l-2.1 3M137.9 313.4l-2.1 2.9M137.9 317.4l-2.1 3M139.8 318.7l1.1 1.1M139.8 316l1.1 1.1M139.8 313.2l1.1 1.1M139.8 310.4l1.1 1.1M139.8 307.6l1.1 1.1"/>
<path d="M139.8 304.8l1.1 1.1M139.8 302.1l1.1 1.1M148.8 305.5h2.3M149.9 305.5l-1.1 30M150.6 305.5l2.5 21M156.8 319.2l-2.2 3.2M157 314.9l-2.3 3.2M157.1 310.6l-2.3 3.3M157.2 306.3l-2.3 3.3M157.3 302.1l-2.3 3.2M580.2 310.1h9.5M137.9 321.5l-2 3"/>
<path d="M138 325.6l-2.1 2.9M138 329.6l-2.1 3M139.3 331.9l-3.3 4.7M139.8 335.4l.1 .1M139.8 332.6l1.1 1.1M139.8 329.8l1.1 1.1M139.8 327.1l1.1 1.1M139.8 324.3l1.1 1.1M139.8 321.5l1.1 1.1M139.9 335.1l-2.7 3.8M141.5 337l-1.5 2.1M142.6 335.4l-.7 1"/>
<path d="M145.4 335.5l-2.5 3.6M148.3 335.5l-2.5 3.6M151.2 335.4l-2.6 3.7M153.1 320.9v13.4M154.1 335.5l-2.6 3.6M156.5 332l-2.3 3.3M156.6 327.7l-2.3 3.3M156.7 323.4l-2.2 3.3M231 333.8v18M231 333.8h5.3v18h-5.3M231 333.8l.5 1.5h4.8M231.2 332.3h-2.4a2.01 2.01 0 0 0-2 1.9l-.3 19.1h10a7.2 7.2 0 0 0 7.1 5.7h84.6a7.2 7.2 0 0 0 7.1-5.7h10l-.4-19.1a2.01 2.01 0 0 0-2-1.9h-2.3"/>
<path d="M233.1 335.3v15M239.8 329.7a5.8 5.8 0 0 1 4.1-1.7h84a5.8 5.8 0 0 1 5.7 5.8v18a5.8 5.8 0 0 1-5.7 5.7h-84a5.8 5.8 0 0 1-5.8-5.7v-18a5.7 5.7 0 0 1 1.7-4.1zM240.2 330.1a5.2 5.2 0 0 1 3.7-1.6h84a5.3 5.3 0 0 1 5.2 5.3v18a5.3 5.3 0 0 1-5.2 5.2h-84a5.3 5.3 0 0 1-5.3-5.2v-18a5.2 5.2 0 0 1 1.6-3.7zM247.2 332.7a3 3 0 0 1 3-3h71.4a3 3 0 0 1 3 3M247.8 333.5h6.8v.2M249.9 339.7l-.3 .7-.1 1.6M254.1 333.5l-1 3.6-5 .1-.4-.3-.2-.5-.1 3.3a1.52 1.52 0 0 1 1.5-1.5h4.2l1.5 1.5v1.5v-3.7M254.5 336.8l.1 .7M254.5 336.8h4.6M254.6 337.5h3.5a1.02 1.02 0 0 1 1 1v2.5a1.02 1.02 0 0 1-1 1h-9.8l-.3 .2-.2 .6M254.6 336l-.1 .8M254.6 333.7v2.3"/>
<path d="M254.6 333.7h4.5M259.9 332l.7 .4v2.6a1.02 1.02 0 0 0 1 1h9.5a1.02 1.02 0 0 0 1-1v-1.4M259.9 332l-.8 .4v2.6a1.02 1.02 0 0 1-1 1h-3.5M259.9 337.5v4.5M259.9 332v4M260.6 333.7h11.5M260.6 336.8h11.5M260.9 337.8l.7-.3h9.5a1.02 1.02 0 0 1 1 1v2.5a1.02 1.02 0 0 1-1 1h-9.5a1.02 1.02 0 0 1-1-1v-2.5zM271.9 333.6v-3.1l-.3-.5-.5-.2h3.5l-.5 .2-.2 .5v3.1M271.9 333.6h-.8M271.9 333.6h.2M271.9 331.5h2"/>
<path d="M272.9 333.5l.7 .1M272.9 337.5v4.5M272.9 333.5l-.8 .1M272.9 333.5v2.5M273.6 333.7h11.5M273.6 333.6h.3M273.6 336.8h11.5M273.9 333.6h.7M273.9 337.8l.7-.3h9.5a1.02 1.02 0 0 1 1 1v2.5a1.02 1.02 0 0 1-1 1h-9.5a1.02 1.02 0 0 1-1-1v-2.5zM285.9 332l-.8 .4v2.6a1.02 1.02 0 0 1-1 1h-9.5a1.02 1.02 0 0 1-1-1v-1.4M285.9 332l.7 .4v2.6a1.02 1.02 0 0 0 1 1h9.5a1.02 1.02 0 0 0 1-1v-1.4M285.9 332v4"/>
<path d="M285.9 337.5v4.5M286.6 333.7h11.5M286.6 336.8h11.5M286.9 337.8l.7-.3h9.5a1.02 1.02 0 0 1 1 1v2.5a1.02 1.02 0 0 1-1 1h-9.5a1.02 1.02 0 0 1-1-1v-2.5zM297.9 333.6h-.8M297.9 333.6v-3.1l-.2-.5-.6-.2h3.5l-.5 .2-.2 .5v3.1M297.9 333.6h.2M297.9 331.5h2M298.9 333.5l.7 .1M298.9 337.5v4.5M298.9 333.5l-.8 .1M298.9 333.5v2.5"/>
<path d="M299.6 333.7h11.5M299.6 333.6h.3M299.6 336.8h11.5M299.9 333.6h.7M299.9 337.8l.7-.3h9.5a1.02 1.02 0 0 1 1 1v2.5a1.02 1.02 0 0 1-1 1h-9.5a1.02 1.02 0 0 1-1-1v-2.5zM311.9 332l-.7 .4-.1 2.6a1.02 1.02 0 0 1-1 1h-9.5a1.02 1.02 0 0 1-1-1v-1.4M311.9 332l.7 .4v2.6a1.02 1.02 0 0 0 1.1 1h3.5M311.9 332v4M311.9 337.5v4.5M312.6 333.7h4.5M312.6 336.8h4.6M317.1 333.7v2.3"/>
<path d="M317.2 337.5h-3.5a1.02 1.02 0 0 0-1.1 1v2.5a1.02 1.02 0 0 0 1.1 1h9.8l.3 .2 .1 .6M317.2 336v.8M317.2 336.8v.7M317.7 333.5l1 3.6 4.9 .1 .5-.3 .2-.5v3.3a1.52 1.52 0 0 0-1.5-1.5h-4.1l-1.5 1.5-.1 1.5v-3.7M321.8 339.7l.4 .7v1.6M323.9 333.5h-6.8v.2M338.6 335.3v15M340.8 333.8h-5.3v18h5.3M340.8 333.8l-.6 1.5h-4.7M340.8 333.8v18M45.7 351l1.1-4.7 1.2 4.7M46.1 349.5h1.4"/>
<path d="M50.6 348.7l6.5-1v2zM50.6 348.7h17.1M227.1 353.3v8h23.8l1-1h68l1 1h23.8v-8M229.5 353.3l.3-19.1a2.01 2.01 0 0 1 2-1.9l4.5-.2a7.7 7.7 0 0 1 7.3-5.6h84.6a7.7 7.7 0 0 1 7.2 5.6l4.5 .2a2.01 2.01 0 0 1 2 1.9l.4 19.1M233.1 345.2h3.2M236.3 350.3h-4.8l-.5 1.5M242 352.7h6.2l2.3 1M242.2 355.6l1.4 .3M242.8 350.8l-.1 1.9M243 348.6l-.5 .1-.4 .6-.1 4.7M243 348.6l-.8 .6-.1 1.6h6.1l2.4-1M243.2 355.8h2.5"/>
<path d="M245.8 352.7l.8 .3 .2 .7M246.5 350.6l-.5 .2M247 347.8a.9 .9 0 0 1-1 .8h-3M247.7 348.8l.1 .5 .4 .2h75.4l.3-.2 .1-.5M247.8 342.8l.2 .5 .3 .2h9.8a1.02 1.02 0 0 1 1 1v2.5a1.02 1.02 0 0 1-1 1h-9.9l-.3 .2-.2 .6M247.8 342.8h11.3M249.5 343.5l-.1 4.5M259.5 348.5l-1.3 .3h-10.5M259.9 343.5v4.5M260.3 348.5l1.3 .3h9.6l1.3-.3M260.6 342.8h11.5M260.9 343.8l.7-.3h9.5a1.02 1.02 0 0 1 1 1v2.5a1.02 1.02 0 0 1-1 1h-9.5a1.02 1.02 0 0 1-1-1v-2.5z"/>
<path d="M272.2 354h2h-.3v1.3l.3 .3h-2l.2-.4v-1.2zM272.4 354.8l-.2 .2h-21.7M272.9 343.5v4.5M273.3 348.5l1.3 .3h9.6l1.3-.3M273.6 342.8h11.5M273.9 343.8l.7-.3h9.5a1.02 1.02 0 0 1 1 1v2.5a1.02 1.02 0 0 1-1 1h-9.5a1.02 1.02 0 0 1-1-1v-2.5zM273.9 354.8l.3 .2h10.7M278.4 355.9h-34.5a4.2 4.2 0 0 1-4.5-4.1v-18a4.2 4.2 0 0 1 4.5-4.2h84a4.2 4.2 0 0 1 4.5 4.2v18a4.3 4.3 0 0 1-4.5 4.1h-34.5M278.4 357v-1.3l7.5-.1 7.5 .1v1.3M278.4 356.7h15M283.4 356.7h5M284.9 352.3h2v2.8h-2z"/>
<path d="M285.9 343.5v4.5M286.3 348.5l1.3 .3h9.6l1.3-.3M286.6 342.8h11.5M286.9 343.8l.7-.3h9.5a1.02 1.02 0 0 1 1 1v2.5a1.02 1.02 0 0 1-1 1h-9.5a1.02 1.02 0 0 1-1-1v-2.5zM297.6 354h2h-.3v1.3l.3 .3h-2l.2-.4v-1.2zM297.8 354.8l-.2 .2h-10.7M298.9 343.5v4.5M299.3 348.5l1.3 .3h9.6l1.3-.3M299.3 354.8l.3 .2h21.6M299.6 342.8h11.5M299.9 343.8l.7-.3h9.5a1.02 1.02 0 0 1 1 1v2.5a1.02 1.02 0 0 1-1 1h-9.5a1.02 1.02 0 0 1-1-1v-2.5zM311.9 343.5v4.5"/>
<path d="M312.3 348.5l1.2 .3h10.5M312.6 342.8h11.3M322.3 343.5v4.5M323.9 342.8l-.1 .5-.3 .2h-9.8a1.02 1.02 0 0 0-1.1 1v2.5a1.02 1.02 0 0 0 1.1 1h9.9l.3 .2 .1 .6M324.8 347.8a.9 .9 0 0 0 1 .8h2.9l.7 .3 .3 .7v3.1h-6.1l-2.4 1M324.8 349.8a1 1 0 0 0 1 1M325.9 352.7l-.7 .3-.3 .7M329 350.8v1.9M329.1 355.7l-3.1 .1M329.6 355.6l-1.4 .3M329.7 349.6v1.2h-6.2l-2.3-1M335.5 350.3h4.7l.6 1.5"/>
<path d="M335.5 345.2h3.1M428.1 357.2v50.8M472.2 357.2v44.5M580.2 357.2h-229.5v50.8M350.7 377.2h38.8M350.8 368.2h77.3M389.6 368.2v39.8M406.7 378.8h1.7M406.7 379.7h1.7M407.5 378v1.7M428.1 376.3h44.1M428.1 369.9h152.1"/>
<path d="M428.1 363.6h44.1M495.8 363.3l.6-.3h6.6a.95 .95 0 0 1 .9 .9 .95 .95 0 0 1-.8 1l-6.7 .1a.95 .95 0 0 1-.8-.6 .95 .95 0 0 1 .2-1.1zM496.4 365l6.7-.1zM497.7 365.7l.7-.2h6.5a.95 .95 0 0 1 1 .8 .95 .95 0 0 1-.9 1l-6.6 .1a.95 .95 0 0 1-.9-.6 .95 .95 0 0 1 .2-1.1zM498.4 367.4l6.6-.1zM499 360.9l.6-.3h6.6a.95 .95 0 0 1 .9 .9 .95 .95 0 0 1-.8 1h-6.7a.95 .95 0 0 1-.8-.5 .95 .95 0 0 1 .2-1.1zM499.6 362.5h6.7zM503.1 364.9l-6.7 .1a.95 .95 0 0 1-.9-1 .95 .95 0 0 1 .9-1h6.6a.95 .95 0 0 1 .9 1 .95 .95 0 0 1-.9 1M505 367.4h-6.6a.95 .95 0 0 1-1-1 .95 .95 0 0 1 1-.9h6.5a.95 .95 0 0 1 1 .9 .95 .95 0 0 1-1 1M506.3 362.5h-6.7a.95 .95 0 0 1-.9-.9 .95 .95 0 0 1 .9-1h6.6a.95 .95 0 0 1 .9 1 .95 .95 0 0 1-.9 .9M508.9 360.6h5.8l-.4 1.5h-2.1l-1.4 5.3h-1.7l1.4-5.3h-2zM515.2 360.6h5.3l-.4 1.5h-3.6l-3.1 5.3z"/>
<path d="M515.2 360.6h5.3l-.4 1.5h-3.6l-.3 1.2h3.2l-.3 1.3h-3.3l-.3 1.3h3.6l-.4 1.5h-5.3zM515.8 364.6l-.3 1.3h3.6l-.4 1.5h-5.3zM516.5 362.1l-.3 1.2h3.2l-.3 1.3h-3.3l-2.4 2.8zM350.7 394.7h77.5M366.2 386h2.9M369.6 386h1.1M370.2 382v2.9M370.2 385.4v1.1M370.2 387v2.9M371.2 386h2.9M374.6 386h1.9M375.7 384.3l12.2-1.4v6.1l-12.2-1.4z"/>
<path d="M377 386h1.1M378.6 386h5.8M384.9 386h1M386.5 386h2.2M406.7 390.7h1.7M406.7 387.7h1.7M406.7 384.8h1.7M406.7 381.8h1.7M406.7 391.6h1.7M406.7 388.6h1.7M406.7 385.6h1.7M406.7 382.6h1.7"/>
<path d="M407.5 380.9v1.7M407.5 383.9v1.7M407.5 386.9v1.7M407.5 389.9v1.7M416.3 393.4h1.7M416.3 394.2h1.7M417.1 392.5v1.7M428.1 385.6h44.1M428.1 394.9h44.1M472.2 389h108M482 389v12.7M499.1 389v12.7"/>
<path d="M500.4 395.5l.8-.5 1.2-.1 .8 .2 .7 .7 .3 .8h-1l-.5-.7-.8-.2-.8 .4-.3 .8 .1 1.5 .7 .8h1l.6-.8h1l-.2 .8-.7 .7-.8 .3h-.9l-.8-.3-.7-.7-.5-1.9 .3-1.1zM504.8 397.2h2.8v.9h-2.8zM295.9 408v4.4M428.1 401.7h152.1M428.3 401.9h86.5v5.9h-86.5zM515 401.7v6.3M536.2 401.7v6.3M565.6 401.7v6.3"/>
<circle cx="17.4" cy="15.8" r="2.03"/>
<circle cx="32.1" cy="136.8" r="2.59"/>
<circle cx="103.2" cy="136.8" r="2.59"/>
<circle cx="72.1" cy="152.8" r=".35"/>
<circle cx="75" cy="152.8" r=".35"/>
<circle cx="92.2" cy="155.9" r="1.05"/>
<circle cx="92.2" cy="155.9" r=".78"/>
<circle cx="60.3" cy="209" r=".8"/>
<circle cx="60.3" cy="213.9" r=".8"/>
<circle cx="63.3" cy="213.9" r=".8"/>
<circle cx="63.3" cy="209" r=".8"/>
<circle cx="66.2" cy="209" r=".8"/>
<circle cx="66.2" cy="213.9" r=".8"/>
<circle cx="69.2" cy="209" r=".8"/>
<circle cx="69.2" cy="213.9" r=".8"/>
<circle cx="72.1" cy="209" r=".8"/>
<circle cx="72.1" cy="213.9" r=".8"/>
<circle cx="75" cy="209" r=".8"/>
<circle cx="75" cy="213.9" r=".8"/>
<circle cx="235.1" cy="253" r="3.7"/>
<circle cx="285.9" cy="253" r="2.5"/>
<circle cx="336.7" cy="253" r="3.7"/>
<circle cx="32.1" cy="286.6" r="2.59"/>
<circle cx="67.7" cy="286.6" r="1.75"/>
<circle cx="103.2" cy="286.6" r="2.59"/>
<circle cx="50.9" cy="300.3" r="3.5"/>
<circle cx="370.2" cy="386" r="3"/>
<circle cx="370.2" cy="386" r="1.66"/>
</g>
<path d="M105.6 93.1h-78.4M67.7 348.7v-105.5" fill="none" stroke="#000" stroke-width=".32" stroke-dasharray="5.9 1.8 .6 1.2 .6 1.8" stroke-linecap="butt"/>
<!-- layer: 02___PRT_ALL_AXES -->
<g fill="none" stroke="#000" stroke-width=".32">
<path d="M33.5 48.9h-7v1.1h11.2v-1.1M41.2 48.2h2M41.2 47.4h2M41.8 47l-.6 .2v1.1l.6 .2h2.7l.6-.2v-1.1l-.6-.2M42 47h2.3M43.2 47.4h1.9M43.2 48.2h1.9M43.2 47.4v.8M90.2 48.2h2M90.2 47.4h2M90.8 47l-.6 .2v1.1l.6 .2h2.7l.6-.2v-1.1l-.6-.2M91 47h2.3"/>
<path d="M92.2 47.4h1.9M92.2 48.2h1.9M92.2 47.4v.8M97.6 48.9v1.1h11.2v-1.1h-6.9M237.8 53.7v7.6M375.3 53.7v8.3M237.8 63.6v2.3M237.8 68.1v7.6M237.8 78v2.3M375.3 64.3v2.3M375.3 68.8v8.3M375.3 79.4v2.3"/>
<path d="M237.8 82.5v7.6M237.8 92.4v2.3M237.8 96.9v7.6M375.3 83.9v8.3M375.3 94.5v2.2M375.3 99v8.3M237.8 106.8v2.3M237.8 111.3v7.6M375.3 109.6v2.2M375.3 114.1v8.3M237.8 121.2v2.2M237.8 125.7v7.6"/>
<path d="M346.7 124.8h8.1M350.8 120.7v8.1M375.3 124.7v2.2M375.3 129.2v8.3M395.7 124.8h8.1M399.8 120.7v8.1M495.8 121l-.6 .6-.9-.1M495.8 121l-.9-.1-.6 .6M495.8 121h.1M495.8 121l-.3-.7h-.8l-.6 .6 .2 .6M533.9 123.9h.1M535.4 123.3h-.9l-.6 .6"/>
<path d="M535.4 123.3l-.6 .7-.9-.1M535.4 123.3l-.3-.6h-.8l-.6 .6 .2 .6M72 156.9l-.1 .1M72.1 152.5h-.1M75 156.9l-.3 .4M75 152.5h-.1M90.2 154.8l2-1.1 1.9 1.1v2.2l-1.9 1.2-2-1.2zM144.2 269.6l-.1 .1M507.2 272.8l.4 .8M507.2 272.8l.1 .6M507.3 273.4h.1M507.3 273.4v.1"/>
<path d="M507.7 271.5l-.5 1.3M507.7 271.5h.1M507.8 271.4l-.1 .1M539.7 284.2l.1 .6M539.8 284.8h.1M540.1 282.9l-.4 1.3M540.1 282.9h.1M540.2 282.9h-.1M544.6 281.9l1 .5 .4 .8M546 283.2l.1 .5M546 283.2l-.1 .7-.6 .8-1 .6-1.2 .3-2.3-.2-.7-.4-.4-.8M546.1 283.7v.1"/>
<path d="M546.1 283.8h.1M546.1 283.8l-.2 .7-.6 .7-2.1 .9-2.3-.1-.7-.5-.4-.7"/>
<circle cx="509.5" cy="119.8" r=".28"/>
<circle cx="511.8" cy="119.9" r=".29"/>
<circle cx="211.2" cy="121.7" r=".36"/>
<circle cx="211.2" cy="126.1" r=".36"/>
<circle cx="214.2" cy="121.7" r=".36"/>
<circle cx="214.2" cy="126.1" r=".36"/>
<circle cx="217.1" cy="121.7" r=".36"/>
<circle cx="217.1" cy="126.1" r=".36"/>
<circle cx="220" cy="121.7" r=".36"/>
<circle cx="220" cy="126.1" r=".36"/>
<circle cx="223" cy="121.7" r=".36"/>
<circle cx="223" cy="126.1" r=".36"/>
<circle cx="225.9" cy="121.7" r=".36"/>
<circle cx="225.9" cy="126.1" r=".36"/>
<circle cx="237.8" cy="124.8" r="1.05"/>
<circle cx="249.7" cy="121.7" r=".36"/>
<circle cx="249.7" cy="126.1" r=".36"/>
<circle cx="252.7" cy="121.7" r=".36"/>
<circle cx="252.7" cy="126.1" r=".36"/>
<circle cx="255.6" cy="121.7" r=".36"/>
<circle cx="255.6" cy="126.1" r=".36"/>
<circle cx="258.5" cy="121.7" r=".36"/>
<circle cx="258.5" cy="126.1" r=".36"/>
<circle cx="261.5" cy="121.7" r=".36"/>
<circle cx="261.5" cy="126.1" r=".36"/>
<circle cx="264.4" cy="121.7" r=".36"/>
<circle cx="264.4" cy="126.1" r=".36"/>
<circle cx="350.8" cy="124.8" r="1.05"/>
<circle cx="367.9" cy="121.7" r=".36"/>
<circle cx="367.9" cy="126.1" r=".36"/>
<circle cx="370.9" cy="121.7" r=".36"/>
<circle cx="370.9" cy="126.1" r=".36"/>
<circle cx="373.8" cy="121.7" r=".36"/>
<circle cx="373.8" cy="126.1" r=".36"/>
<circle cx="376.7" cy="121.7" r=".36"/>
<circle cx="376.7" cy="126.1" r=".36"/>
<circle cx="379.7" cy="121.7" r=".36"/>
<circle cx="379.7" cy="126.1" r=".36"/>
<circle cx="382.6" cy="121.7" r=".36"/>
<circle cx="382.6" cy="126.1" r=".36"/>
<circle cx="399.8" cy="124.8" r="1.05"/>
<circle cx="508.5" cy="122.8" r=".29"/>
<circle cx="510.9" cy="122.9" r=".29"/>
<circle cx="513.3" cy="123" r=".29"/>
<circle cx="514.2" cy="120" r=".29"/>
<circle cx="515.6" cy="123.2" r=".28"/>
<circle cx="516.6" cy="120.2" r=".28"/>
<circle cx="518" cy="123.3" r=".28"/>
<circle cx="519" cy="120.3" r=".28"/>
<circle cx="520.4" cy="123.5" r=".28"/>
<circle cx="521.3" cy="120.5" r=".28"/>
<circle cx="92.2" cy="155.9" r="1.35"/>
<circle cx="32.1" cy="286.6" r="2.5"/>
</g>
<!-- layer: AXES -->
<g fill="none" stroke="#000" stroke-width=".32">
<path d="M74.7 168.1l.2 .5M75.4 168.1l-.3 .5M526.7 211.6h.1M145.5 255.3v4.9M146.2 255.3v4.9M150.5 255.3v4.9M151.2 255.3v4.9M517.9 288.9h.1M518.3 288.8l-.4 .1"/>
<circle cx="60.3" cy="213.9" r=".35"/>
<circle cx="60.3" cy="209" r=".35"/>
<circle cx="63.3" cy="213.9" r=".35"/>
<circle cx="63.3" cy="209" r=".35"/>
<circle cx="66.2" cy="209" r=".35"/>
<circle cx="66.2" cy="213.9" r=".35"/>
<circle cx="69.2" cy="213.9" r=".35"/>
<circle cx="69.2" cy="209" r=".35"/>
<circle cx="72.1" cy="213.9" r=".35"/>
<circle cx="72.1" cy="209" r=".35"/>
<circle cx="75" cy="213.9" r=".35"/>
<circle cx="75" cy="209" r=".35"/>
</g>
<!-- layer: COSMETIC -->
<path d="M511.4 282.5l.8-1.3 .7-.4h2M514.9 280.8l2 .7 2.1 1.6" fill="none" stroke="#000" stroke-width=".32" stroke-dasharray="5.9 1.8 .6 1.2 .6 1.8" stroke-linecap="butt"/>
<!-- layer: COSMETIC_SKETCH -->
<g fill="none" stroke="#000" stroke-width=".32">
<path d="M213.1 56.7h49.4l4.2 4.2v66.9h-21v-8.4h18.2v-60.6h-25.4v4.9h-1.4v-4.9h-25.4v60.6h18.2v8.4h-21v-66.9zM216 56.7l-2.1 2.1M220.2 56.7l-2.1 2.1M224.4 56.7l-2.1 2.1M228.6 56.7l-2.1 2.1M232.8 56.7l-2.1 2.1M237 56.7l-2.1 2.1M238.5 59.4l-1.4 1.4M241.2 56.7l-2.1 2.1M245.4 56.7l-2.1 2.1M249.6 56.7l-2.1 2.1M253.8 56.7l-2.1 2.1"/>
<path d="M258 56.7l-2.1 2.1M262.2 56.7l-2.1 2.1M264.5 58.7l-.6 .5M349.2 59.4l-2.8 2.8M350.6 56.7h49.4l4.2 4.2v66.9h-8.4v-6.3h5.6v-62.7h-25.4v4.9h-1.4v-4.9h-25.4v62.7h5.6v6.3h-8.4v-66.9zM351.9 56.7l-2.1 2.1M356.1 56.7l-2.1 2.1M360.3 56.7l-2.1 2.1M364.5 56.7l-2.1 2.1M368.7 56.7l-2.1 2.1M372.9 56.7l-2.1 2.1M377.1 56.7l-2.5 2.5"/>
<path d="M381.3 56.7l-2.1 2.1M385.5 56.7l-2.1 2.1M389.7 56.7l-2.1 2.1M393.9 56.7l-2.1 2.1M398.1 56.7l-2.1 2.1M401.1 57.9l-.9 .9M403.2 60l-1.8 1.9M211.7 61l-2.8 2.8M211.7 65.2l-2.8 2.8M211.7 69.4l-2.8 2.8M211.7 73.6l-2.8 2.8M211.7 77.8l-2.8 2.8"/>
<path d="M238.5 63.6l-.1 .1M266.6 60.8l-2.7 2.6M266.7 64.8l-2.8 2.8M266.7 69l-2.8 2.8M266.7 73.2l-2.8 2.8M266.7 77.4l-2.8 2.8M349.2 63.6l-2.8 2.8M349.2 67.8l-2.8 2.8M349.2 72l-2.8 2.8M349.2 76.2l-2.8 2.8M376 62l-1.4 1.4M404.2 63.3l-2.8 2.8"/>
<path d="M404.2 67.5l-2.8 2.8M404.2 71.7l-2.8 2.8M404.2 75.9l-2.8 2.8M509.4 70.5l33.9 2.1-6.6 20.3 3.9 .2-6.1 18.9-41.8-2.5 6.1-18.9 4 .2zM549 77.4h.1M549 77.4l2.5 3-14.1 45.2-6.8-.4 1.4-4.2 4.5 .2 13-42.3M549.4 77.9l-.2 .1M550.3 79l-1 1M211.7 82l-2.8 2.8M211.7 86.2l-2.8 2.8M211.7 90.4l-2.8 2.8M211.7 94.6l-2.8 2.8"/>
<path d="M211.7 98.8l-2.8 2.8M266.7 81.6l-2.8 2.8M266.7 85.8l-2.8 2.8M266.7 90l-2.8 2.8M266.7 94.2l-2.8 2.8M266.7 98.4l-2.8 2.8M349.2 80.4l-2.8 2.8M349.2 84.6l-2.8 2.8M349.2 88.8l-2.8 2.8M349.2 93l-2.8 2.8M349.2 97.2l-2.8 2.8M404.2 80.1l-2.8 2.8"/>
<path d="M404.2 84.3l-2.8 2.8M404.2 88.5l-2.8 2.8M404.2 92.7l-2.8 2.8M404.2 96.9l-2.8 2.8M546 98l-3.3 3.4M547 95l-3.4 3.3M547.9 91.9l-3.3 3.4M548.9 88.9l-3.4 3.3M549.8 85.8l-3.3 3.4M550.8 82.8l-3.4 3.3M551.3 80.2l-2.9 2.9M211.7 103l-2.8 2.8"/>
<path d="M211.7 107.2l-2.8 2.8M211.7 111.4l-2.8 2.8M211.7 115.6l-2.8 2.8M212.1 119.4l-3.2 3.2M216.3 119.4l-7.4 7.4M220.5 119.4l-8.4 8.4M224.7 119.4l-8.4 8.4M228.9 119.4l-8.4 8.4M230.7 119.6v2.1M232 120l.3-.4 .5 .4-.8 1.7h.8M243.9 119.8v2.1M249.9 119.4l-4.2 4.2"/>
<path d="M254.1 119.4l-8.4 8.4M258.3 119.4l-8.4 8.4M262.5 119.4l-8.4 8.4M266.7 102.6l-2.8 2.8M266.7 106.8l-2.8 2.8M266.7 111l-2.8 2.8M266.7 115.2l-2.8 2.8M266.7 119.4l-8.4 8.4M349.2 101.4l-2.8 2.8M349.2 105.6l-2.8 2.8M349.2 109.8l-2.8 2.8M349.2 114l-2.8 2.8"/>
<path d="M349.2 118.2l-2.8 2.8M369 119.4l-4.2 4.2M373.2 119.4l-8.4 8.4M377.4 119.4l-8.4 8.4M381.6 119.4l-8.4 8.4M385.8 119.4v8.4h-21M385.8 119.4h-21v8.4M385.8 119.4l-8.4 8.4M404.2 101.1l-2.8 2.8M404.2 105.3l-2.8 2.8M404.2 109.5l-2.8 2.8M404.2 113.7l-2.8 2.8"/>
<path d="M404.2 117.9l-2.8 2.8M493.9 112.7l-3.1 10.1 6.7 .4 1.4-4.2-4.6-.3 .8-2.6M494.3 114l-1.2 1.2M494.6 118l-3.4 3.3M494.9 115.5l-2.7 2.7M495.8 118.8l-4.1 4.1M497.8 118.9l-4.1 4.1M505.6 119h.7l-.8 1.4M507.4 118l16.9 1.1-1.7 5.6-17-1zM509.1 118.1l-2.5 2.6M511.1 118.3l-5.5 5.4M513 118.4l-5.4 5.4"/>
<path d="M515 118.5l-5.4 5.5M517 118.6l-5.4 5.5M519 118.7l-5.5 5.5M521 118.9l-5.5 5.4M522.9 119l-5.4 5.4M524.1 120l-4.6 4.6M525.1 119.7l-.4 1.5M539.4 119.3l-6.1 6.1M540.3 116.3l-3.3 3.3M541.3 113.2l-3.4 3.4M542.2 110.2l-3.3 3.3M543.2 107.1l-3.4 3.4"/>
<path d="M544.1 104.1l-3.3 3.3M545.1 101.1l-3.4 3.3M207.1 120.8h.9l-.5 2.1M207.9 125.8l-.4-.4-.2 .2-.2 1.2M229.9 122.6l-5.2 5.2M229.9 126.8l-1 1M231.3 125v2.1M233.6 121.5h8.4v6.3h-8.4zM235.2 121.5l-1.6 1.6M239.4 121.5l-5.8 5.8M242 123.1l-4.7 4.7M242 127.3l-.5 .5"/>
<path d="M243.2 125v2.1M244.5 125.4l.3-.4 .5 .4-.8 1.7h.8M266.7 123.6l-4.2 4.2M267.5 125.2h.8l-.4 2.1M268.4 121.1l-.3-.3-.2 .1-.2 1.3M350.1 121.5l-3.7 3.7M354.3 121.5l-6.3 6.3M354.8 125.2l-2.6 2.6M363 121h.8l-.4 2.1M363.9 125.3l-.4-.3-.2 .1-.2 1.3M385.8 123.6l-4.2 4.2M387 120.4v2.1"/>
<path d="M387.6 124.7v2.1M388.3 120.7l.3-.3 .5 .3-.8 1.8h.8M396.3 121.5l-.5 .6M400.5 121.5l-4.7 4.8M404.2 122.1l-5.8 5.7M404.2 126.3l-1.6 1.5M498.4 120.4l-2.7 2.7M504.7 122.4h.6l-.5 .7-.2-.2zM505.4 122l-.2-.3-.2 .1-.4 .8M523.1 123l-1.6 1.7M524.7 122.7l-.4 1.4M526.1 120l.5-.2 .2 .3-1.1 1.1 .7 .1"/>
<path d="M533.5 121.1l-2.2 2.2M535.4 121.2l-4 4.1M537.5 125.4l-.2 .2M538.4 122.4l-3.1 3.1M71.4 150.6h6.8v7.1M78.2 154.8l-.8 .8M79.4 151.5v2.1M80.1 155.8v2.1M80.7 151.9l.3-.4 .5 .4-.8 1.7h.8M93.8 144.1v8.6h-5.6v6.3h.6M96.6 146.5v12.5h-1M96.6 153.2l-1.1 1.1"/>
<path d="M504.8 204.9l.7 .4h-.6M505 205.1l.1 .2M509 205.9l.4 .2 .2 .5-.5-.2zM509 206.1l.5 .1M509 206.3l.6 .1M509.2 206.1l.1 .3M510.6 208.1l-8.1 .5M517.3 204.9l-.1 .4 .3 .6 1.1 .9M517.3 205.5l.1 .1M517.3 205.5h.1M517.4 205.5h-.1M517.4 205.5h.1"/>
<path d="M517.4 205.5v.1M517.4 205.6h.1M517.5 205.6h-.1M517.5 205.5l.1 .2M517.5 205.5v.1M517.5 204.9v.2M517.5 205.3l-.2-.2 .3 .2M517.5 205v.1M517.6 206h.1M517.6 205.9v.1M517.6 205l.1 .2M517.6 206l.1 .1"/>
<path d="M517.6 205.9l.1 .1M517.6 205.7h.1M517.6 205.2h.1M517.7 205.4l.6 .1 .2 .7-.6-.2zM517.7 205.2h.1M517.7 206h.1M517.7 205.9l.1 .1M517.7 205.6l.3 .3M517.8 205h.1M517.8 205l.1 .2M517.8 204.9v.1M517.8 204.9l.1 .1"/>
<path d="M517.8 205.1h.1M517.9 205h.1M517.9 205.6l-.1 .3M517.9 205.1h.1M518 205.1v.1M518 205.2h-.1M518 205.4l.3 .8zM518 206.2v.2M518.2 205.1v.3M518.2 206.3l.1 .1M518.3 206.5v.1M518.3 206.5h.1"/>
<path d="M518.3 206.4v.1M518.3 205.7l.2 .4M518.3 206.6h.1M518.4 206.4l.1 .3M518.4 205.8v.2M518.4 205.5v.1M518.5 205.6h.1M518.5 205.5h-.1M518.5 205.6v.1M518.5 206.4l.2 .2M518.5 205.7h.1M518.6 205.5h-.1"/>
<path d="M518.6 205.6h.1M518.6 206.3l.2 .3M518.6 205.6v.1M518.6 205.5h.1M518.6 205.9l.2 .1M518.6 205.5l.1 .1M518.6 206.2l.1 .1M518.6 205.9h.1M518.7 206.3h.1M518.7 205.9h-.1M518.7 206.1l.2 .3M518.7 205.6h.1"/>
<path d="M518.7 206.3l.1 .1M518.7 206h.1M518.8 205.9l-.1 .1M518.8 205.9h.1M518.8 206.4h.1M518.8 205.9l.1 .1M518.9 206h.1M518.9 206.4h.1M518.9 206h-.1M520.2 213.9l.5 .1 .2 .5-.5-.1zM520.3 214l.4 .2M520.3 214.2l.5 .2"/>
<path d="M520.5 214.1l.1 .2M525.1 215.4l.5 .3-.3-.3M525.1 215.3l.2 .1M525.1 215.3v.1M525.3 215.4l.1 .2M49 298.8l-.3 .5-.5-.8 1 .6M49.5 297.4l-.3 .2 .2 .2a.34 .34 0 0 1 .5 .2 .34 .34 0 0 1-.3 .5l-.1-.1M49.5 299.7l.5 1.1M50 299.7l-.5 1.1M50.9 298.9l.5 .9h-.3v1.7h-.4v-1.7h-.4zM51 297.2h-.3l-.1 .6M51.8 299.7l.5 1.1"/>
<path d="M52.3 299.7l-.5 1.1M52.3 297.4l.4 .2-.8 .8M53.2 298.8h-.4l-.1 .4 .4 .1 .2-.4M53.2 298.8l.1-.2h.3v.3h-.3M53.2 298.8l.1 .1M511.3 286.4l.7 .3h-.7M511.5 286.5l.1 .2M48.2 300.2l-.4-.1v.3M48.2 300.2v.1M48.2 300.2l.2-.3 .3 .2-.1 .4M49 301.1l.2 .4h-1l-.1 .3 .3 .1M49.8 302l-.5 1"/>
<path d="M50.5 302.3h.2l-.1 1.1M50.6 303.4h.1M50.7 303.2l-.1 .2M51.1 302.3v1.1M51.7 302.2l.5 .9M52.2 301.9l.5 1M52.6 301.5l.9 .6zM52.8 301.1l1 .5M53.2 300.1l-.1 .3 .6 .1"/>
<circle cx="207.6" cy="126.9" r=".49"/>
<circle cx="268.1" cy="122.2" r=".49"/>
<circle cx="363.6" cy="126.4" r=".49"/>
<circle cx="50.9" cy="297.9" r=".26"/>
<circle cx="50.9" cy="300.2" r="1.75"/>
<circle cx="53.7" cy="300.2" r=".26"/>
</g>
<g fill="none" stroke="#000" stroke-width=".32" stroke-dasharray="2.3 2.3 6.8 2.3" stroke-linecap="butt">
<path d="M501.4 205.3l.3 1.6M501.4 205.1v.2M501.7 203.9l-.3 1.2M501.7 206.9l1.2 2.3 2.7 3 2.2 1.2 1.9 .4M509.4 206.4l-2-1.9-2.2-1.3-1.9-.3-.8 .2-.8 .8M509.5 206.5l-.1-.1M509.7 213.8l1.4-.6 .6-1.4M510 207.1l-.5-.6M510.1 207.3l-.1-.2M510.6 208l-.5-.7M511.4 209.8l-.8-1.8M511.7 211.8v-.2"/>
<path d="M511.7 211.6l-.3-1.8M517.4 209.4l.2 2.2M517.6 208.7l-.2 .7M517.6 211.6l1.2 2.3 2.7 3 2.2 1.3 2 .3M522.7 208.8l-2-1-1.1-.2-.9 .1-1.1 1M522.9 208.9l-.2-.1M523.4 209.3l-.5-.4M525.4 211.2l-2-1.9M525.7 218.5l1.3-.5 .6-1.5M527.3 214.5l-.7-1.6-1.2-1.7M527.6 216.5v-.1M527.6 216.4l-.3-1.9"/>
</g>
<!-- layer: CURVES -->
<g fill="none" stroke="#000" stroke-width=".32">
<path d="M75.6 167.5h2.1M77.3 168.1h.9M57.2 209.4v4.1M57.2 214.1l.2 .8 .6 1.1M58 206.9l-.6 1.1-.2 .8M59.7 206.9a2.06 2.06 0 0 0-2 2.1v4.9a2.06 2.06 0 0 0 2 2.1M75.6 206.9a2.06 2.06 0 0 1 2.1 2.1v4.9a2.06 2.06 0 0 1-2.1 2.1M77.3 206.9l.9 1.7M78.2 213.9l-.2 .9-.7 1.2M78.2 210.1v2.7M506.3 205.8l.3 .4M507.3 206.1l.2 .1"/>
<path d="M522.2 210.5l.4 .4M523.2 210.8l.3 .1M143.8 255.9h1.7M143.8 255.3h1.7M146.2 255.9h4.3M146.2 255.3h4.3M151.2 255.3h1.7M151.2 255.9h1.7M511.5 286.8l.3 .6M512.2 287.1l.6 .4"/>
</g>
<!-- layer: DATUM_AXES -->
<g fill="none" stroke="#000" stroke-width=".32">
<path d="M41 43.8v-.3h4.4v.3M42.1 44.9v2.1M42.1 48.5v.6M44.2 44.9v2.1M44.2 48.5v.6M60.2 43l-.2 .5h.7l-.2-.5M63.2 43l-.3 .5h.7l-.2-.5M66.1 43l-.2 .5h.7l-.3-.5M69.1 43l-.3 .5h.7l-.2-.5M72 43l-.3 .5h.7l-.2-.5M74.9 43l-.2 .5h.7l-.3-.5M90 43.8v-.3h4.4v.3"/>
<path d="M91.1 44.9v2.1M91.1 48.5v.6M93.2 44.9v2.1M93.2 48.5v.6M71.9 157l.5 .3M74.7 157.3l.3-.4 .4 .4M138.2 268.3a1.37 1.37 0 0 0 1.6 1.4M138.2 266.6h.1M138.2 268.3h.1M139.5 270.9h.3M139.5 270.2h.3M139.5 266.4h.3"/>
<path d="M139.5 265.7h.3M139.8 265.2h-.3a1.33 1.33 0 0 0-1.3 1.4M140.9 270.9h.3M140.9 270.2h.3M140.9 266.4h.3M140.9 265.7h.3M142.6 270.9h6.4M142.8 270.2h6.2M145.5 264.3a1.44 1.44 0 0 1-1.6 1.4M146.2 264.3a2.17 2.17 0 0 1-2.5 2.1"/>
</g>
<!-- layer: DIM_DRIVEN -->
<g fill="#000">
<path d="M208.9 37.4l4.5-.7v1.5zM262.2 36.7l4.5 .7-4.5 .8zM346.4 37.6l4.5-.8v1.5zM399.7 36.8l4.5 .8-4.5 .7zM15.1 40.4h1.5l-.8 4.5zM15.8 58.4l.8 4.5h-1.5zM122 40.4h1.5l-.8 4.5zM122.7 57.1l.8 4.5h-1.5zM195.7 52.2h1.5l-.7 4.5zM232.6 50.2l4.5 .7-4.5 .8zM233.3 46.7l4.5 .7-4.5 .8zM233.3 42.5l4.5 .8-4.5 .7z"/>
<path d="M238.5 50.9l4.5-.7v1.5zM244.8 47.4l4.5-.7v1.5zM246.7 43.3l4.5-.8v1.5zM259.4 39.9l4.5 .8-4.5 .7zM266.7 40.7l4.5-.8v1.5zM274.9 54.3h1.5l-.8 4.5zM290.3 52.2h1.5l-.7 4.5zM291.1 58.8l.7 4.5h-1.5zM305.5 56.7l.7 4.5h-1.5zM334.1 52.2h1.5l-.8 4.5zM370.1 52.4l4.5 .8-4.5 .7zM370.8 47.7l4.5 .8-4.5 .7z"/>
<path d="M370.8 43.3l4.5 .8-4.5 .7zM376 53.2l4.5-.8v1.5zM382.2 48.5l4.5-.8v1.5zM384.1 44.1l4.5-.8v1.5zM396.9 49.1l4.5 .7-4.5 .8zM404.2 49.8l4.5-.7v1.5zM411.8 54.3h1.5l-.8 4.5zM424.2 52.2h1.5l-.8 4.5zM424.9 58.8l.8 4.5h-1.5zM438.8 56.7l.8 4.5h-1.5zM196.5 63.7l.7 4.5h-1.5zM275.6 64.7l.8 4.5h-1.5z"/>
<path d="M334.8 63.7l.8 4.5h-1.5zM412.5 64.7l.8 4.5h-1.5zM473.5 68.3l.4 4.6-1.5-.1zM487.8 69.2l.5 4.5-1.5-.1zM509.9 62.3l4.5-.5-.1 1.5zM539.3 63.3l4.5 1-4.5 .5zM554 75l.4 4.6-1.4-.1zM553.6 68.7l1.5 .1-1 4.4zM130.2 84.2l.8 4.5h-1.5zM229.1 98l4.5 .8-4.5 .7zM242 98.8l4.5-.8v1.5zM486.1 85.3l1.5 .1-1 4.4z"/>
<path d="M173.8 114.9h1.5l-.7 4.5zM426.9 114.9h1.5l-.7 4.5zM470.6 103.6l1.5 .1-1 4.5zM478.4 110.8l1.5 .1-1 4.5zM491.4 98.9l4 2.1-4.5-.7zM499.1 102.2l4.5 .7-.5 1.4zM553 119.8l.5 4.6-1.5-.1zM552.9 108.6l1.5 .1-1 4.4zM174.6 127.8l.7 4.5h-1.5zM180.6 127.8l.7 4.5h-1.5zM179.8 117.2h1.5l-.7 4.5zM186.7 127.8l.7 4.5h-1.5z"/>
<path d="M185.9 120.3h1.5l-.7 4.5zM191.7 127.8l.8 4.5h-1.5zM191 121.6h1.5l-.8 4.5zM204.4 133.6l4.5 .7-4.5 .8zM229.9 134.3l4.5-.7v1.5zM233.7 120.9l1.2-.9 2.2 3.9zM238.8 117h1.5l-.8 4.5zM239.5 127.8l.8 4.5h-1.5zM245.2 130.4l4.5 .7-4.5 .8zM245.2 135.7l4.5 .7-4.5 .8zM252.7 131.1l4.5-.7v1.5zM255.6 136.4l4.5-.7v1.5z"/>
<path d="M265.8 117l1.3 .6-2.5 3.8zM304.7 123.3h1.5l-.7 4.5zM318.9 127.8l.7 4.5h-1.5zM318.1 117.2h1.5l-.7 4.5zM324.4 127.8l.7 4.5h-1.5zM323.6 120.3h1.5l-.7 4.5zM329.1 127.8l.8 4.5h-1.5zM328.4 121.6h1.5l-.8 4.5zM364.3 118.4l1.1-.9 2.3 3.9zM370.8 133.9l4.5 .7-4.5 .8zM376.7 134.6l4.5-.7v1.5zM400.2 125.7l2.4 3.9-1.4 .6z"/>
<path d="M414.1 127.8l.8 4.5h-1.5zM413.4 117h1.5l-.8 4.5zM427.7 127.8l.7 4.5h-1.5zM438.1 123.3h1.5l-.8 4.5zM478.5 122.1l.5 4.5-1.5-.1zM227.1 158.3l4.5-.7v1.5zM233.3 143l4.5 .8-4.5 .7zM249.7 143.8l4.5-.8v1.5zM245.2 141.1l4.5 .7-4.5 .8zM245.2 146l4.5 .7-4.5 .8zM245.2 151.3l4.5 .8-4.5 .7zM258.5 141.8l4.5-.7v1.5z"/>
<path d="M261.5 146.7l4.5-.7v1.5zM264.4 152.1l4.5-.8v1.5zM340.2 157.6l4.5 .7-4.5 .8zM364.8 152.8l4.5-.8v1.5zM370.8 145.7l4.5 .8-4.5 .7zM370.8 140.1l4.5 .7-4.5 .8zM379.7 140.8l4.5-.7v1.5zM382.6 146.5l4.5-.8v1.5zM381.3 152l4.5 .8-4.5 .7zM391.3 148.9l4.5 .7-4.5 .8zM404.2 149.6l4.5-.7v1.5zM129.5 172.9h1.5l-.8 4.5z"/>
<path d="M235.1 164l4.5-.7v1.5zM260.9 170.7l4.5-.7v1.5zM306.4 170l4.5 .7-4.5 .8zM332.2 163.3l4.5 .7-4.5 .8zM375.3 162.2l4.5-.7v1.5zM395.3 161.5l4.5 .7-4.5 .8zM430.1 167.7l4.5-.8v1.5zM441 166.9l4.5 .8-4.5 .7zM476.1 178l.8 4.5h-1.5zM185.4 187l.8 4.5h-1.5zM310.8 189.4l4.3-1.5 .3 1.5zM20 200.9l.7 4.5h-1.5z"/>
<path d="M19.2 221.6h1.5l-.7 4.5zM460.8 223l.8 4.5h-1.5zM207.8 241h1.5l-.7 4.5zM208.6 253l.7 4.5h-1.5zM287.9 251.5l3.3-3.2 .8 1.3zM340 245.4l1.3 .8-2.8 3.6zM343.1 257.7l4.1 2.1-.9 1.2zM184.7 262.5h1.5l-.8 4.5zM185.4 267l.8 4.5h-1.5zM184.7 287.5h1.5l-.8 4.5zM207.8 287.5h1.5l-.7 4.5zM460.1 278.5h1.5l-.8 4.5z"/>
<path d="M475.4 287.5h1.5l-.8 4.5zM226.5 309.6l4.5-.8v1.5zM254.6 316.7l4.5-.7v1.5zM278.4 301.6l4.5-.8v1.5zM288.9 300.8l4.5 .8-4.5 .7zM312.6 316l4.5 .7-4.5 .8zM340.8 308.8l4.5 .8-4.5 .7zM406.3 312.5l4.5 .7-4.5 .8zM406.3 300.5l4.5 .7-4.5 .8zM443.3 300.9l4.5-.8v1.5zM445.5 313.2l4.5-.7v1.5zM377.7 329.6l.8 4.5h-1.5z"/>
<path d="M202.3 346.3h1.5l-.7 4.5zM203.1 352.7l.7 4.5h-1.5zM266.6 352.7l.8 4.5h-1.5zM265.9 347.8h1.5l-.8 4.5zM377 351.4h1.5l-.8 4.5zM233.1 380.4l4.5-.7v1.5zM334.1 379.7l4.5 .7-4.5 .8z"/>
</g>
<g fill="none" stroke="#000" stroke-width=".32">
<path d="M15.8 36.9v8M122.7 36.9v8M208.9 37.4l4.5-.7v1.5zM208.9 34.4v14.6M208.9 37.4h21.4M245.3 37.4h21.4M259.4 39.9l4.5 .8-4.5 .7zM262.2 36.7l4.5 .7-4.5 .8zM263.9 37.7v14.3M266.7 34.4v16.9M346.4 37.6l4.5-.8v1.5zM346.4 34.6v16.7"/>
<path d="M346.4 37.6h21.4M382.8 37.6h21.4M399.7 36.8l4.5 .8-4.5 .7zM404.2 34.6v24.8M12.8 58.4h28.8M12.8 44.9h24.5M15.1 40.4h1.5l-.8 4.5zM15.8 58.4l.8 4.5h-1.5zM15.8 58.4v9.4h4.5M95.6 57.1h30.1M98.1 44.9h27.6M122 40.4h1.5l-.8 4.5z"/>
<path d="M122.7 57.1l.8 4.5h-1.5zM122.7 57.1v8M193.5 56.7h18.1M195.7 52.2h1.5l-.7 4.5zM196.5 48.7v8M208.9 51.2v8.2M227 47.4h10.8M227.1 43.3h10.7M229.5 50.9h7.6M232.6 50.2l4.5 .7-4.5 .8zM233.3 46.7l4.5 .7-4.5 .8zM233.3 42.5l4.5 .8-4.5 .7z"/>
<path d="M237.1 47.9v9.4M237.8 40.3v11.9M238.5 50.9l4.5-.7v1.5zM238.5 47.9v9.4M238.5 50.9h8M244.8 47.4l4.5-.7v1.5zM244.8 44.4v5.9M244.8 51.5v5.8M244.8 47.4h8M246.7 43.3l4.5-.8v1.5zM246.7 40.3v6.5M246.7 48.1v9.2"/>
<path d="M246.7 43.3h8M255.9 40.7h8M263.9 54.4v2.9M264 56.7h10.6M265.4 58.8h28.7M266.7 40.7l4.5-.8v1.5zM266.7 53.1v6.3M266.7 40.7h8.7M274.9 54.3h1.5l-.8 4.5zM275.6 50.8v8M276.5 56.7h32M290.3 52.2h1.5l-.7 4.5z"/>
<path d="M291.1 58.8l.7 4.5h-1.5zM291.1 58.8v8M295.6 47.1h-4.5v9.6M305.5 56.7l.7 4.5h-1.5zM305.5 56.7v34.7M331.8 56.7h17.3M334.1 52.2h1.5l-.8 4.5zM334.8 48.7v8M346.4 52.7v6.7M363.5 48.5h11.8M363.7 44.1h11.6M365.8 53.2h8.8"/>
<path d="M370.1 52.4l4.5 .8-4.5 .7zM370.8 47.7l4.5 .8-4.5 .7zM370.8 43.3l4.5 .8-4.5 .7zM374.6 50.2v7.1M375.3 41.1v11.1M376 53.2l4.5-.8v1.5zM376 50.2v7.1M376 53.2h8M382.2 48.5l4.5-.8v1.5zM382.2 45.5v7.4M382.2 53.6v3.7M382.2 48.5h8"/>
<path d="M384.1 44.1l4.5-.8v1.5zM384.1 41.1v6.6M384.1 49.3v8M384.1 44.1h8M393.4 49.8h8M396.9 49.1l4.5 .7-4.5 .8zM401.4 46.8v10.5M401.5 56.7h2.2M402.9 58.8h25M404.2 49.8l4.5-.7v1.5zM404.2 49.8h7.6M405 56.7h6.4"/>
<path d="M411.8 54.3h1.5l-.8 4.5zM412.5 50.8v8M413.5 56.7h28.3M424.2 52.2h1.5l-.8 4.5zM424.9 58.8l.8 4.5h-1.5zM424.9 58.8v8M429.4 42.8h-4.5v13.9M438.8 56.7l.8 4.5h-1.5zM438.8 56.7v32.6M510 59.3l-.5 9.7M193.5 63.7h42.1M196.2 79.6h4.5l36.4 44.3"/>
<path d="M196.5 63.7l.7 4.5h-1.5zM196.5 63.7v8M248.2 64.7h30.4M275.6 64.7l.8 4.5h-1.5zM275.6 64.7v6.6h4.5M331.8 63.7h41.3M334.8 63.7l.8 4.5h-1.5zM334.8 63.7v8M385.6 64.7h29.9M412.5 64.7l.8 4.5h-1.5zM412.5 64.7v7.1h4.5M470.5 68.2l37.4 2.2"/>
<path d="M473.5 68.3l.4 4.6-1.5-.1zM473.5 68.3l-1.1 16.9M487.8 69.2l.5 4.5-1.5-.1zM487.8 69.2l-.4 7.3M509.9 62.3l4.5-.5-.1 1.5zM509.9 62.3l9.4 .6M534.3 63.8l9.5 .5M539.3 63.3l4.5 1-4.5 .5zM544 61.3l-.6 9.8M544.8 72.6l12.3 .8M549.4 74.8l7.6 .4M553.6 68.7l1.5 .1-1 4.4z"/>
<path d="M554 75l.4 4.6-1.4-.1zM554 75l-.5 8M559 66.4h-4.5l-.4 6.8M93.8 84.2h39.4M130.2 84.2l.8 4.5h-1.5zM130.2 84.2v45.1M179.1 95.2h-4.5v24.2M225.6 98.8h8M229.1 98l4.5 .8-4.5 .7zM233.6 95.8v23.1M242 98.8l4.5-.8v1.5zM242 98.8h6.6"/>
<path d="M242 95.8v10.3M305.5 97.4v30.4M334.5 86.7h4.5l28.7 34.7M438.8 95.3v32.5M472.1 91.2l-1 17M483.6 89.7l13.7 .8M484.2 98.8h4.5l6.7 2.2M486.1 85.3l1.5 .1-1 4.4zM487 82.5l-.4 7.3M491.4 98.9l4 2.1-4.5-.7zM502.3 92.2l-4.2 12.8M171.6 119.4h7.5"/>
<path d="M173.8 114.9h1.5l-.7 4.5zM179.8 117.2h1.5l-.7 4.5zM181.7 119.4h3.9M185.1 101.2h-4.5v20.5M187.4 119.4h3.4M191.2 107.1h-4.5v17.7M192.6 119.4h17.6M196.2 113.2h-4.5v12.9M238.8 117h1.5l-.8 4.5zM242 109.6v10.4M244 108.1h-4.5v13.4M265.8 117l1.3 .6-2.5 3.8z"/>
<path d="M275.9 106.8h-4.5l-6.8 14.6M318.1 117.2h1.5l-.7 4.5zM323.4 103.6h-4.5v18.1M328.9 109.4h-4.5v15.4M333.6 114.8h-4.5v11.3M364.3 118.4l1.1-.9 2.3 3.9zM387.3 119.4h24.8M413.4 117h1.5l-.8 4.5zM414.1 113.5v8M415.6 119.4h15.1M426.9 114.9h1.5l-.7 4.5zM427.7 111.4v8"/>
<path d="M468.1 108l9.2 .5M470.6 103.6l1.5 .1-1 4.5zM475.9 115.2l17.8 1.1M478.4 110.8l1.5 .1-1 4.5zM479.4 107.4l-.5 8M481.1 108.8l10.1 .6M499.1 102.2l4.5 .7-.5 1.4zM499.1 102.2l7.6 2.4M536 112.1l20.4 1.2M538.6 119l17.4 1M552.9 108.6l1.5 .1-1 4.4zM553 119.8l.5 4.6-1.5-.1z"/>
<path d="M553 119.8l-.5 8M553.9 105.1l-.5 8M130.2 135.3v42.1M171.6 127.8h35.8M174.6 127.8l.7 4.5h-1.5zM174.6 127.8v8M177.6 121.7h7.9M180.6 127.8l.7 4.5h-1.5zM180.6 127.8v8M183.7 124.8h6.6M185.9 120.3h1.5l-.7 4.5zM186.7 127.8l.7 4.5h-1.5z"/>
<path d="M186.7 127.8v8M187.9 121.7h2.5M188.7 126.1h21M191 121.6h1.5l-.8 4.5zM191.7 127.8l.8 4.5h-1.5zM191.7 127.8v8M193.1 124.8h43.2M193.1 121.7h16.6M200.9 134.3h8M204.4 133.6l4.5 .7-4.5 .8zM208.9 129.3v8M229.9 134.3l4.5-.7v1.5z"/>
<path d="M229.9 134.3h8M229.9 129.3v8M233.7 120.9l1.2-.9 2.2 3.9zM237.8 134.8v12M239.5 127.8l.8 4.5h-1.5zM239.5 127.8v8M241.7 136.4h8M241.7 131.1h8M245.2 130.4l4.5 .7-4.5 .8zM245.2 135.7l4.5 .7-4.5 .8zM249.7 127.6v27.5M252.7 131.1l4.5-.7v1.5z"/>
<path d="M252.7 131.1h24.1M252.7 127.6v6.5M255.6 136.4l4.5-.7v1.5zM255.6 136.4h21.2M255.6 127.6v2.2M255.6 132.5v6.9M258.5 127.6v2.2M258.5 132.1v3M258.5 137.6v7.2M261.5 127.6v2.6M261.5 132.2v3.4M261.5 137.4v3.3"/>
<path d="M264.4 127.6v2.6M264.4 132.3v3.6M264.4 137.6v3.3M268.2 127.8h40.3M304.7 123.3h1.5l-.7 4.5zM315.9 127.8h29M315.9 121.7h6.9M318.9 127.8l.7 4.5h-1.5zM318.9 127.8v8M321.4 124.8h6M323.6 120.3h1.5l-.7 4.5zM324.4 127.8l.7 4.5h-1.5z"/>
<path d="M324.4 127.8v8M325.4 121.7h1.9M326.1 126.1h40.3M328.4 121.6h1.5l-.8 4.5zM329.1 127.8l.8 4.5h-1.5zM329.1 127.8v8M330.2 124.8h17M331.3 121.7h35.1M357.9 134.6h17.4M364.8 129.3v4.1M364.8 136v3.8M370.8 133.9l4.5 .7-4.5 .8z"/>
<path d="M375.3 139v11.9M376.7 134.6l4.5-.7v1.5zM376.7 134.6h8M376.7 127.6v10M379.7 127.6v5.2M379.7 136.2v7.6M382.6 127.6v5.3M382.6 136.3v3M385.8 129.3v10.1M395.8 129.3v23.3M399.8 129.6v35.6M400.2 125.7l2.4 3.9-1.4 .6z"/>
<path d="M400.2 125.7l5.7 14.3h4.5M400.8 124.8a1.05 1.05 0 0 1-1.6 .8M402.9 121.5h14.2M404.2 129.3v4.1M404.2 138v14.6M405.7 127.8h36.1M414.1 127.8l.8 4.5h-1.5zM414.1 127.8v8M427.7 127.8l.7 4.5h-1.5zM427.7 127.8v8M438.1 123.3h1.5l-.8 4.5zM475.5 121.9l13.8 .8"/>
<path d="M478.5 122.1l.5 4.5-1.5-.1zM478.5 122.1l-.5 8M227.1 158.3l4.5-.7v1.5zM227.1 155.3v96.2M227.1 158.3h47.7M227.7 143.8h10.1M233.3 143l4.5 .8-4.5 .7zM241.7 152.1h8M241.7 146.7h8M241.7 141.8h8M245.2 141.1l4.5 .7-4.5 .8zM245.2 146l4.5 .7-4.5 .8z"/>
<path d="M245.2 151.3l4.5 .8-4.5 .7zM249.7 143.8l4.5-.8v1.5zM249.7 143.8h8M258.5 141.8l4.5-.7v1.5zM258.5 141.8h16.3M261.5 146.7l4.5-.7v1.5zM261.5 146.7h13M261.5 143.2v6.5M264.4 152.1l4.5-.8v1.5zM264.4 152.1h10.4M264.4 142.8v2.5M264.4 148.4v6.7"/>
<path d="M297 158.3h47.7M340.2 157.6l4.5 .7-4.5 .8zM344.7 155.3v53.4M357.9 140.8h17.4M358 146.5h17.3M358.4 152.8h27.4M364.8 152.8l4.5-.8v1.5zM364.8 142.3v3M364.8 147.8v8M370.8 145.7l4.5 .8-4.5 .7zM370.8 140.1l4.5 .7-4.5 .8zM375.3 155.1v10.1"/>
<path d="M379.7 140.8l4.5-.7v1.5zM379.7 140.8h8M381.3 152l4.5 .8-4.5 .7zM382.6 146.5l4.5-.8v1.5zM382.6 146.5h8M382.6 142.8v6.7M385.8 141.7v2.6M385.8 148.3v7.5M387.8 149.6h8M391.3 148.9l4.5 .7-4.5 .8zM404.2 149.6l4.5-.7v1.5zM404.2 149.6h7.9"/>
<path d="M82.5 177.4h50.7M129.5 172.9h1.5l-.8 4.5zM235.1 164l4.5-.7v1.5zM235.1 161v90.5M235.1 164h36.1M260.9 170.7l4.5-.7v1.5zM260.9 167.7v20.8M260.9 170.7h11.5M299.3 170.7h11.6M300.5 164h36.2M306.4 170l4.5 .7-4.5 .8zM310.9 167.7v20.8"/>
<path d="M332.2 163.3l4.5 .7-4.5 .8zM336.7 161v90.5M375.3 162.2l4.5-.7v1.5zM375.3 162.2h4.7M395 162.2h4.8M395.3 161.5l4.5 .7-4.5 .8zM430.1 167.7l4.5-.8v1.5zM430.1 164.7v78M430.1 167.7h19.4M439.8 178h4.3M441 166.9l4.5 .8-4.5 .7zM445.5 164.7v57.2"/>
<path d="M446.8 178h32.3M476.1 178l.8 4.5h-1.5zM476.1 178v32.5M182.4 187h80M185.4 187l.8 4.5h-1.5zM185.4 187v37M310.8 189.4l4.3-1.5 .3 1.5zM350.4 183h-4.5l-35.1 6.4M17 200.9h19.8M20 200.9l.7 4.5h-1.5zM20 200.9v31.9h4.5M344.7 215.1v19.8"/>
<path d="M350.7 210.5h-4.5l-58.3 41M476.1 216.5v75.5M17 226.1h9M19.2 221.6h1.5l-.7 4.5zM185.4 230v46.5M208.6 237.5v8M353.8 230h-4.5l-10.8 19.8M446 223h17.8M460.8 223l.8 4.5h-1.5zM460.8 223v27M205.6 253h28M205.6 245.5h78.8"/>
<path d="M207.8 241h1.5l-.7 4.5zM208.6 253l.7 4.5h-1.5zM208.6 253v16.5M287.9 251.5l3.3-3.2 .8 1.3zM340 245.4l1.3 .8-2.8 3.6zM343.1 257.7l4.1 2.1-.9 1.2zM343.1 257.7l11.1 8.2h4.5M343.2 257.6l-1 1.2M344.7 241v10.5M406.8 246.5a2.67 2.67 0 0 1 0 3M460.8 256v27M182.4 267h22.4"/>
<path d="M184.7 262.5h1.5l-.8 4.5zM185.4 267l.8 4.5h-1.5zM208.6 275.5v16.5M212.2 267h50.2M460.1 278.5h1.5l-.8 4.5zM182.4 292h59.7M184.7 287.5h1.5l-.8 4.5zM185.4 282.5v9.5M207.8 287.5h1.5l-.7 4.5zM226.5 281.6v31M278.4 289v15.6M293.4 289v15.6"/>
<path d="M345.3 281.6v16.9M443.3 293.5l.1 10.4M444.8 292h34.3M445.5 284.1v14.7M447 283h16.8M475.4 287.5h1.5l-.8 4.5zM226.5 309.6l4.5-.8v1.5zM226.5 309.6h44.7M254.6 316.7l4.5-.7v1.5zM254.6 313.7v18.5M254.6 316.7h17.8M278.4 301.6l4.5-.8v1.5z"/>
<path d="M278.4 301.6h23.1M288.9 300.8l4.5 .8-4.5 .7zM299.2 316.7h17.9M300.5 309.6h44.8M312.6 316l4.5 .7-4.5 .8zM317.1 313.7v18.5M340.8 308.8l4.5 .8-4.5 .7zM345.3 302.7v9.9M402.8 313.2h8M406.3 312.5l4.5 .7-4.5 .8zM406.3 300.5l4.5 .7-4.5 .8zM410.8 301.2h-8"/>
<path d="M410.9 304.2l-.1-10.7v22.7M443.3 300.9l4.5-.8v1.5zM445.5 313.2l4.5-.7v1.5zM445.5 313.2h8M445.5 304.2v12M451.3 300.8l-8 .1M329.4 329.6h51.3M377.7 329.6l.8 4.5h-1.5zM377.7 329.6v10.1M200.1 352.7h41.1M200.1 350.8h41.2M202.3 346.3h1.5l-.7 4.5z"/>
<path d="M203.1 352.7l.7 4.5h-1.5zM203.1 342.8v8M203.1 352.7v16.4h4.5M233.1 351.8v31.6M249.4 352.7h20.2M263.6 352.3h19.8M265.9 347.8h1.5l-.8 4.5zM266.6 352.7l.8 4.5h-1.5zM266.6 352.7v16.5h4.5M266.6 344.3v8M329.4 355.9h51.3M338.6 351.8v31.6"/>
<path d="M377 351.4h1.5l-.8 4.5zM377.7 345.7v10.2M410.7 341.2h-1.2v3h1.2M334.1 379.7l4.5 .7-4.5 .8zM233.1 380.4l4.5-.7v1.5zM233.1 380.4h39.4M301.8 380.4h36.8"/>
</g>
<!-- layer: DRAFT_ENTITY -->
<g fill="none" stroke="#000" stroke-width=".32">
<path d="M382.2 58.8h1.9v5.9h-1.9zM382.7 58.8l-.5 .5M383.4 58.8l-1.2 1.2M384.1 58.8l-1.9 1.9M384.1 59.5l-1.9 1.9M384.1 60.2l-1.9 1.9M384.1 60.9l-1.9 1.9M384.1 61.6l-1.9 1.9M384.1 62.4l-1.9 1.8M384.1 63.1l-1.7 1.6M384.1 63.8l-1 .9M384.1 64.5l-.3 .2"/>
<path d="M560.1 389v12.7"/>
</g>
<!-- layer: DRAFT_GRP -->
<g fill="none" stroke="#000" stroke-width=".32">
<path d="M229 58.8h1.8v5.9h-1.8zM229.2 58.8l-.2 .3M229.9 58.8l-.9 1M230.6 58.8l-1.6 1.7M230.8 59.4l-1.8 1.8M244.8 58.8h1.9v5.9h-1.9zM245.5 58.8l-.7 .7M246.2 58.8l-1.4 1.4M246.7 59.1l-1.9 1.8M246.7 59.8l-1.9 1.8M366.5 58.8h1.8v5.9h-1.8zM367.1 58.8l-.6 .7"/>
<path d="M367.8 58.8l-1.3 1.4M368.3 59.1l-1.8 1.8M368.3 59.8l-1.8 1.8M230.8 60.1l-1.8 1.8M230.8 60.8l-1.8 1.8M230.8 61.5l-1.8 1.8M230.8 62.2l-1.8 1.8M230.8 62.9l-1.8 1.8M230.8 63.6l-1.1 1.1M230.8 64.3l-.4 .4M246.7 60.5l-1.9 1.8M246.7 61.2l-1.9 1.8"/>
<path d="M246.7 61.9l-1.9 1.9M246.7 62.6l-1.9 1.9M246.7 63.3l-1.4 1.4M246.7 64l-.7 .7M368.3 60.5l-1.8 1.8M368.3 61.2l-1.8 1.8M368.3 61.9l-1.8 1.8M368.3 62.6l-1.8 1.8M368.3 63.3l-1.4 1.4M368.3 64l-.7 .7M368.3 64.7h.1"/>
</g>
<!-- layer: DTM_AXIS -->
<path d="M505.7 196.7l-.2 .2M507 195.5l-.3 .3M536.6 214.8l-.3 .2M537.8 213.6l-.2 .3M542.7 207.6l.4 1.2M547.8 203.5l1.1 3.3" fill="none" stroke="#000" stroke-width=".32"/>
<!-- layer: DTM_CURVE -->
<g fill="none" stroke="#000" stroke-width=".32">
<path d="M50.1 56.5l.3 .6M50.1 55.9v.6M50.1 56.5l-.3 .6M51.1 56.5h.5M52.3 55.9l.6 1.2M52.9 55.9l-.6 1.2M53.5 55.9h.7v1.2h-.7M53.8 56.5h.4M81.8 46.4h2.6v4.9h-2.6zM83.3 54.3h.4M85.1 53.7v1.2l-.6-.1v-.4l.6-.1M85.7 53.7h.6l-.6 .8 .2 .4 .4-.2"/>
<path d="M86.9 56.7h.6M86.9 56.1v1.2M87.2 53.7v1.2M87.5 56.1v1.2M88.2 56.3l.2-.2a.58 .58 0 0 1 .5 .6 .58 .58 0 0 1-.7 .5v-.1M88.2 54.3h.5M89.4 57.1l.2 .2 .4-.2M89.6 54.4l-.2 .3 .4 .2M89.6 54.4h.2M89.8 56.1l-.4 .2 .4 .5M89.8 53.7l-.5 .3 .3 .4M90.6 57.3h.8"/>
<path d="M91 57.1v.2M91.9 57.1v.2M92.5 57.1v.2M93.8 57.1v.2h-.7M72.8 164.8h27.1M517.7 193.4l19.5-17.3 1-.1 13.1 4-.2 .7-19.4 17.3-1.1 .1-12.8-3.7-.3-.4zM36.2 206.2l-.1 .3M36.2 206.2l.1 .1M36.3 206.3h.1M36.3 206.3v.1M36.3 206.3h.3v.2M36.8 205.5l-.2 .3-.3-.5 .6 .3"/>
<path d="M36.8 206.9l.1 .2h-.6l.1 .3M37.1 204.7l-.1 .3 .3 .1-.2 .2M37.1 205.3h.1M37.1 206.1l.4 .7M37.3 207.4l-.3 .6M37.5 206.1l-.4 .7M37.6 207.6l.2 .6M37.9 205.6l.3 .5h-.2v1h-.2v-1h-.2zM38 204.6l-.1-.1-.1 .4M38 207.6v.7M38.4 207.5l.3 .6M38.4 206.1l.4 .7"/>
<path d="M38.7 207.3l.3 .6M38.7 204.6l.3 .2-.5 .5M38.8 206.1l-.4 .7M39 205.5v.2l.2 .1M39.1 206.8l.5 .3M39.1 205.5h-.1M39.3 205.8h-.1M39.3 206.2l-.1 .2 .4 .1M39.3 205.5v.1M39.3 205.4v.1M39.3 205.6v.2M39.3 205.3l.2 .3-.4-.1"/>
<path d="M39.3 205.3v.1M39.4 207.4h.1M39.5 207.4l-.6-.3 .5 .3M39.5 207.4h.1M39.5 207.4h-.1M501.7 278.5l.5-.2 .8 .5 .5 .8-.2 .6h-.6l-.7-.5-.4-.7zM501.7 279v.1M501.7 279h.1M501.8 279h.1M501.8 279v.1M501.8 279.4l.1 .1M501.8 279.4h.1"/>
<path d="M501.9 279h.1M501.9 279h-.1M501.9 279l.1 .1M501.9 279.4h.1M501.9 279.4h-.1M501.9 278.7l-.2-.1 .3 .2M502 279.1h.1M502 278.4v.1M502 278.5h.1M502 279.3l-.1 .1M502.1 278.7h.1M502.1 278.5v.1"/>
<path d="M502.1 278.8l.7 .3 .1 .6-.7-.2zM502.1 279.1l.2 .3M502.1 278.6l.1 .1M502.2 278.7h.1M502.3 279.1l-.1 .2M502.3 279.7l-.1 .2M502.3 278.5v.1M502.3 278.6l.1 .1M502.4 278.5h-.1M502.4 278.7h.1M502.4 278.4v.1M502.4 278.6h.1"/>
<path d="M502.4 278.5h.1M502.5 278.6v.1M502.5 278.9l.1 .8zM502.5 278.7h.1M502.5 279.8v.2M502.7 279.9v.3M502.7 279.3l.2 .3M502.8 278.7l-.1 .2M502.8 279.9l.2 .3M502.9 279.3l-.1 .3M502.9 279.9l.2 .3M503 279.2h.1"/>
<path d="M503 279.2l.1 .1M503.1 279.8h.1M503.1 279.8v.1M503.1 279.7l.3 .2M503.1 279.3h.1M503.1 279.5l.1 .1M503.1 279.1v.2M503.1 279.5h.1M503.1 279.1h.1M503.1 279.8l.2 .2M503.2 279.6h.1M503.2 279.1h.1"/>
<path d="M503.2 279.1v.1M503.2 279.2h.1M503.2 279.5l.1 .1M503.2 279.9l.1 .1M503.3 280h.1M503.3 279.6h.1M503.3 279.5h-.1M503.3 279.5l.1 .1M503.4 279.6h.1M502.5 280v.1M502.5 280.1h.1M502.6 280.1h.1"/>
<circle cx="37.9" cy="206.4" r="2.1"/>
<circle cx="37.9" cy="206.4" r="1.05"/>
<circle cx="37.9" cy="204.9" r=".16"/>
<circle cx="39.7" cy="206.3" r=".16"/>
</g>
<!-- layer: DWG_TABLE -->
<path d="M446.8 338.9h133.4v18.3h-133.4zM491.3 338.9v18.3M535.7 338.9v18.3M446.8 351.2h133.4M446.8 345.2h133.4" fill="none" stroke="#000" stroke-width=".32"/>
<!-- layer: NOTE -->
<g fill="#000">
<path d="M237.2 61.1l.5-.4 .6 .2 .3 .6-.3 .5-.6 .2-.5-.4zM246.7 61.9l3.7-2.6 .6 1.3zM347 79.1l.5-.4 .6 .1 .3 .6-.3 .6-.6 .1-.5-.4zM362.7 58.4l3.8 2.5-4.5-1.1zM374.9 61.1l.6-.4 .6 .2 .3 .6-.3 .6-.6 .1-.6-.4zM264.4 84.2l.5-.4 .7 .2 .3 .5-.3 .6-.7 .2-.5-.4zM92.5 156.6l2.5 3.8-1.4 .7zM76.9 218.2l4.6 .1-.3 1.5zM265.3 203.3l.5-.4 .7 .2 .2 .6-.2 .5-.7 .2-.5-.4zM157.7 249.2l1.2 .9-3.4 3zM289.2 275.6l4.4 1.1-.6 1.4zM69.5 280.6l1.4 .7-2.8 3.6z"/>
<path d="M135.8 278.3l4 2.2-4.5-.7zM140.9 283.6l3.9 2.3-.9 1.2zM81.8 302.7l3.1 3.4-1.3 .8zM157 314.7l2.9 3.5-1.3 .8z"/>
</g>
<g fill="none" stroke="#000" stroke-width=".32">
<path d="M204.6 17.5h60.8M345.1 17.7h60.8M26.8 30.4h83.8M207.3 22h55.5M305.7 33.7l-59 28.2M305.7 33.7h6M305.7 33.7l60.8 27.2M347.7 22.2h55.5M195.1 46.8h6l36 14.4M362.7 58.4l3.8 2.5-4.5-1.1zM55.2 71.8h19.9M237.2 61.1l.5-.4 .6 .2 .3 .6-.3 .5-.6 .2-.5-.4z"/>
<path d="M246.7 61.9l3.7-2.6 .6 1.3zM332 75h6l9 4.1M347 79.1l.5-.4 .6 .1 .3 .6-.3 .6-.6 .1-.5-.4zM374.9 61.1l.6-.4 .6 .2 .3 .6-.3 .6-.6 .1-.6-.4zM376.2 62l25.9 21.5h6M264.4 84.2l.5-.4 .7 .2 .3 .5-.3 .6-.7 .2-.5-.4zM265.6 85.1l4.8 6.5h6M476.6 137.9h61.9M92.5 156.6l2.5 3.8-1.4 .7zM92.5 156.6l13.8 31h6M537 143.6h1.5M570.8 158.6h.7"/>
<path d="M572 157.1h-1.2v3h1.2M576 150.9l.2 .2zM217.8 173.5h6l41.6 29.7M578.4 164.4l.2 .2zM153 195.6l.3 .9-.3 1.1M76.9 218.2l4.6 .1-.3 1.5zM76.9 218.2l31.9 6.2h6M265.3 203.3l.5-.4 .7 .2 .2 .6-.2 .5-.7 .2-.5-.4zM487.7 229.4h17.7M560.3 235.3a1.58 1.58 0 0 1 1.3 1.1 1.58 1.58 0 0 1-.4 1.7l-.9 .2zM575.9 239.8h-1.2v3h1.2M94.3 245.6h-6l-20.2 39.3"/>
<path d="M157.7 249.2l1.2 .9-3.4 3zM165.4 248.3h-6l-3.9 4.8M574.7 241.3h.7M122.5 276.7h6l11.3 3.8M135.8 278.3l4 2.2-4.5-.7zM289.2 275.6l4.4 1.1-.6 1.4zM289.2 275.6l66.5 29h6M69.5 280.6l1.4 .7-2.8 3.6zM140.9 283.6l3.9 2.3-.9 1.2zM140.9 283.6l16.3 13.9h6M81.8 302.7l3.1 3.4-1.3 .8zM81.8 302.7l14.9 22.7h6"/>
<path d="M157 314.7l2.9 3.5-1.3 .8zM157 314.7l4.9 8.3h6M490.3 306.7h17.7M573.7 313.1l-.4-.5a1.6 1.6 0 0 0-1.1 1.5 1.6 1.6 0 0 0 1.1 1.5l.4-.5v-1h-.6M143.4 379.1l.2 .2zM199.4 385.8l-.5-.5a.69 .69 0 0 0-.7 .8l.4 .5a.88 .88 0 0 1 .8 .8 .88 .88 0 0 1-.8 .9l-.6-.7M199.7 399h.7l.5-.5v-.5l-.5-.5h-.7v3M200.4 399l.5 1.5M201 388.1l.2 .2zM206.7 396l.8-3 .7 3M207 395h.9M209.4 394v1.5l.3 .5h.3l.3-.5"/>
<path d="M210.3 394v2"/>
</g>
<!-- layer: SYMBOL -->
<path d="M135.8 45.4l4 6.9h-8zM20.1 69.7l4 6.9h-8zM458.5 155.4l4 7h-8zM32.6 373.4l4 6.9h-8zM32.7 382.3l4 7h-8z" fill="none" stroke="#000" stroke-width=".32"/>
<use href="#words"/>
</svg>
